VERSION 5.8 ;
BUSBITCHARS "[]" ;
DIVIDERCHAR "/" ;
UNITS
    DATABASE MICRONS 1000 ;
END UNITS

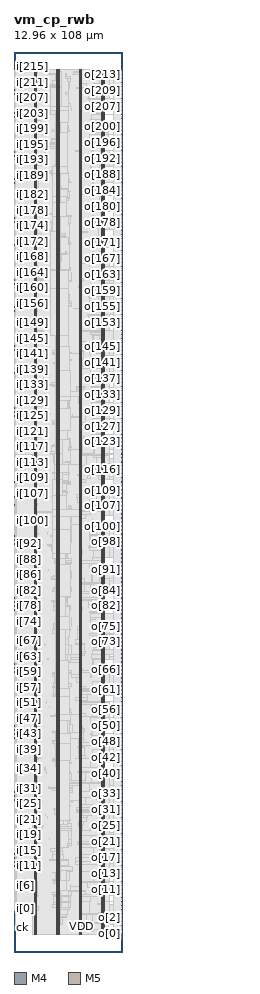
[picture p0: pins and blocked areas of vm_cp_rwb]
MACRO vm_cp_rwb
  FOREIGN vm_cp_rwb 0 0 ;
  CLASS BLOCK ;
  SIZE 12.96 BY 108 ;
  PIN ck
    DIRECTION INPUT ;
    USE SIGNAL ;
    PORT
      LAYER M4 ;
        RECT  0 2.976 0.084 3 ;
    END
    PORT
      LAYER M4 ;
        RECT  0.06 2.976 0.227 3 ;
    END
  END ck
  PIN i[0]
    DIRECTION INPUT ;
    USE SIGNAL ;
    PORT
      LAYER M4 ;
        RECT  0 5.232 0.084 5.256 ;
    END
  END i[0]
  PIN i[100]
    DIRECTION INPUT ;
    USE SIGNAL ;
    PORT
      LAYER M4 ;
        RECT  0 51.744 0.084 51.768 ;
    END
  END i[100]
  PIN i[101]
    DIRECTION INPUT ;
    USE SIGNAL ;
    PORT
      LAYER M4 ;
        RECT  0 52.224 0.084 52.248 ;
    END
  END i[101]
  PIN i[102]
    DIRECTION INPUT ;
    USE SIGNAL ;
    PORT
      LAYER M4 ;
        RECT  0 52.704 0.084 52.728 ;
    END
  END i[102]
  PIN i[103]
    DIRECTION INPUT ;
    USE SIGNAL ;
    PORT
      LAYER M4 ;
        RECT  0 53.184 0.084 53.208 ;
    END
  END i[103]
  PIN i[104]
    DIRECTION INPUT ;
    USE SIGNAL ;
    PORT
      LAYER M4 ;
        RECT  0 53.616 0.084 53.64 ;
    END
  END i[104]
  PIN i[105]
    DIRECTION INPUT ;
    USE SIGNAL ;
    PORT
      LAYER M4 ;
        RECT  0 54.096 0.084 54.12 ;
    END
  END i[105]
  PIN i[106]
    DIRECTION INPUT ;
    USE SIGNAL ;
    PORT
      LAYER M4 ;
        RECT  0 54.576 0.084 54.6 ;
    END
  END i[106]
  PIN i[107]
    DIRECTION INPUT ;
    USE SIGNAL ;
    PORT
      LAYER M4 ;
        RECT  0 55.008 0.084 55.032 ;
    END
  END i[107]
  PIN i[108]
    DIRECTION INPUT ;
    USE SIGNAL ;
    PORT
      LAYER M4 ;
        RECT  0 55.488 0.084 55.512 ;
    END
  END i[108]
  PIN i[109]
    DIRECTION INPUT ;
    USE SIGNAL ;
    PORT
      LAYER M4 ;
        RECT  0 55.968 0.084 55.992 ;
    END
  END i[109]
  PIN i[10]
    DIRECTION INPUT ;
    USE SIGNAL ;
    PORT
      LAYER M4 ;
        RECT  0 9.888 0.084 9.912 ;
    END
  END i[10]
  PIN i[110]
    DIRECTION INPUT ;
    USE SIGNAL ;
    PORT
      LAYER M4 ;
        RECT  0 56.4 0.084 56.424 ;
    END
  END i[110]
  PIN i[111]
    DIRECTION INPUT ;
    USE SIGNAL ;
    PORT
      LAYER M4 ;
        RECT  0 56.88 0.084 56.904 ;
    END
  END i[111]
  PIN i[112]
    DIRECTION INPUT ;
    USE SIGNAL ;
    PORT
      LAYER M4 ;
        RECT  0 57.36 0.084 57.384 ;
    END
  END i[112]
  PIN i[113]
    DIRECTION INPUT ;
    USE SIGNAL ;
    PORT
      LAYER M4 ;
        RECT  0 57.792 0.084 57.816 ;
    END
  END i[113]
  PIN i[114]
    DIRECTION INPUT ;
    USE SIGNAL ;
    PORT
      LAYER M4 ;
        RECT  0 58.272 0.084 58.296 ;
    END
  END i[114]
  PIN i[115]
    DIRECTION INPUT ;
    USE SIGNAL ;
    PORT
      LAYER M4 ;
        RECT  0 58.752 0.084 58.776 ;
    END
  END i[115]
  PIN i[116]
    DIRECTION INPUT ;
    USE SIGNAL ;
    PORT
      LAYER M4 ;
        RECT  0 59.232 0.084 59.256 ;
    END
  END i[116]
  PIN i[117]
    DIRECTION INPUT ;
    USE SIGNAL ;
    PORT
      LAYER M4 ;
        RECT  0 59.664 0.084 59.688 ;
    END
  END i[117]
  PIN i[118]
    DIRECTION INPUT ;
    USE SIGNAL ;
    PORT
      LAYER M4 ;
        RECT  0 60.144 0.084 60.168 ;
    END
  END i[118]
  PIN i[119]
    DIRECTION INPUT ;
    USE SIGNAL ;
    PORT
      LAYER M4 ;
        RECT  0 60.624 0.084 60.648 ;
    END
  END i[119]
  PIN i[11]
    DIRECTION INPUT ;
    USE SIGNAL ;
    PORT
      LAYER M4 ;
        RECT  0 10.32 0.084 10.344 ;
    END
  END i[11]
  PIN i[120]
    DIRECTION INPUT ;
    USE SIGNAL ;
    PORT
      LAYER M4 ;
        RECT  0 61.056 0.084 61.08 ;
    END
  END i[120]
  PIN i[121]
    DIRECTION INPUT ;
    USE SIGNAL ;
    PORT
      LAYER M4 ;
        RECT  0 61.536 0.084 61.56 ;
    END
  END i[121]
  PIN i[122]
    DIRECTION INPUT ;
    USE SIGNAL ;
    PORT
      LAYER M4 ;
        RECT  0 62.016 0.084 62.04 ;
    END
  END i[122]
  PIN i[123]
    DIRECTION INPUT ;
    USE SIGNAL ;
    PORT
      LAYER M4 ;
        RECT  0 62.448 0.084 62.472 ;
    END
  END i[123]
  PIN i[124]
    DIRECTION INPUT ;
    USE SIGNAL ;
    PORT
      LAYER M4 ;
        RECT  0 62.928 0.084 62.952 ;
    END
  END i[124]
  PIN i[125]
    DIRECTION INPUT ;
    USE SIGNAL ;
    PORT
      LAYER M4 ;
        RECT  0 63.408 0.084 63.432 ;
    END
  END i[125]
  PIN i[126]
    DIRECTION INPUT ;
    USE SIGNAL ;
    PORT
      LAYER M4 ;
        RECT  0 63.888 0.084 63.912 ;
    END
  END i[126]
  PIN i[127]
    DIRECTION INPUT ;
    USE SIGNAL ;
    PORT
      LAYER M4 ;
        RECT  0 64.32 0.084 64.344 ;
    END
  END i[127]
  PIN i[128]
    DIRECTION INPUT ;
    USE SIGNAL ;
    PORT
      LAYER M4 ;
        RECT  0 64.8 0.084 64.824 ;
    END
  END i[128]
  PIN i[129]
    DIRECTION INPUT ;
    USE SIGNAL ;
    PORT
      LAYER M4 ;
        RECT  0 65.28 0.084 65.304 ;
    END
  END i[129]
  PIN i[12]
    DIRECTION INPUT ;
    USE SIGNAL ;
    PORT
      LAYER M4 ;
        RECT  0 10.8 0.084 10.824 ;
    END
  END i[12]
  PIN i[130]
    DIRECTION INPUT ;
    USE SIGNAL ;
    PORT
      LAYER M4 ;
        RECT  0 65.712 0.084 65.736 ;
    END
  END i[130]
  PIN i[131]
    DIRECTION INPUT ;
    USE SIGNAL ;
    PORT
      LAYER M4 ;
        RECT  0 66.192 0.084 66.216 ;
    END
  END i[131]
  PIN i[132]
    DIRECTION INPUT ;
    USE SIGNAL ;
    PORT
      LAYER M4 ;
        RECT  0 66.672 0.084 66.696 ;
    END
  END i[132]
  PIN i[133]
    DIRECTION INPUT ;
    USE SIGNAL ;
    PORT
      LAYER M4 ;
        RECT  0 67.104 0.084 67.128 ;
    END
  END i[133]
  PIN i[134]
    DIRECTION INPUT ;
    USE SIGNAL ;
    PORT
      LAYER M4 ;
        RECT  0 67.584 0.084 67.608 ;
    END
  END i[134]
  PIN i[135]
    DIRECTION INPUT ;
    USE SIGNAL ;
    PORT
      LAYER M4 ;
        RECT  0 68.064 0.084 68.088 ;
    END
  END i[135]
  PIN i[136]
    DIRECTION INPUT ;
    USE SIGNAL ;
    PORT
      LAYER M4 ;
        RECT  0 68.544 0.084 68.568 ;
    END
  END i[136]
  PIN i[137]
    DIRECTION INPUT ;
    USE SIGNAL ;
    PORT
      LAYER M4 ;
        RECT  0 68.976 0.084 69 ;
    END
  END i[137]
  PIN i[138]
    DIRECTION INPUT ;
    USE SIGNAL ;
    PORT
      LAYER M4 ;
        RECT  0 69.456 0.084 69.48 ;
    END
  END i[138]
  PIN i[139]
    DIRECTION INPUT ;
    USE SIGNAL ;
    PORT
      LAYER M4 ;
        RECT  0 69.936 0.084 69.96 ;
    END
  END i[139]
  PIN i[13]
    DIRECTION INPUT ;
    USE SIGNAL ;
    PORT
      LAYER M4 ;
        RECT  0 11.28 0.084 11.304 ;
    END
  END i[13]
  PIN i[140]
    DIRECTION INPUT ;
    USE SIGNAL ;
    PORT
      LAYER M4 ;
        RECT  0 70.368 0.084 70.392 ;
    END
  END i[140]
  PIN i[141]
    DIRECTION INPUT ;
    USE SIGNAL ;
    PORT
      LAYER M4 ;
        RECT  0 70.848 0.084 70.872 ;
    END
  END i[141]
  PIN i[142]
    DIRECTION INPUT ;
    USE SIGNAL ;
    PORT
      LAYER M4 ;
        RECT  0 71.328 0.084 71.352 ;
    END
  END i[142]
  PIN i[143]
    DIRECTION INPUT ;
    USE SIGNAL ;
    PORT
      LAYER M4 ;
        RECT  0 71.76 0.084 71.784 ;
    END
  END i[143]
  PIN i[144]
    DIRECTION INPUT ;
    USE SIGNAL ;
    PORT
      LAYER M4 ;
        RECT  0 72.24 0.084 72.264 ;
    END
  END i[144]
  PIN i[145]
    DIRECTION INPUT ;
    USE SIGNAL ;
    PORT
      LAYER M4 ;
        RECT  0 72.72 0.084 72.744 ;
    END
  END i[145]
  PIN i[146]
    DIRECTION INPUT ;
    USE SIGNAL ;
    PORT
      LAYER M4 ;
        RECT  0 73.152 0.084 73.176 ;
    END
  END i[146]
  PIN i[147]
    DIRECTION INPUT ;
    USE SIGNAL ;
    PORT
      LAYER M4 ;
        RECT  0 73.632 0.084 73.656 ;
    END
  END i[147]
  PIN i[148]
    DIRECTION INPUT ;
    USE SIGNAL ;
    PORT
      LAYER M4 ;
        RECT  0 74.112 0.084 74.136 ;
    END
  END i[148]
  PIN i[149]
    DIRECTION INPUT ;
    USE SIGNAL ;
    PORT
      LAYER M4 ;
        RECT  0 74.592 0.084 74.616 ;
    END
  END i[149]
  PIN i[14]
    DIRECTION INPUT ;
    USE SIGNAL ;
    PORT
      LAYER M4 ;
        RECT  0 11.76 0.084 11.784 ;
    END
  END i[14]
  PIN i[150]
    DIRECTION INPUT ;
    USE SIGNAL ;
    PORT
      LAYER M4 ;
        RECT  0 75.024 0.084 75.048 ;
    END
  END i[150]
  PIN i[151]
    DIRECTION INPUT ;
    USE SIGNAL ;
    PORT
      LAYER M4 ;
        RECT  0 75.504 0.084 75.528 ;
    END
  END i[151]
  PIN i[152]
    DIRECTION INPUT ;
    USE SIGNAL ;
    PORT
      LAYER M4 ;
        RECT  0 75.984 0.084 76.008 ;
    END
  END i[152]
  PIN i[153]
    DIRECTION INPUT ;
    USE SIGNAL ;
    PORT
      LAYER M4 ;
        RECT  0 76.416 0.084 76.44 ;
    END
  END i[153]
  PIN i[154]
    DIRECTION INPUT ;
    USE SIGNAL ;
    PORT
      LAYER M4 ;
        RECT  0 76.896 0.084 76.92 ;
    END
  END i[154]
  PIN i[155]
    DIRECTION INPUT ;
    USE SIGNAL ;
    PORT
      LAYER M4 ;
        RECT  0 77.376 0.084 77.4 ;
    END
  END i[155]
  PIN i[156]
    DIRECTION INPUT ;
    USE SIGNAL ;
    PORT
      LAYER M4 ;
        RECT  0 77.808 0.084 77.832 ;
    END
  END i[156]
  PIN i[157]
    DIRECTION INPUT ;
    USE SIGNAL ;
    PORT
      LAYER M4 ;
        RECT  0 78.288 0.084 78.312 ;
    END
  END i[157]
  PIN i[158]
    DIRECTION INPUT ;
    USE SIGNAL ;
    PORT
      LAYER M4 ;
        RECT  0 78.768 0.084 78.792 ;
    END
  END i[158]
  PIN i[159]
    DIRECTION INPUT ;
    USE SIGNAL ;
    PORT
      LAYER M4 ;
        RECT  0 79.248 0.084 79.272 ;
    END
  END i[159]
  PIN i[15]
    DIRECTION INPUT ;
    USE SIGNAL ;
    PORT
      LAYER M4 ;
        RECT  0 12.192 0.084 12.216 ;
    END
  END i[15]
  PIN i[160]
    DIRECTION INPUT ;
    USE SIGNAL ;
    PORT
      LAYER M4 ;
        RECT  0 79.68 0.084 79.704 ;
    END
  END i[160]
  PIN i[161]
    DIRECTION INPUT ;
    USE SIGNAL ;
    PORT
      LAYER M4 ;
        RECT  0 80.16 0.084 80.184 ;
    END
  END i[161]
  PIN i[162]
    DIRECTION INPUT ;
    USE SIGNAL ;
    PORT
      LAYER M4 ;
        RECT  0 80.64 0.084 80.664 ;
    END
  END i[162]
  PIN i[163]
    DIRECTION INPUT ;
    USE SIGNAL ;
    PORT
      LAYER M4 ;
        RECT  0 81.072 0.084 81.096 ;
    END
  END i[163]
  PIN i[164]
    DIRECTION INPUT ;
    USE SIGNAL ;
    PORT
      LAYER M4 ;
        RECT  0 81.552 0.084 81.576 ;
    END
  END i[164]
  PIN i[165]
    DIRECTION INPUT ;
    USE SIGNAL ;
    PORT
      LAYER M4 ;
        RECT  0 82.032 0.084 82.056 ;
    END
  END i[165]
  PIN i[166]
    DIRECTION INPUT ;
    USE SIGNAL ;
    PORT
      LAYER M4 ;
        RECT  0 82.464 0.084 82.488 ;
    END
  END i[166]
  PIN i[167]
    DIRECTION INPUT ;
    USE SIGNAL ;
    PORT
      LAYER M4 ;
        RECT  0 82.944 0.084 82.968 ;
    END
  END i[167]
  PIN i[168]
    DIRECTION INPUT ;
    USE SIGNAL ;
    PORT
      LAYER M4 ;
        RECT  0 83.424 0.084 83.448 ;
    END
  END i[168]
  PIN i[169]
    DIRECTION INPUT ;
    USE SIGNAL ;
    PORT
      LAYER M4 ;
        RECT  0 83.904 0.084 83.928 ;
    END
  END i[169]
  PIN i[16]
    DIRECTION INPUT ;
    USE SIGNAL ;
    PORT
      LAYER M4 ;
        RECT  0 12.672 0.084 12.696 ;
    END
  END i[16]
  PIN i[170]
    DIRECTION INPUT ;
    USE SIGNAL ;
    PORT
      LAYER M4 ;
        RECT  0 84.336 0.084 84.36 ;
    END
  END i[170]
  PIN i[171]
    DIRECTION INPUT ;
    USE SIGNAL ;
    PORT
      LAYER M4 ;
        RECT  0 84.816 0.084 84.84 ;
    END
  END i[171]
  PIN i[172]
    DIRECTION INPUT ;
    USE SIGNAL ;
    PORT
      LAYER M4 ;
        RECT  0 85.296 0.084 85.32 ;
    END
  END i[172]
  PIN i[173]
    DIRECTION INPUT ;
    USE SIGNAL ;
    PORT
      LAYER M4 ;
        RECT  0 85.728 0.084 85.752 ;
    END
  END i[173]
  PIN i[174]
    DIRECTION INPUT ;
    USE SIGNAL ;
    PORT
      LAYER M4 ;
        RECT  0 86.208 0.084 86.232 ;
    END
  END i[174]
  PIN i[175]
    DIRECTION INPUT ;
    USE SIGNAL ;
    PORT
      LAYER M4 ;
        RECT  0 86.688 0.084 86.712 ;
    END
  END i[175]
  PIN i[176]
    DIRECTION INPUT ;
    USE SIGNAL ;
    PORT
      LAYER M4 ;
        RECT  0 87.12 0.084 87.144 ;
    END
  END i[176]
  PIN i[177]
    DIRECTION INPUT ;
    USE SIGNAL ;
    PORT
      LAYER M4 ;
        RECT  0 87.6 0.084 87.624 ;
    END
  END i[177]
  PIN i[178]
    DIRECTION INPUT ;
    USE SIGNAL ;
    PORT
      LAYER M4 ;
        RECT  0 88.08 0.084 88.104 ;
    END
  END i[178]
  PIN i[179]
    DIRECTION INPUT ;
    USE SIGNAL ;
    PORT
      LAYER M4 ;
        RECT  0 88.512 0.084 88.536 ;
    END
  END i[179]
  PIN i[17]
    DIRECTION INPUT ;
    USE SIGNAL ;
    PORT
      LAYER M4 ;
        RECT  0 13.152 0.084 13.176 ;
    END
  END i[17]
  PIN i[180]
    DIRECTION INPUT ;
    USE SIGNAL ;
    PORT
      LAYER M4 ;
        RECT  0 88.992 0.084 89.016 ;
    END
  END i[180]
  PIN i[181]
    DIRECTION INPUT ;
    USE SIGNAL ;
    PORT
      LAYER M4 ;
        RECT  0 89.472 0.084 89.496 ;
    END
  END i[181]
  PIN i[182]
    DIRECTION INPUT ;
    USE SIGNAL ;
    PORT
      LAYER M4 ;
        RECT  0 89.952 0.084 89.976 ;
    END
  END i[182]
  PIN i[183]
    DIRECTION INPUT ;
    USE SIGNAL ;
    PORT
      LAYER M4 ;
        RECT  0 90.384 0.084 90.408 ;
    END
  END i[183]
  PIN i[184]
    DIRECTION INPUT ;
    USE SIGNAL ;
    PORT
      LAYER M4 ;
        RECT  0 90.864 0.084 90.888 ;
    END
  END i[184]
  PIN i[185]
    DIRECTION INPUT ;
    USE SIGNAL ;
    PORT
      LAYER M4 ;
        RECT  0 91.344 0.084 91.368 ;
    END
  END i[185]
  PIN i[186]
    DIRECTION INPUT ;
    USE SIGNAL ;
    PORT
      LAYER M4 ;
        RECT  0 91.776 0.084 91.8 ;
    END
  END i[186]
  PIN i[187]
    DIRECTION INPUT ;
    USE SIGNAL ;
    PORT
      LAYER M4 ;
        RECT  0 92.256 0.084 92.28 ;
    END
  END i[187]
  PIN i[188]
    DIRECTION INPUT ;
    USE SIGNAL ;
    PORT
      LAYER M4 ;
        RECT  0 92.736 0.084 92.76 ;
    END
  END i[188]
  PIN i[189]
    DIRECTION INPUT ;
    USE SIGNAL ;
    PORT
      LAYER M4 ;
        RECT  0 93.168 0.084 93.192 ;
    END
  END i[189]
  PIN i[18]
    DIRECTION INPUT ;
    USE SIGNAL ;
    PORT
      LAYER M4 ;
        RECT  0 13.584 0.084 13.608 ;
    END
  END i[18]
  PIN i[190]
    DIRECTION INPUT ;
    USE SIGNAL ;
    PORT
      LAYER M4 ;
        RECT  0 93.648 0.084 93.672 ;
    END
  END i[190]
  PIN i[191]
    DIRECTION INPUT ;
    USE SIGNAL ;
    PORT
      LAYER M4 ;
        RECT  0 94.128 0.084 94.152 ;
    END
  END i[191]
  PIN i[192]
    DIRECTION INPUT ;
    USE SIGNAL ;
    PORT
      LAYER M4 ;
        RECT  0 94.608 0.084 94.632 ;
    END
  END i[192]
  PIN i[193]
    DIRECTION INPUT ;
    USE SIGNAL ;
    PORT
      LAYER M4 ;
        RECT  0 95.04 0.084 95.064 ;
    END
  END i[193]
  PIN i[194]
    DIRECTION INPUT ;
    USE SIGNAL ;
    PORT
      LAYER M4 ;
        RECT  0 95.52 0.084 95.544 ;
    END
  END i[194]
  PIN i[195]
    DIRECTION INPUT ;
    USE SIGNAL ;
    PORT
      LAYER M4 ;
        RECT  0 96 0.084 96.024 ;
    END
  END i[195]
  PIN i[196]
    DIRECTION INPUT ;
    USE SIGNAL ;
    PORT
      LAYER M4 ;
        RECT  0 96.432 0.084 96.456 ;
    END
  END i[196]
  PIN i[197]
    DIRECTION INPUT ;
    USE SIGNAL ;
    PORT
      LAYER M4 ;
        RECT  0 96.912 0.084 96.936 ;
    END
  END i[197]
  PIN i[198]
    DIRECTION INPUT ;
    USE SIGNAL ;
    PORT
      LAYER M4 ;
        RECT  0 97.392 0.084 97.416 ;
    END
  END i[198]
  PIN i[199]
    DIRECTION INPUT ;
    USE SIGNAL ;
    PORT
      LAYER M4 ;
        RECT  0 97.824 0.084 97.848 ;
    END
  END i[199]
  PIN i[19]
    DIRECTION INPUT ;
    USE SIGNAL ;
    PORT
      LAYER M4 ;
        RECT  0 14.064 0.084 14.088 ;
    END
  END i[19]
  PIN i[1]
    DIRECTION INPUT ;
    USE SIGNAL ;
    PORT
      LAYER M4 ;
        RECT  0 5.664 0.084 5.688 ;
    END
  END i[1]
  PIN i[200]
    DIRECTION INPUT ;
    USE SIGNAL ;
    PORT
      LAYER M4 ;
        RECT  0 98.304 0.084 98.328 ;
    END
  END i[200]
  PIN i[201]
    DIRECTION INPUT ;
    USE SIGNAL ;
    PORT
      LAYER M4 ;
        RECT  0 98.784 0.084 98.808 ;
    END
  END i[201]
  PIN i[202]
    DIRECTION INPUT ;
    USE SIGNAL ;
    PORT
      LAYER M4 ;
        RECT  0 99.216 0.084 99.24 ;
    END
  END i[202]
  PIN i[203]
    DIRECTION INPUT ;
    USE SIGNAL ;
    PORT
      LAYER M4 ;
        RECT  0 99.696 0.084 99.72 ;
    END
  END i[203]
  PIN i[204]
    DIRECTION INPUT ;
    USE SIGNAL ;
    PORT
      LAYER M4 ;
        RECT  0 100.176 0.084 100.2 ;
    END
  END i[204]
  PIN i[205]
    DIRECTION INPUT ;
    USE SIGNAL ;
    PORT
      LAYER M4 ;
        RECT  0 100.656 0.084 100.68 ;
    END
  END i[205]
  PIN i[206]
    DIRECTION INPUT ;
    USE SIGNAL ;
    PORT
      LAYER M4 ;
        RECT  0 101.088 0.084 101.112 ;
    END
  END i[206]
  PIN i[207]
    DIRECTION INPUT ;
    USE SIGNAL ;
    PORT
      LAYER M4 ;
        RECT  0 101.568 0.084 101.592 ;
    END
  END i[207]
  PIN i[208]
    DIRECTION INPUT ;
    USE SIGNAL ;
    PORT
      LAYER M4 ;
        RECT  0 102.048 0.084 102.072 ;
    END
  END i[208]
  PIN i[209]
    DIRECTION INPUT ;
    USE SIGNAL ;
    PORT
      LAYER M4 ;
        RECT  0 102.48 0.084 102.504 ;
    END
  END i[209]
  PIN i[20]
    DIRECTION INPUT ;
    USE SIGNAL ;
    PORT
      LAYER M4 ;
        RECT  0 14.544 0.084 14.568 ;
    END
  END i[20]
  PIN i[210]
    DIRECTION INPUT ;
    USE SIGNAL ;
    PORT
      LAYER M4 ;
        RECT  0 102.96 0.084 102.984 ;
    END
  END i[210]
  PIN i[211]
    DIRECTION INPUT ;
    USE SIGNAL ;
    PORT
      LAYER M4 ;
        RECT  0 103.44 0.084 103.464 ;
    END
  END i[211]
  PIN i[212]
    DIRECTION INPUT ;
    USE SIGNAL ;
    PORT
      LAYER M4 ;
        RECT  0 103.872 0.084 103.896 ;
    END
  END i[212]
  PIN i[213]
    DIRECTION INPUT ;
    USE SIGNAL ;
    PORT
      LAYER M4 ;
        RECT  0 104.352 0.084 104.376 ;
    END
  END i[213]
  PIN i[214]
    DIRECTION INPUT ;
    USE SIGNAL ;
    PORT
      LAYER M4 ;
        RECT  0 104.832 0.084 104.856 ;
    END
  END i[214]
  PIN i[215]
    DIRECTION INPUT ;
    USE SIGNAL ;
    PORT
      LAYER M4 ;
        RECT  0 105.312 0.084 105.336 ;
    END
  END i[215]
  PIN i[216]
    DIRECTION INPUT ;
    USE SIGNAL ;
    PORT
      LAYER M4 ;
        RECT  0 105.744 0.084 105.768 ;
    END
  END i[216]
  PIN i[21]
    DIRECTION INPUT ;
    USE SIGNAL ;
    PORT
      LAYER M4 ;
        RECT  0 14.976 0.084 15 ;
    END
  END i[21]
  PIN i[22]
    DIRECTION INPUT ;
    USE SIGNAL ;
    PORT
      LAYER M4 ;
        RECT  0 15.456 0.084 15.48 ;
    END
  END i[22]
  PIN i[23]
    DIRECTION INPUT ;
    USE SIGNAL ;
    PORT
      LAYER M4 ;
        RECT  0 15.936 0.084 15.96 ;
    END
  END i[23]
  PIN i[24]
    DIRECTION INPUT ;
    USE SIGNAL ;
    PORT
      LAYER M4 ;
        RECT  0 16.368 0.084 16.392 ;
    END
  END i[24]
  PIN i[25]
    DIRECTION INPUT ;
    USE SIGNAL ;
    PORT
      LAYER M4 ;
        RECT  0 16.848 0.084 16.872 ;
    END
  END i[25]
  PIN i[26]
    DIRECTION INPUT ;
    USE SIGNAL ;
    PORT
      LAYER M4 ;
        RECT  0 17.328 0.084 17.352 ;
    END
  END i[26]
  PIN i[27]
    DIRECTION INPUT ;
    USE SIGNAL ;
    PORT
      LAYER M4 ;
        RECT  0 17.808 0.084 17.832 ;
    END
  END i[27]
  PIN i[28]
    DIRECTION INPUT ;
    USE SIGNAL ;
    PORT
      LAYER M4 ;
        RECT  0 18.24 0.084 18.264 ;
    END
  END i[28]
  PIN i[29]
    DIRECTION INPUT ;
    USE SIGNAL ;
    PORT
      LAYER M4 ;
        RECT  0 18.72 0.084 18.744 ;
    END
  END i[29]
  PIN i[2]
    DIRECTION INPUT ;
    USE SIGNAL ;
    PORT
      LAYER M4 ;
        RECT  0 6.144 0.084 6.168 ;
    END
  END i[2]
  PIN i[30]
    DIRECTION INPUT ;
    USE SIGNAL ;
    PORT
      LAYER M4 ;
        RECT  0 19.2 0.084 19.224 ;
    END
  END i[30]
  PIN i[31]
    DIRECTION INPUT ;
    USE SIGNAL ;
    PORT
      LAYER M4 ;
        RECT  0 19.632 0.084 19.656 ;
    END
  END i[31]
  PIN i[32]
    DIRECTION INPUT ;
    USE SIGNAL ;
    PORT
      LAYER M4 ;
        RECT  0 20.112 0.084 20.136 ;
    END
  END i[32]
  PIN i[33]
    DIRECTION INPUT ;
    USE SIGNAL ;
    PORT
      LAYER M4 ;
        RECT  0 20.592 0.084 20.616 ;
    END
  END i[33]
  PIN i[34]
    DIRECTION INPUT ;
    USE SIGNAL ;
    PORT
      LAYER M4 ;
        RECT  0 21.024 0.084 21.048 ;
    END
  END i[34]
  PIN i[35]
    DIRECTION INPUT ;
    USE SIGNAL ;
    PORT
      LAYER M4 ;
        RECT  0 21.504 0.084 21.528 ;
    END
  END i[35]
  PIN i[36]
    DIRECTION INPUT ;
    USE SIGNAL ;
    PORT
      LAYER M4 ;
        RECT  0 21.984 0.084 22.008 ;
    END
  END i[36]
  PIN i[37]
    DIRECTION INPUT ;
    USE SIGNAL ;
    PORT
      LAYER M4 ;
        RECT  0 22.464 0.084 22.488 ;
    END
  END i[37]
  PIN i[38]
    DIRECTION INPUT ;
    USE SIGNAL ;
    PORT
      LAYER M4 ;
        RECT  0 22.896 0.084 22.92 ;
    END
  END i[38]
  PIN i[39]
    DIRECTION INPUT ;
    USE SIGNAL ;
    PORT
      LAYER M4 ;
        RECT  0 23.376 0.084 23.4 ;
    END
  END i[39]
  PIN i[3]
    DIRECTION INPUT ;
    USE SIGNAL ;
    PORT
      LAYER M4 ;
        RECT  0 6.624 0.084 6.648 ;
    END
  END i[3]
  PIN i[40]
    DIRECTION INPUT ;
    USE SIGNAL ;
    PORT
      LAYER M4 ;
        RECT  0 23.856 0.084 23.88 ;
    END
  END i[40]
  PIN i[41]
    DIRECTION INPUT ;
    USE SIGNAL ;
    PORT
      LAYER M4 ;
        RECT  0 24.288 0.084 24.312 ;
    END
  END i[41]
  PIN i[42]
    DIRECTION INPUT ;
    USE SIGNAL ;
    PORT
      LAYER M4 ;
        RECT  0 24.768 0.084 24.792 ;
    END
  END i[42]
  PIN i[43]
    DIRECTION INPUT ;
    USE SIGNAL ;
    PORT
      LAYER M4 ;
        RECT  0 25.248 0.084 25.272 ;
    END
  END i[43]
  PIN i[44]
    DIRECTION INPUT ;
    USE SIGNAL ;
    PORT
      LAYER M4 ;
        RECT  0 25.68 0.084 25.704 ;
    END
  END i[44]
  PIN i[45]
    DIRECTION INPUT ;
    USE SIGNAL ;
    PORT
      LAYER M4 ;
        RECT  0 26.16 0.084 26.184 ;
    END
  END i[45]
  PIN i[46]
    DIRECTION INPUT ;
    USE SIGNAL ;
    PORT
      LAYER M4 ;
        RECT  0 26.64 0.084 26.664 ;
    END
  END i[46]
  PIN i[47]
    DIRECTION INPUT ;
    USE SIGNAL ;
    PORT
      LAYER M4 ;
        RECT  0 27.12 0.084 27.144 ;
    END
  END i[47]
  PIN i[48]
    DIRECTION INPUT ;
    USE SIGNAL ;
    PORT
      LAYER M4 ;
        RECT  0 27.552 0.084 27.576 ;
    END
  END i[48]
  PIN i[49]
    DIRECTION INPUT ;
    USE SIGNAL ;
    PORT
      LAYER M4 ;
        RECT  0 28.032 0.084 28.056 ;
    END
  END i[49]
  PIN i[4]
    DIRECTION INPUT ;
    USE SIGNAL ;
    PORT
      LAYER M4 ;
        RECT  0 7.104 0.084 7.128 ;
    END
  END i[4]
  PIN i[50]
    DIRECTION INPUT ;
    USE SIGNAL ;
    PORT
      LAYER M4 ;
        RECT  0 28.512 0.084 28.536 ;
    END
  END i[50]
  PIN i[51]
    DIRECTION INPUT ;
    USE SIGNAL ;
    PORT
      LAYER M4 ;
        RECT  0 28.944 0.084 28.968 ;
    END
  END i[51]
  PIN i[52]
    DIRECTION INPUT ;
    USE SIGNAL ;
    PORT
      LAYER M4 ;
        RECT  0 29.424 0.084 29.448 ;
    END
  END i[52]
  PIN i[53]
    DIRECTION INPUT ;
    USE SIGNAL ;
    PORT
      LAYER M4 ;
        RECT  0 29.904 0.084 29.928 ;
    END
  END i[53]
  PIN i[54]
    DIRECTION INPUT ;
    USE SIGNAL ;
    PORT
      LAYER M4 ;
        RECT  0 30.336 0.084 30.36 ;
    END
  END i[54]
  PIN i[55]
    DIRECTION INPUT ;
    USE SIGNAL ;
    PORT
      LAYER M4 ;
        RECT  0 30.816 0.084 30.84 ;
    END
  END i[55]
  PIN i[56]
    DIRECTION INPUT ;
    USE SIGNAL ;
    PORT
      LAYER M4 ;
        RECT  0 31.296 0.084 31.32 ;
    END
  END i[56]
  PIN i[57]
    DIRECTION INPUT ;
    USE SIGNAL ;
    PORT
      LAYER M4 ;
        RECT  0 31.728 0.084 31.752 ;
    END
  END i[57]
  PIN i[58]
    DIRECTION INPUT ;
    USE SIGNAL ;
    PORT
      LAYER M4 ;
        RECT  0 32.208 0.084 32.232 ;
    END
  END i[58]
  PIN i[59]
    DIRECTION INPUT ;
    USE SIGNAL ;
    PORT
      LAYER M4 ;
        RECT  0 32.688 0.084 32.712 ;
    END
  END i[59]
  PIN i[5]
    DIRECTION INPUT ;
    USE SIGNAL ;
    PORT
      LAYER M4 ;
        RECT  0 7.536 0.084 7.56 ;
    END
  END i[5]
  PIN i[60]
    DIRECTION INPUT ;
    USE SIGNAL ;
    PORT
      LAYER M4 ;
        RECT  0 33.168 0.084 33.192 ;
    END
  END i[60]
  PIN i[61]
    DIRECTION INPUT ;
    USE SIGNAL ;
    PORT
      LAYER M4 ;
        RECT  0 33.6 0.084 33.624 ;
    END
  END i[61]
  PIN i[62]
    DIRECTION INPUT ;
    USE SIGNAL ;
    PORT
      LAYER M4 ;
        RECT  0 34.08 0.084 34.104 ;
    END
  END i[62]
  PIN i[63]
    DIRECTION INPUT ;
    USE SIGNAL ;
    PORT
      LAYER M4 ;
        RECT  0 34.56 0.084 34.584 ;
    END
  END i[63]
  PIN i[64]
    DIRECTION INPUT ;
    USE SIGNAL ;
    PORT
      LAYER M4 ;
        RECT  0 34.992 0.084 35.016 ;
    END
  END i[64]
  PIN i[65]
    DIRECTION INPUT ;
    USE SIGNAL ;
    PORT
      LAYER M4 ;
        RECT  0 35.472 0.084 35.496 ;
    END
  END i[65]
  PIN i[66]
    DIRECTION INPUT ;
    USE SIGNAL ;
    PORT
      LAYER M4 ;
        RECT  0 35.952 0.084 35.976 ;
    END
  END i[66]
  PIN i[67]
    DIRECTION INPUT ;
    USE SIGNAL ;
    PORT
      LAYER M4 ;
        RECT  0 36.384 0.084 36.408 ;
    END
  END i[67]
  PIN i[68]
    DIRECTION INPUT ;
    USE SIGNAL ;
    PORT
      LAYER M4 ;
        RECT  0 36.864 0.084 36.888 ;
    END
  END i[68]
  PIN i[69]
    DIRECTION INPUT ;
    USE SIGNAL ;
    PORT
      LAYER M4 ;
        RECT  0 37.344 0.084 37.368 ;
    END
  END i[69]
  PIN i[6]
    DIRECTION INPUT ;
    USE SIGNAL ;
    PORT
      LAYER M4 ;
        RECT  0 8.016 0.084 8.04 ;
    END
  END i[6]
  PIN i[70]
    DIRECTION INPUT ;
    USE SIGNAL ;
    PORT
      LAYER M4 ;
        RECT  0 37.824 0.084 37.848 ;
    END
  END i[70]
  PIN i[71]
    DIRECTION INPUT ;
    USE SIGNAL ;
    PORT
      LAYER M4 ;
        RECT  0 38.256 0.084 38.28 ;
    END
  END i[71]
  PIN i[72]
    DIRECTION INPUT ;
    USE SIGNAL ;
    PORT
      LAYER M4 ;
        RECT  0 38.736 0.084 38.76 ;
    END
  END i[72]
  PIN i[73]
    DIRECTION INPUT ;
    USE SIGNAL ;
    PORT
      LAYER M4 ;
        RECT  0 39.216 0.084 39.24 ;
    END
  END i[73]
  PIN i[74]
    DIRECTION INPUT ;
    USE SIGNAL ;
    PORT
      LAYER M4 ;
        RECT  0 39.648 0.084 39.672 ;
    END
  END i[74]
  PIN i[75]
    DIRECTION INPUT ;
    USE SIGNAL ;
    PORT
      LAYER M4 ;
        RECT  0 40.128 0.084 40.152 ;
    END
  END i[75]
  PIN i[76]
    DIRECTION INPUT ;
    USE SIGNAL ;
    PORT
      LAYER M4 ;
        RECT  0 40.608 0.084 40.632 ;
    END
  END i[76]
  PIN i[77]
    DIRECTION INPUT ;
    USE SIGNAL ;
    PORT
      LAYER M4 ;
        RECT  0 41.04 0.084 41.064 ;
    END
  END i[77]
  PIN i[78]
    DIRECTION INPUT ;
    USE SIGNAL ;
    PORT
      LAYER M4 ;
        RECT  0 41.52 0.084 41.544 ;
    END
  END i[78]
  PIN i[79]
    DIRECTION INPUT ;
    USE SIGNAL ;
    PORT
      LAYER M4 ;
        RECT  0 42 0.084 42.024 ;
    END
  END i[79]
  PIN i[7]
    DIRECTION INPUT ;
    USE SIGNAL ;
    PORT
      LAYER M4 ;
        RECT  0 8.496 0.084 8.52 ;
    END
  END i[7]
  PIN i[80]
    DIRECTION INPUT ;
    USE SIGNAL ;
    PORT
      LAYER M4 ;
        RECT  0 42.48 0.084 42.504 ;
    END
  END i[80]
  PIN i[81]
    DIRECTION INPUT ;
    USE SIGNAL ;
    PORT
      LAYER M4 ;
        RECT  0 42.912 0.084 42.936 ;
    END
  END i[81]
  PIN i[82]
    DIRECTION INPUT ;
    USE SIGNAL ;
    PORT
      LAYER M4 ;
        RECT  0 43.392 0.084 43.416 ;
    END
  END i[82]
  PIN i[83]
    DIRECTION INPUT ;
    USE SIGNAL ;
    PORT
      LAYER M4 ;
        RECT  0 43.872 0.084 43.896 ;
    END
  END i[83]
  PIN i[84]
    DIRECTION INPUT ;
    USE SIGNAL ;
    PORT
      LAYER M4 ;
        RECT  0 44.304 0.084 44.328 ;
    END
  END i[84]
  PIN i[85]
    DIRECTION INPUT ;
    USE SIGNAL ;
    PORT
      LAYER M4 ;
        RECT  0 44.784 0.084 44.808 ;
    END
  END i[85]
  PIN i[86]
    DIRECTION INPUT ;
    USE SIGNAL ;
    PORT
      LAYER M4 ;
        RECT  0 45.264 0.084 45.288 ;
    END
  END i[86]
  PIN i[87]
    DIRECTION INPUT ;
    USE SIGNAL ;
    PORT
      LAYER M4 ;
        RECT  0 45.696 0.084 45.72 ;
    END
  END i[87]
  PIN i[88]
    DIRECTION INPUT ;
    USE SIGNAL ;
    PORT
      LAYER M4 ;
        RECT  0 46.176 0.084 46.2 ;
    END
  END i[88]
  PIN i[89]
    DIRECTION INPUT ;
    USE SIGNAL ;
    PORT
      LAYER M4 ;
        RECT  0 46.656 0.084 46.68 ;
    END
  END i[89]
  PIN i[8]
    DIRECTION INPUT ;
    USE SIGNAL ;
    PORT
      LAYER M4 ;
        RECT  0 8.928 0.084 8.952 ;
    END
  END i[8]
  PIN i[90]
    DIRECTION INPUT ;
    USE SIGNAL ;
    PORT
      LAYER M4 ;
        RECT  0 47.088 0.084 47.112 ;
    END
  END i[90]
  PIN i[91]
    DIRECTION INPUT ;
    USE SIGNAL ;
    PORT
      LAYER M4 ;
        RECT  0 47.568 0.084 47.592 ;
    END
  END i[91]
  PIN i[92]
    DIRECTION INPUT ;
    USE SIGNAL ;
    PORT
      LAYER M4 ;
        RECT  0 48.048 0.084 48.072 ;
    END
  END i[92]
  PIN i[93]
    DIRECTION INPUT ;
    USE SIGNAL ;
    PORT
      LAYER M4 ;
        RECT  0 48.528 0.084 48.552 ;
    END
  END i[93]
  PIN i[94]
    DIRECTION INPUT ;
    USE SIGNAL ;
    PORT
      LAYER M4 ;
        RECT  0 48.96 0.084 48.984 ;
    END
  END i[94]
  PIN i[95]
    DIRECTION INPUT ;
    USE SIGNAL ;
    PORT
      LAYER M4 ;
        RECT  0 49.44 0.084 49.464 ;
    END
  END i[95]
  PIN i[96]
    DIRECTION INPUT ;
    USE SIGNAL ;
    PORT
      LAYER M4 ;
        RECT  0 49.92 0.084 49.944 ;
    END
  END i[96]
  PIN i[97]
    DIRECTION INPUT ;
    USE SIGNAL ;
    PORT
      LAYER M4 ;
        RECT  0 50.352 0.084 50.376 ;
    END
  END i[97]
  PIN i[98]
    DIRECTION INPUT ;
    USE SIGNAL ;
    PORT
      LAYER M4 ;
        RECT  0 50.832 0.084 50.856 ;
    END
  END i[98]
  PIN i[99]
    DIRECTION INPUT ;
    USE SIGNAL ;
    PORT
      LAYER M4 ;
        RECT  0 51.312 0.084 51.336 ;
    END
  END i[99]
  PIN i[9]
    DIRECTION INPUT ;
    USE SIGNAL ;
    PORT
      LAYER M4 ;
        RECT  0 9.408 0.084 9.432 ;
    END
  END i[9]
  PIN o[0]
    DIRECTION OUTPUT ;
    USE SIGNAL ;
    PORT
      LAYER M4 ;
        RECT  12.876 2.208 12.96 2.232 ;
    END
  END o[0]
  PIN o[100]
    DIRECTION OUTPUT ;
    USE SIGNAL ;
    PORT
      LAYER M4 ;
        RECT  12.876 50.16 12.96 50.184 ;
    END
  END o[100]
  PIN o[101]
    DIRECTION OUTPUT ;
    USE SIGNAL ;
    PORT
      LAYER M4 ;
        RECT  12.876 50.64 12.96 50.664 ;
    END
  END o[101]
  PIN o[102]
    DIRECTION OUTPUT ;
    USE SIGNAL ;
    PORT
      LAYER M4 ;
        RECT  12.876 51.12 12.96 51.144 ;
    END
  END o[102]
  PIN o[103]
    DIRECTION OUTPUT ;
    USE SIGNAL ;
    PORT
      LAYER M4 ;
        RECT  12.876 51.6 12.96 51.624 ;
    END
  END o[103]
  PIN o[104]
    DIRECTION OUTPUT ;
    USE SIGNAL ;
    PORT
      LAYER M4 ;
        RECT  12.876 52.08 12.96 52.104 ;
    END
  END o[104]
  PIN o[105]
    DIRECTION OUTPUT ;
    USE SIGNAL ;
    PORT
      LAYER M4 ;
        RECT  12.876 52.56 12.96 52.584 ;
    END
  END o[105]
  PIN o[106]
    DIRECTION OUTPUT ;
    USE SIGNAL ;
    PORT
      LAYER M4 ;
        RECT  12.876 53.04 12.96 53.064 ;
    END
  END o[106]
  PIN o[107]
    DIRECTION OUTPUT ;
    USE SIGNAL ;
    PORT
      LAYER M4 ;
        RECT  12.876 53.52 12.96 53.544 ;
    END
  END o[107]
  PIN o[108]
    DIRECTION OUTPUT ;
    USE SIGNAL ;
    PORT
      LAYER M4 ;
        RECT  12.876 54 12.96 54.024 ;
    END
  END o[108]
  PIN o[109]
    DIRECTION OUTPUT ;
    USE SIGNAL ;
    PORT
      LAYER M4 ;
        RECT  12.876 54.48 12.96 54.504 ;
    END
  END o[109]
  PIN o[10]
    DIRECTION OUTPUT ;
    USE SIGNAL ;
    PORT
      LAYER M4 ;
        RECT  12.876 7.008 12.96 7.032 ;
    END
  END o[10]
  PIN o[110]
    DIRECTION OUTPUT ;
    USE SIGNAL ;
    PORT
      LAYER M4 ;
        RECT  12.876 54.96 12.96 54.984 ;
    END
  END o[110]
  PIN o[111]
    DIRECTION OUTPUT ;
    USE SIGNAL ;
    PORT
      LAYER M4 ;
        RECT  12.876 55.44 12.96 55.464 ;
    END
  END o[111]
  PIN o[112]
    DIRECTION OUTPUT ;
    USE SIGNAL ;
    PORT
      LAYER M4 ;
        RECT  12.876 55.92 12.96 55.944 ;
    END
  END o[112]
  PIN o[113]
    DIRECTION OUTPUT ;
    USE SIGNAL ;
    PORT
      LAYER M4 ;
        RECT  12.876 56.4 12.96 56.424 ;
    END
  END o[113]
  PIN o[114]
    DIRECTION OUTPUT ;
    USE SIGNAL ;
    PORT
      LAYER M4 ;
        RECT  12.876 56.88 12.96 56.904 ;
    END
  END o[114]
  PIN o[115]
    DIRECTION OUTPUT ;
    USE SIGNAL ;
    PORT
      LAYER M4 ;
        RECT  12.876 57.36 12.96 57.384 ;
    END
  END o[115]
  PIN o[116]
    DIRECTION OUTPUT ;
    USE SIGNAL ;
    PORT
      LAYER M4 ;
        RECT  12.876 57.84 12.96 57.864 ;
    END
  END o[116]
  PIN o[117]
    DIRECTION OUTPUT ;
    USE SIGNAL ;
    PORT
      LAYER M4 ;
        RECT  12.876 58.32 12.96 58.344 ;
    END
  END o[117]
  PIN o[118]
    DIRECTION OUTPUT ;
    USE SIGNAL ;
    PORT
      LAYER M4 ;
        RECT  12.876 58.8 12.96 58.824 ;
    END
  END o[118]
  PIN o[119]
    DIRECTION OUTPUT ;
    USE SIGNAL ;
    PORT
      LAYER M4 ;
        RECT  12.876 59.28 12.96 59.304 ;
    END
  END o[119]
  PIN o[11]
    DIRECTION OUTPUT ;
    USE SIGNAL ;
    PORT
      LAYER M4 ;
        RECT  12.876 7.488 12.96 7.512 ;
    END
  END o[11]
  PIN o[120]
    DIRECTION OUTPUT ;
    USE SIGNAL ;
    PORT
      LAYER M4 ;
        RECT  12.876 59.76 12.96 59.784 ;
    END
  END o[120]
  PIN o[121]
    DIRECTION OUTPUT ;
    USE SIGNAL ;
    PORT
      LAYER M4 ;
        RECT  12.876 60.24 12.96 60.264 ;
    END
  END o[121]
  PIN o[122]
    DIRECTION OUTPUT ;
    USE SIGNAL ;
    PORT
      LAYER M4 ;
        RECT  12.876 60.72 12.96 60.744 ;
    END
  END o[122]
  PIN o[123]
    DIRECTION OUTPUT ;
    USE SIGNAL ;
    PORT
      LAYER M4 ;
        RECT  12.876 61.2 12.96 61.224 ;
    END
  END o[123]
  PIN o[124]
    DIRECTION OUTPUT ;
    USE SIGNAL ;
    PORT
      LAYER M4 ;
        RECT  12.876 61.68 12.96 61.704 ;
    END
  END o[124]
  PIN o[125]
    DIRECTION OUTPUT ;
    USE SIGNAL ;
    PORT
      LAYER M4 ;
        RECT  12.876 62.112 12.96 62.136 ;
    END
  END o[125]
  PIN o[126]
    DIRECTION OUTPUT ;
    USE SIGNAL ;
    PORT
      LAYER M4 ;
        RECT  12.876 62.592 12.96 62.616 ;
    END
  END o[126]
  PIN o[127]
    DIRECTION OUTPUT ;
    USE SIGNAL ;
    PORT
      LAYER M4 ;
        RECT  12.876 63.072 12.96 63.096 ;
    END
  END o[127]
  PIN o[128]
    DIRECTION OUTPUT ;
    USE SIGNAL ;
    PORT
      LAYER M4 ;
        RECT  12.876 63.552 12.96 63.576 ;
    END
  END o[128]
  PIN o[129]
    DIRECTION OUTPUT ;
    USE SIGNAL ;
    PORT
      LAYER M4 ;
        RECT  12.876 64.032 12.96 64.056 ;
    END
  END o[129]
  PIN o[12]
    DIRECTION OUTPUT ;
    USE SIGNAL ;
    PORT
      LAYER M4 ;
        RECT  12.876 7.968 12.96 7.992 ;
    END
  END o[12]
  PIN o[130]
    DIRECTION OUTPUT ;
    USE SIGNAL ;
    PORT
      LAYER M4 ;
        RECT  12.876 64.512 12.96 64.536 ;
    END
  END o[130]
  PIN o[131]
    DIRECTION OUTPUT ;
    USE SIGNAL ;
    PORT
      LAYER M4 ;
        RECT  12.876 64.992 12.96 65.016 ;
    END
  END o[131]
  PIN o[132]
    DIRECTION OUTPUT ;
    USE SIGNAL ;
    PORT
      LAYER M4 ;
        RECT  12.876 65.472 12.96 65.496 ;
    END
  END o[132]
  PIN o[133]
    DIRECTION OUTPUT ;
    USE SIGNAL ;
    PORT
      LAYER M4 ;
        RECT  12.876 65.952 12.96 65.976 ;
    END
  END o[133]
  PIN o[134]
    DIRECTION OUTPUT ;
    USE SIGNAL ;
    PORT
      LAYER M4 ;
        RECT  12.876 66.432 12.96 66.456 ;
    END
  END o[134]
  PIN o[135]
    DIRECTION OUTPUT ;
    USE SIGNAL ;
    PORT
      LAYER M4 ;
        RECT  12.876 66.912 12.96 66.936 ;
    END
  END o[135]
  PIN o[136]
    DIRECTION OUTPUT ;
    USE SIGNAL ;
    PORT
      LAYER M4 ;
        RECT  12.876 67.392 12.96 67.416 ;
    END
  END o[136]
  PIN o[137]
    DIRECTION OUTPUT ;
    USE SIGNAL ;
    PORT
      LAYER M4 ;
        RECT  12.876 67.872 12.96 67.896 ;
    END
  END o[137]
  PIN o[138]
    DIRECTION OUTPUT ;
    USE SIGNAL ;
    PORT
      LAYER M4 ;
        RECT  12.876 68.352 12.96 68.376 ;
    END
  END o[138]
  PIN o[139]
    DIRECTION OUTPUT ;
    USE SIGNAL ;
    PORT
      LAYER M4 ;
        RECT  12.876 68.832 12.96 68.856 ;
    END
  END o[139]
  PIN o[13]
    DIRECTION OUTPUT ;
    USE SIGNAL ;
    PORT
      LAYER M4 ;
        RECT  12.876 8.448 12.96 8.472 ;
    END
  END o[13]
  PIN o[140]
    DIRECTION OUTPUT ;
    USE SIGNAL ;
    PORT
      LAYER M4 ;
        RECT  12.876 69.312 12.96 69.336 ;
    END
  END o[140]
  PIN o[141]
    DIRECTION OUTPUT ;
    USE SIGNAL ;
    PORT
      LAYER M4 ;
        RECT  12.876 69.792 12.96 69.816 ;
    END
  END o[141]
  PIN o[142]
    DIRECTION OUTPUT ;
    USE SIGNAL ;
    PORT
      LAYER M4 ;
        RECT  12.876 70.272 12.96 70.296 ;
    END
  END o[142]
  PIN o[143]
    DIRECTION OUTPUT ;
    USE SIGNAL ;
    PORT
      LAYER M4 ;
        RECT  12.876 70.752 12.96 70.776 ;
    END
  END o[143]
  PIN o[144]
    DIRECTION OUTPUT ;
    USE SIGNAL ;
    PORT
      LAYER M4 ;
        RECT  12.876 71.232 12.96 71.256 ;
    END
  END o[144]
  PIN o[145]
    DIRECTION OUTPUT ;
    USE SIGNAL ;
    PORT
      LAYER M4 ;
        RECT  12.876 71.712 12.96 71.736 ;
    END
  END o[145]
  PIN o[146]
    DIRECTION OUTPUT ;
    USE SIGNAL ;
    PORT
      LAYER M4 ;
        RECT  12.876 72.192 12.96 72.216 ;
    END
  END o[146]
  PIN o[147]
    DIRECTION OUTPUT ;
    USE SIGNAL ;
    PORT
      LAYER M4 ;
        RECT  12.876 72.672 12.96 72.696 ;
    END
  END o[147]
  PIN o[148]
    DIRECTION OUTPUT ;
    USE SIGNAL ;
    PORT
      LAYER M4 ;
        RECT  12.876 73.152 12.96 73.176 ;
    END
  END o[148]
  PIN o[149]
    DIRECTION OUTPUT ;
    USE SIGNAL ;
    PORT
      LAYER M4 ;
        RECT  12.876 73.632 12.96 73.656 ;
    END
  END o[149]
  PIN o[14]
    DIRECTION OUTPUT ;
    USE SIGNAL ;
    PORT
      LAYER M4 ;
        RECT  12.876 8.928 12.96 8.952 ;
    END
  END o[14]
  PIN o[150]
    DIRECTION OUTPUT ;
    USE SIGNAL ;
    PORT
      LAYER M4 ;
        RECT  12.876 74.112 12.96 74.136 ;
    END
  END o[150]
  PIN o[151]
    DIRECTION OUTPUT ;
    USE SIGNAL ;
    PORT
      LAYER M4 ;
        RECT  12.876 74.592 12.96 74.616 ;
    END
  END o[151]
  PIN o[152]
    DIRECTION OUTPUT ;
    USE SIGNAL ;
    PORT
      LAYER M4 ;
        RECT  12.876 75.072 12.96 75.096 ;
    END
  END o[152]
  PIN o[153]
    DIRECTION OUTPUT ;
    USE SIGNAL ;
    PORT
      LAYER M4 ;
        RECT  12.876 75.552 12.96 75.576 ;
    END
  END o[153]
  PIN o[154]
    DIRECTION OUTPUT ;
    USE SIGNAL ;
    PORT
      LAYER M4 ;
        RECT  12.876 76.032 12.96 76.056 ;
    END
  END o[154]
  PIN o[155]
    DIRECTION OUTPUT ;
    USE SIGNAL ;
    PORT
      LAYER M4 ;
        RECT  12.876 76.512 12.96 76.536 ;
    END
  END o[155]
  PIN o[156]
    DIRECTION OUTPUT ;
    USE SIGNAL ;
    PORT
      LAYER M4 ;
        RECT  12.876 76.992 12.96 77.016 ;
    END
  END o[156]
  PIN o[157]
    DIRECTION OUTPUT ;
    USE SIGNAL ;
    PORT
      LAYER M4 ;
        RECT  12.876 77.472 12.96 77.496 ;
    END
  END o[157]
  PIN o[158]
    DIRECTION OUTPUT ;
    USE SIGNAL ;
    PORT
      LAYER M4 ;
        RECT  12.876 77.952 12.96 77.976 ;
    END
  END o[158]
  PIN o[159]
    DIRECTION OUTPUT ;
    USE SIGNAL ;
    PORT
      LAYER M4 ;
        RECT  12.876 78.432 12.96 78.456 ;
    END
  END o[159]
  PIN o[15]
    DIRECTION OUTPUT ;
    USE SIGNAL ;
    PORT
      LAYER M4 ;
        RECT  12.876 9.408 12.96 9.432 ;
    END
  END o[15]
  PIN o[160]
    DIRECTION OUTPUT ;
    USE SIGNAL ;
    PORT
      LAYER M4 ;
        RECT  12.876 78.912 12.96 78.936 ;
    END
  END o[160]
  PIN o[161]
    DIRECTION OUTPUT ;
    USE SIGNAL ;
    PORT
      LAYER M4 ;
        RECT  12.876 79.392 12.96 79.416 ;
    END
  END o[161]
  PIN o[162]
    DIRECTION OUTPUT ;
    USE SIGNAL ;
    PORT
      LAYER M4 ;
        RECT  12.876 79.872 12.96 79.896 ;
    END
  END o[162]
  PIN o[163]
    DIRECTION OUTPUT ;
    USE SIGNAL ;
    PORT
      LAYER M4 ;
        RECT  12.876 80.352 12.96 80.376 ;
    END
  END o[163]
  PIN o[164]
    DIRECTION OUTPUT ;
    USE SIGNAL ;
    PORT
      LAYER M4 ;
        RECT  12.876 80.832 12.96 80.856 ;
    END
  END o[164]
  PIN o[165]
    DIRECTION OUTPUT ;
    USE SIGNAL ;
    PORT
      LAYER M4 ;
        RECT  12.876 81.312 12.96 81.336 ;
    END
  END o[165]
  PIN o[166]
    DIRECTION OUTPUT ;
    USE SIGNAL ;
    PORT
      LAYER M4 ;
        RECT  12.876 81.792 12.96 81.816 ;
    END
  END o[166]
  PIN o[167]
    DIRECTION OUTPUT ;
    USE SIGNAL ;
    PORT
      LAYER M4 ;
        RECT  12.876 82.272 12.96 82.296 ;
    END
  END o[167]
  PIN o[168]
    DIRECTION OUTPUT ;
    USE SIGNAL ;
    PORT
      LAYER M4 ;
        RECT  12.876 82.752 12.96 82.776 ;
    END
  END o[168]
  PIN o[169]
    DIRECTION OUTPUT ;
    USE SIGNAL ;
    PORT
      LAYER M4 ;
        RECT  12.876 83.232 12.96 83.256 ;
    END
  END o[169]
  PIN o[16]
    DIRECTION OUTPUT ;
    USE SIGNAL ;
    PORT
      LAYER M4 ;
        RECT  12.876 9.888 12.96 9.912 ;
    END
  END o[16]
  PIN o[170]
    DIRECTION OUTPUT ;
    USE SIGNAL ;
    PORT
      LAYER M4 ;
        RECT  12.876 83.712 12.96 83.736 ;
    END
  END o[170]
  PIN o[171]
    DIRECTION OUTPUT ;
    USE SIGNAL ;
    PORT
      LAYER M4 ;
        RECT  12.876 84.192 12.96 84.216 ;
    END
  END o[171]
  PIN o[172]
    DIRECTION OUTPUT ;
    USE SIGNAL ;
    PORT
      LAYER M4 ;
        RECT  12.876 84.672 12.96 84.696 ;
    END
  END o[172]
  PIN o[173]
    DIRECTION OUTPUT ;
    USE SIGNAL ;
    PORT
      LAYER M4 ;
        RECT  12.876 85.152 12.96 85.176 ;
    END
  END o[173]
  PIN o[174]
    DIRECTION OUTPUT ;
    USE SIGNAL ;
    PORT
      LAYER M4 ;
        RECT  12.876 85.632 12.96 85.656 ;
    END
  END o[174]
  PIN o[175]
    DIRECTION OUTPUT ;
    USE SIGNAL ;
    PORT
      LAYER M4 ;
        RECT  12.876 86.112 12.96 86.136 ;
    END
  END o[175]
  PIN o[176]
    DIRECTION OUTPUT ;
    USE SIGNAL ;
    PORT
      LAYER M4 ;
        RECT  12.876 86.592 12.96 86.616 ;
    END
  END o[176]
  PIN o[177]
    DIRECTION OUTPUT ;
    USE SIGNAL ;
    PORT
      LAYER M4 ;
        RECT  12.876 87.072 12.96 87.096 ;
    END
  END o[177]
  PIN o[178]
    DIRECTION OUTPUT ;
    USE SIGNAL ;
    PORT
      LAYER M4 ;
        RECT  12.876 87.552 12.96 87.576 ;
    END
  END o[178]
  PIN o[179]
    DIRECTION OUTPUT ;
    USE SIGNAL ;
    PORT
      LAYER M4 ;
        RECT  12.876 88.032 12.96 88.056 ;
    END
  END o[179]
  PIN o[17]
    DIRECTION OUTPUT ;
    USE SIGNAL ;
    PORT
      LAYER M4 ;
        RECT  12.876 10.368 12.96 10.392 ;
    END
  END o[17]
  PIN o[180]
    DIRECTION OUTPUT ;
    USE SIGNAL ;
    PORT
      LAYER M4 ;
        RECT  12.876 88.512 12.96 88.536 ;
    END
  END o[180]
  PIN o[181]
    DIRECTION OUTPUT ;
    USE SIGNAL ;
    PORT
      LAYER M4 ;
        RECT  12.876 88.992 12.96 89.016 ;
    END
  END o[181]
  PIN o[182]
    DIRECTION OUTPUT ;
    USE SIGNAL ;
    PORT
      LAYER M4 ;
        RECT  12.876 89.472 12.96 89.496 ;
    END
  END o[182]
  PIN o[183]
    DIRECTION OUTPUT ;
    USE SIGNAL ;
    PORT
      LAYER M4 ;
        RECT  12.876 89.952 12.96 89.976 ;
    END
  END o[183]
  PIN o[184]
    DIRECTION OUTPUT ;
    USE SIGNAL ;
    PORT
      LAYER M4 ;
        RECT  12.876 90.432 12.96 90.456 ;
    END
  END o[184]
  PIN o[185]
    DIRECTION OUTPUT ;
    USE SIGNAL ;
    PORT
      LAYER M4 ;
        RECT  12.876 90.912 12.96 90.936 ;
    END
  END o[185]
  PIN o[186]
    DIRECTION OUTPUT ;
    USE SIGNAL ;
    PORT
      LAYER M4 ;
        RECT  12.876 91.392 12.96 91.416 ;
    END
  END o[186]
  PIN o[187]
    DIRECTION OUTPUT ;
    USE SIGNAL ;
    PORT
      LAYER M4 ;
        RECT  12.876 91.872 12.96 91.896 ;
    END
  END o[187]
  PIN o[188]
    DIRECTION OUTPUT ;
    USE SIGNAL ;
    PORT
      LAYER M4 ;
        RECT  12.876 92.352 12.96 92.376 ;
    END
  END o[188]
  PIN o[189]
    DIRECTION OUTPUT ;
    USE SIGNAL ;
    PORT
      LAYER M4 ;
        RECT  12.876 92.832 12.96 92.856 ;
    END
  END o[189]
  PIN o[18]
    DIRECTION OUTPUT ;
    USE SIGNAL ;
    PORT
      LAYER M4 ;
        RECT  12.876 10.848 12.96 10.872 ;
    END
  END o[18]
  PIN o[190]
    DIRECTION OUTPUT ;
    USE SIGNAL ;
    PORT
      LAYER M4 ;
        RECT  12.876 93.312 12.96 93.336 ;
    END
  END o[190]
  PIN o[191]
    DIRECTION OUTPUT ;
    USE SIGNAL ;
    PORT
      LAYER M4 ;
        RECT  12.876 93.744 12.96 93.768 ;
    END
  END o[191]
  PIN o[192]
    DIRECTION OUTPUT ;
    USE SIGNAL ;
    PORT
      LAYER M4 ;
        RECT  12.876 94.224 12.96 94.248 ;
    END
  END o[192]
  PIN o[193]
    DIRECTION OUTPUT ;
    USE SIGNAL ;
    PORT
      LAYER M4 ;
        RECT  12.876 94.704 12.96 94.728 ;
    END
  END o[193]
  PIN o[194]
    DIRECTION OUTPUT ;
    USE SIGNAL ;
    PORT
      LAYER M4 ;
        RECT  12.876 95.184 12.96 95.208 ;
    END
  END o[194]
  PIN o[195]
    DIRECTION OUTPUT ;
    USE SIGNAL ;
    PORT
      LAYER M4 ;
        RECT  12.876 95.664 12.96 95.688 ;
    END
  END o[195]
  PIN o[196]
    DIRECTION OUTPUT ;
    USE SIGNAL ;
    PORT
      LAYER M4 ;
        RECT  12.876 96.144 12.96 96.168 ;
    END
  END o[196]
  PIN o[197]
    DIRECTION OUTPUT ;
    USE SIGNAL ;
    PORT
      LAYER M4 ;
        RECT  12.876 96.624 12.96 96.648 ;
    END
  END o[197]
  PIN o[198]
    DIRECTION OUTPUT ;
    USE SIGNAL ;
    PORT
      LAYER M4 ;
        RECT  12.876 97.104 12.96 97.128 ;
    END
  END o[198]
  PIN o[199]
    DIRECTION OUTPUT ;
    USE SIGNAL ;
    PORT
      LAYER M4 ;
        RECT  12.876 97.584 12.96 97.608 ;
    END
  END o[199]
  PIN o[19]
    DIRECTION OUTPUT ;
    USE SIGNAL ;
    PORT
      LAYER M4 ;
        RECT  12.876 11.328 12.96 11.352 ;
    END
  END o[19]
  PIN o[1]
    DIRECTION OUTPUT ;
    USE SIGNAL ;
    PORT
      LAYER M4 ;
        RECT  12.876 2.688 12.96 2.712 ;
    END
  END o[1]
  PIN o[200]
    DIRECTION OUTPUT ;
    USE SIGNAL ;
    PORT
      LAYER M4 ;
        RECT  12.876 98.064 12.96 98.088 ;
    END
  END o[200]
  PIN o[201]
    DIRECTION OUTPUT ;
    USE SIGNAL ;
    PORT
      LAYER M4 ;
        RECT  12.876 98.544 12.96 98.568 ;
    END
  END o[201]
  PIN o[202]
    DIRECTION OUTPUT ;
    USE SIGNAL ;
    PORT
      LAYER M4 ;
        RECT  12.876 99.024 12.96 99.048 ;
    END
  END o[202]
  PIN o[203]
    DIRECTION OUTPUT ;
    USE SIGNAL ;
    PORT
      LAYER M4 ;
        RECT  12.876 99.504 12.96 99.528 ;
    END
  END o[203]
  PIN o[204]
    DIRECTION OUTPUT ;
    USE SIGNAL ;
    PORT
      LAYER M4 ;
        RECT  12.876 99.984 12.96 100.008 ;
    END
  END o[204]
  PIN o[205]
    DIRECTION OUTPUT ;
    USE SIGNAL ;
    PORT
      LAYER M4 ;
        RECT  12.876 100.464 12.96 100.488 ;
    END
  END o[205]
  PIN o[206]
    DIRECTION OUTPUT ;
    USE SIGNAL ;
    PORT
      LAYER M4 ;
        RECT  12.876 100.944 12.96 100.968 ;
    END
  END o[206]
  PIN o[207]
    DIRECTION OUTPUT ;
    USE SIGNAL ;
    PORT
      LAYER M4 ;
        RECT  12.876 101.424 12.96 101.448 ;
    END
  END o[207]
  PIN o[208]
    DIRECTION OUTPUT ;
    USE SIGNAL ;
    PORT
      LAYER M4 ;
        RECT  12.876 101.904 12.96 101.928 ;
    END
  END o[208]
  PIN o[209]
    DIRECTION OUTPUT ;
    USE SIGNAL ;
    PORT
      LAYER M4 ;
        RECT  12.876 102.384 12.96 102.408 ;
    END
  END o[209]
  PIN o[20]
    DIRECTION OUTPUT ;
    USE SIGNAL ;
    PORT
      LAYER M4 ;
        RECT  12.876 11.808 12.96 11.832 ;
    END
  END o[20]
  PIN o[210]
    DIRECTION OUTPUT ;
    USE SIGNAL ;
    PORT
      LAYER M4 ;
        RECT  12.876 102.864 12.96 102.888 ;
    END
  END o[210]
  PIN o[211]
    DIRECTION OUTPUT ;
    USE SIGNAL ;
    PORT
      LAYER M4 ;
        RECT  12.876 103.344 12.96 103.368 ;
    END
  END o[211]
  PIN o[212]
    DIRECTION OUTPUT ;
    USE SIGNAL ;
    PORT
      LAYER M4 ;
        RECT  12.876 103.824 12.96 103.848 ;
    END
  END o[212]
  PIN o[213]
    DIRECTION OUTPUT ;
    USE SIGNAL ;
    PORT
      LAYER M4 ;
        RECT  12.876 104.304 12.96 104.328 ;
    END
  END o[213]
  PIN o[214]
    DIRECTION OUTPUT ;
    USE SIGNAL ;
    PORT
      LAYER M4 ;
        RECT  12.876 104.784 12.96 104.808 ;
    END
  END o[214]
  PIN o[215]
    DIRECTION OUTPUT ;
    USE SIGNAL ;
    PORT
      LAYER M4 ;
        RECT  12.876 105.264 12.96 105.288 ;
    END
  END o[215]
  PIN o[216]
    DIRECTION OUTPUT ;
    USE SIGNAL ;
    PORT
      LAYER M4 ;
        RECT  12.876 105.744 12.96 105.768 ;
    END
  END o[216]
  PIN o[21]
    DIRECTION OUTPUT ;
    USE SIGNAL ;
    PORT
      LAYER M4 ;
        RECT  12.876 12.288 12.96 12.312 ;
    END
  END o[21]
  PIN o[22]
    DIRECTION OUTPUT ;
    USE SIGNAL ;
    PORT
      LAYER M4 ;
        RECT  12.876 12.768 12.96 12.792 ;
    END
  END o[22]
  PIN o[23]
    DIRECTION OUTPUT ;
    USE SIGNAL ;
    PORT
      LAYER M4 ;
        RECT  12.876 13.248 12.96 13.272 ;
    END
  END o[23]
  PIN o[24]
    DIRECTION OUTPUT ;
    USE SIGNAL ;
    PORT
      LAYER M4 ;
        RECT  12.876 13.728 12.96 13.752 ;
    END
  END o[24]
  PIN o[25]
    DIRECTION OUTPUT ;
    USE SIGNAL ;
    PORT
      LAYER M4 ;
        RECT  12.876 14.208 12.96 14.232 ;
    END
  END o[25]
  PIN o[26]
    DIRECTION OUTPUT ;
    USE SIGNAL ;
    PORT
      LAYER M4 ;
        RECT  12.876 14.688 12.96 14.712 ;
    END
  END o[26]
  PIN o[27]
    DIRECTION OUTPUT ;
    USE SIGNAL ;
    PORT
      LAYER M4 ;
        RECT  12.876 15.168 12.96 15.192 ;
    END
  END o[27]
  PIN o[28]
    DIRECTION OUTPUT ;
    USE SIGNAL ;
    PORT
      LAYER M4 ;
        RECT  12.876 15.648 12.96 15.672 ;
    END
  END o[28]
  PIN o[29]
    DIRECTION OUTPUT ;
    USE SIGNAL ;
    PORT
      LAYER M4 ;
        RECT  12.876 16.128 12.96 16.152 ;
    END
  END o[29]
  PIN o[2]
    DIRECTION OUTPUT ;
    USE SIGNAL ;
    PORT
      LAYER M4 ;
        RECT  12.876 3.168 12.96 3.192 ;
    END
  END o[2]
  PIN o[30]
    DIRECTION OUTPUT ;
    USE SIGNAL ;
    PORT
      LAYER M4 ;
        RECT  12.876 16.608 12.96 16.632 ;
    END
  END o[30]
  PIN o[31]
    DIRECTION OUTPUT ;
    USE SIGNAL ;
    PORT
      LAYER M4 ;
        RECT  12.876 17.088 12.96 17.112 ;
    END
  END o[31]
  PIN o[32]
    DIRECTION OUTPUT ;
    USE SIGNAL ;
    PORT
      LAYER M4 ;
        RECT  12.876 17.568 12.96 17.592 ;
    END
  END o[32]
  PIN o[33]
    DIRECTION OUTPUT ;
    USE SIGNAL ;
    PORT
      LAYER M4 ;
        RECT  12.876 18.048 12.96 18.072 ;
    END
  END o[33]
  PIN o[34]
    DIRECTION OUTPUT ;
    USE SIGNAL ;
    PORT
      LAYER M4 ;
        RECT  12.876 18.528 12.96 18.552 ;
    END
  END o[34]
  PIN o[35]
    DIRECTION OUTPUT ;
    USE SIGNAL ;
    PORT
      LAYER M4 ;
        RECT  12.876 19.008 12.96 19.032 ;
    END
  END o[35]
  PIN o[36]
    DIRECTION OUTPUT ;
    USE SIGNAL ;
    PORT
      LAYER M4 ;
        RECT  12.876 19.488 12.96 19.512 ;
    END
  END o[36]
  PIN o[37]
    DIRECTION OUTPUT ;
    USE SIGNAL ;
    PORT
      LAYER M4 ;
        RECT  12.876 19.968 12.96 19.992 ;
    END
  END o[37]
  PIN o[38]
    DIRECTION OUTPUT ;
    USE SIGNAL ;
    PORT
      LAYER M4 ;
        RECT  12.876 20.448 12.96 20.472 ;
    END
  END o[38]
  PIN o[39]
    DIRECTION OUTPUT ;
    USE SIGNAL ;
    PORT
      LAYER M4 ;
        RECT  12.876 20.928 12.96 20.952 ;
    END
  END o[39]
  PIN o[3]
    DIRECTION OUTPUT ;
    USE SIGNAL ;
    PORT
      LAYER M4 ;
        RECT  12.876 3.648 12.96 3.672 ;
    END
  END o[3]
  PIN o[40]
    DIRECTION OUTPUT ;
    USE SIGNAL ;
    PORT
      LAYER M4 ;
        RECT  12.876 21.408 12.96 21.432 ;
    END
  END o[40]
  PIN o[41]
    DIRECTION OUTPUT ;
    USE SIGNAL ;
    PORT
      LAYER M4 ;
        RECT  12.876 21.888 12.96 21.912 ;
    END
  END o[41]
  PIN o[42]
    DIRECTION OUTPUT ;
    USE SIGNAL ;
    PORT
      LAYER M4 ;
        RECT  12.876 22.368 12.96 22.392 ;
    END
  END o[42]
  PIN o[43]
    DIRECTION OUTPUT ;
    USE SIGNAL ;
    PORT
      LAYER M4 ;
        RECT  12.876 22.848 12.96 22.872 ;
    END
  END o[43]
  PIN o[44]
    DIRECTION OUTPUT ;
    USE SIGNAL ;
    PORT
      LAYER M4 ;
        RECT  12.876 23.328 12.96 23.352 ;
    END
  END o[44]
  PIN o[45]
    DIRECTION OUTPUT ;
    USE SIGNAL ;
    PORT
      LAYER M4 ;
        RECT  12.876 23.808 12.96 23.832 ;
    END
  END o[45]
  PIN o[46]
    DIRECTION OUTPUT ;
    USE SIGNAL ;
    PORT
      LAYER M4 ;
        RECT  12.876 24.288 12.96 24.312 ;
    END
  END o[46]
  PIN o[47]
    DIRECTION OUTPUT ;
    USE SIGNAL ;
    PORT
      LAYER M4 ;
        RECT  12.876 24.768 12.96 24.792 ;
    END
  END o[47]
  PIN o[48]
    DIRECTION OUTPUT ;
    USE SIGNAL ;
    PORT
      LAYER M4 ;
        RECT  12.876 25.248 12.96 25.272 ;
    END
  END o[48]
  PIN o[49]
    DIRECTION OUTPUT ;
    USE SIGNAL ;
    PORT
      LAYER M4 ;
        RECT  12.876 25.728 12.96 25.752 ;
    END
  END o[49]
  PIN o[4]
    DIRECTION OUTPUT ;
    USE SIGNAL ;
    PORT
      LAYER M4 ;
        RECT  12.876 4.128 12.96 4.152 ;
    END
  END o[4]
  PIN o[50]
    DIRECTION OUTPUT ;
    USE SIGNAL ;
    PORT
      LAYER M4 ;
        RECT  12.876 26.208 12.96 26.232 ;
    END
  END o[50]
  PIN o[51]
    DIRECTION OUTPUT ;
    USE SIGNAL ;
    PORT
      LAYER M4 ;
        RECT  12.876 26.688 12.96 26.712 ;
    END
  END o[51]
  PIN o[52]
    DIRECTION OUTPUT ;
    USE SIGNAL ;
    PORT
      LAYER M4 ;
        RECT  12.876 27.168 12.96 27.192 ;
    END
  END o[52]
  PIN o[53]
    DIRECTION OUTPUT ;
    USE SIGNAL ;
    PORT
      LAYER M4 ;
        RECT  12.876 27.648 12.96 27.672 ;
    END
  END o[53]
  PIN o[54]
    DIRECTION OUTPUT ;
    USE SIGNAL ;
    PORT
      LAYER M4 ;
        RECT  12.876 28.128 12.96 28.152 ;
    END
  END o[54]
  PIN o[55]
    DIRECTION OUTPUT ;
    USE SIGNAL ;
    PORT
      LAYER M4 ;
        RECT  12.876 28.608 12.96 28.632 ;
    END
  END o[55]
  PIN o[56]
    DIRECTION OUTPUT ;
    USE SIGNAL ;
    PORT
      LAYER M4 ;
        RECT  12.876 29.088 12.96 29.112 ;
    END
  END o[56]
  PIN o[57]
    DIRECTION OUTPUT ;
    USE SIGNAL ;
    PORT
      LAYER M4 ;
        RECT  12.876 29.568 12.96 29.592 ;
    END
  END o[57]
  PIN o[58]
    DIRECTION OUTPUT ;
    USE SIGNAL ;
    PORT
      LAYER M4 ;
        RECT  12.876 30.048 12.96 30.072 ;
    END
  END o[58]
  PIN o[59]
    DIRECTION OUTPUT ;
    USE SIGNAL ;
    PORT
      LAYER M4 ;
        RECT  12.876 30.528 12.96 30.552 ;
    END
  END o[59]
  PIN o[5]
    DIRECTION OUTPUT ;
    USE SIGNAL ;
    PORT
      LAYER M4 ;
        RECT  12.876 4.608 12.96 4.632 ;
    END
  END o[5]
  PIN o[60]
    DIRECTION OUTPUT ;
    USE SIGNAL ;
    PORT
      LAYER M4 ;
        RECT  12.876 30.96 12.96 30.984 ;
    END
  END o[60]
  PIN o[61]
    DIRECTION OUTPUT ;
    USE SIGNAL ;
    PORT
      LAYER M4 ;
        RECT  12.876 31.44 12.96 31.464 ;
    END
  END o[61]
  PIN o[62]
    DIRECTION OUTPUT ;
    USE SIGNAL ;
    PORT
      LAYER M4 ;
        RECT  12.876 31.92 12.96 31.944 ;
    END
  END o[62]
  PIN o[63]
    DIRECTION OUTPUT ;
    USE SIGNAL ;
    PORT
      LAYER M4 ;
        RECT  12.876 32.4 12.96 32.424 ;
    END
  END o[63]
  PIN o[64]
    DIRECTION OUTPUT ;
    USE SIGNAL ;
    PORT
      LAYER M4 ;
        RECT  12.876 32.88 12.96 32.904 ;
    END
  END o[64]
  PIN o[65]
    DIRECTION OUTPUT ;
    USE SIGNAL ;
    PORT
      LAYER M4 ;
        RECT  12.876 33.36 12.96 33.384 ;
    END
  END o[65]
  PIN o[66]
    DIRECTION OUTPUT ;
    USE SIGNAL ;
    PORT
      LAYER M4 ;
        RECT  12.876 33.84 12.96 33.864 ;
    END
  END o[66]
  PIN o[67]
    DIRECTION OUTPUT ;
    USE SIGNAL ;
    PORT
      LAYER M4 ;
        RECT  12.876 34.32 12.96 34.344 ;
    END
  END o[67]
  PIN o[68]
    DIRECTION OUTPUT ;
    USE SIGNAL ;
    PORT
      LAYER M4 ;
        RECT  12.876 34.8 12.96 34.824 ;
    END
  END o[68]
  PIN o[69]
    DIRECTION OUTPUT ;
    USE SIGNAL ;
    PORT
      LAYER M4 ;
        RECT  12.876 35.28 12.96 35.304 ;
    END
  END o[69]
  PIN o[6]
    DIRECTION OUTPUT ;
    USE SIGNAL ;
    PORT
      LAYER M4 ;
        RECT  12.876 5.088 12.96 5.112 ;
    END
  END o[6]
  PIN o[70]
    DIRECTION OUTPUT ;
    USE SIGNAL ;
    PORT
      LAYER M4 ;
        RECT  12.876 35.76 12.96 35.784 ;
    END
  END o[70]
  PIN o[71]
    DIRECTION OUTPUT ;
    USE SIGNAL ;
    PORT
      LAYER M4 ;
        RECT  12.876 36.24 12.96 36.264 ;
    END
  END o[71]
  PIN o[72]
    DIRECTION OUTPUT ;
    USE SIGNAL ;
    PORT
      LAYER M4 ;
        RECT  12.876 36.72 12.96 36.744 ;
    END
  END o[72]
  PIN o[73]
    DIRECTION OUTPUT ;
    USE SIGNAL ;
    PORT
      LAYER M4 ;
        RECT  12.876 37.2 12.96 37.224 ;
    END
  END o[73]
  PIN o[74]
    DIRECTION OUTPUT ;
    USE SIGNAL ;
    PORT
      LAYER M4 ;
        RECT  12.876 37.68 12.96 37.704 ;
    END
  END o[74]
  PIN o[75]
    DIRECTION OUTPUT ;
    USE SIGNAL ;
    PORT
      LAYER M4 ;
        RECT  12.876 38.16 12.96 38.184 ;
    END
  END o[75]
  PIN o[76]
    DIRECTION OUTPUT ;
    USE SIGNAL ;
    PORT
      LAYER M4 ;
        RECT  12.876 38.64 12.96 38.664 ;
    END
  END o[76]
  PIN o[77]
    DIRECTION OUTPUT ;
    USE SIGNAL ;
    PORT
      LAYER M4 ;
        RECT  12.876 39.12 12.96 39.144 ;
    END
  END o[77]
  PIN o[78]
    DIRECTION OUTPUT ;
    USE SIGNAL ;
    PORT
      LAYER M4 ;
        RECT  12.876 39.6 12.96 39.624 ;
    END
  END o[78]
  PIN o[79]
    DIRECTION OUTPUT ;
    USE SIGNAL ;
    PORT
      LAYER M4 ;
        RECT  12.876 40.08 12.96 40.104 ;
    END
  END o[79]
  PIN o[7]
    DIRECTION OUTPUT ;
    USE SIGNAL ;
    PORT
      LAYER M4 ;
        RECT  12.876 5.568 12.96 5.592 ;
    END
  END o[7]
  PIN o[80]
    DIRECTION OUTPUT ;
    USE SIGNAL ;
    PORT
      LAYER M4 ;
        RECT  12.876 40.56 12.96 40.584 ;
    END
  END o[80]
  PIN o[81]
    DIRECTION OUTPUT ;
    USE SIGNAL ;
    PORT
      LAYER M4 ;
        RECT  12.876 41.04 12.96 41.064 ;
    END
  END o[81]
  PIN o[82]
    DIRECTION OUTPUT ;
    USE SIGNAL ;
    PORT
      LAYER M4 ;
        RECT  12.876 41.52 12.96 41.544 ;
    END
  END o[82]
  PIN o[83]
    DIRECTION OUTPUT ;
    USE SIGNAL ;
    PORT
      LAYER M4 ;
        RECT  12.876 42 12.96 42.024 ;
    END
  END o[83]
  PIN o[84]
    DIRECTION OUTPUT ;
    USE SIGNAL ;
    PORT
      LAYER M4 ;
        RECT  12.876 42.48 12.96 42.504 ;
    END
  END o[84]
  PIN o[85]
    DIRECTION OUTPUT ;
    USE SIGNAL ;
    PORT
      LAYER M4 ;
        RECT  12.876 42.96 12.96 42.984 ;
    END
  END o[85]
  PIN o[86]
    DIRECTION OUTPUT ;
    USE SIGNAL ;
    PORT
      LAYER M4 ;
        RECT  12.876 43.44 12.96 43.464 ;
    END
  END o[86]
  PIN o[87]
    DIRECTION OUTPUT ;
    USE SIGNAL ;
    PORT
      LAYER M4 ;
        RECT  12.876 43.92 12.96 43.944 ;
    END
  END o[87]
  PIN o[88]
    DIRECTION OUTPUT ;
    USE SIGNAL ;
    PORT
      LAYER M4 ;
        RECT  12.876 44.4 12.96 44.424 ;
    END
  END o[88]
  PIN o[89]
    DIRECTION OUTPUT ;
    USE SIGNAL ;
    PORT
      LAYER M4 ;
        RECT  12.876 44.88 12.96 44.904 ;
    END
  END o[89]
  PIN o[8]
    DIRECTION OUTPUT ;
    USE SIGNAL ;
    PORT
      LAYER M4 ;
        RECT  12.876 6.048 12.96 6.072 ;
    END
  END o[8]
  PIN o[90]
    DIRECTION OUTPUT ;
    USE SIGNAL ;
    PORT
      LAYER M4 ;
        RECT  12.876 45.36 12.96 45.384 ;
    END
  END o[90]
  PIN o[91]
    DIRECTION OUTPUT ;
    USE SIGNAL ;
    PORT
      LAYER M4 ;
        RECT  12.876 45.84 12.96 45.864 ;
    END
  END o[91]
  PIN o[92]
    DIRECTION OUTPUT ;
    USE SIGNAL ;
    PORT
      LAYER M4 ;
        RECT  12.876 46.32 12.96 46.344 ;
    END
  END o[92]
  PIN o[93]
    DIRECTION OUTPUT ;
    USE SIGNAL ;
    PORT
      LAYER M4 ;
        RECT  12.876 46.8 12.96 46.824 ;
    END
  END o[93]
  PIN o[94]
    DIRECTION OUTPUT ;
    USE SIGNAL ;
    PORT
      LAYER M4 ;
        RECT  12.876 47.28 12.96 47.304 ;
    END
  END o[94]
  PIN o[95]
    DIRECTION OUTPUT ;
    USE SIGNAL ;
    PORT
      LAYER M4 ;
        RECT  12.876 47.76 12.96 47.784 ;
    END
  END o[95]
  PIN o[96]
    DIRECTION OUTPUT ;
    USE SIGNAL ;
    PORT
      LAYER M4 ;
        RECT  12.876 48.24 12.96 48.264 ;
    END
  END o[96]
  PIN o[97]
    DIRECTION OUTPUT ;
    USE SIGNAL ;
    PORT
      LAYER M4 ;
        RECT  12.876 48.72 12.96 48.744 ;
    END
  END o[97]
  PIN o[98]
    DIRECTION OUTPUT ;
    USE SIGNAL ;
    PORT
      LAYER M4 ;
        RECT  12.876 49.2 12.96 49.224 ;
    END
  END o[98]
  PIN o[99]
    DIRECTION OUTPUT ;
    USE SIGNAL ;
    PORT
      LAYER M4 ;
        RECT  12.876 49.68 12.96 49.704 ;
    END
  END o[99]
  PIN o[9]
    DIRECTION OUTPUT ;
    USE SIGNAL ;
    PORT
      LAYER M4 ;
        RECT  12.876 6.528 12.96 6.552 ;
    END
  END o[9]
  PIN VDD
    DIRECTION INOUT ;
    USE POWER ;
    PORT
      LAYER M5 ;
        RECT  10.692 2.151 10.812 105.849 ;
        RECT  7.992 2.151 8.112 105.849 ;
        RECT  5.292 2.151 5.412 105.849 ;
        RECT  2.592 2.151 2.712 105.849 ;
    END
  END VDD
  PIN VSS
    DIRECTION INOUT ;
    USE GROUND ;
    PORT
      LAYER M5 ;
        RECT  10.5 2.137 10.62 105.863 ;
        RECT  7.8 2.137 7.92 105.863 ;
        RECT  5.1 2.137 5.22 105.863 ;
        RECT  2.4 2.137 2.52 105.863 ;
    END
  END VSS
  OBS
    LAYER RVTN ;
     RECT  2.16 2.16 10.8 2.295 ;
     RECT  2.16 2.565 10.8 2.835 ;
     RECT  2.16 3.105 10.8 3.375 ;
     RECT  2.16 3.645 10.8 3.915 ;
     RECT  2.16 4.185 10.8 4.455 ;
     RECT  2.16 4.725 10.8 4.995 ;
     RECT  2.16 5.265 10.8 5.535 ;
     RECT  2.16 5.805 10.8 6.075 ;
     RECT  2.16 6.345 10.8 6.615 ;
     RECT  2.16 6.885 10.8 7.155 ;
     RECT  2.16 7.425 10.8 7.695 ;
     RECT  2.16 7.965 10.8 8.235 ;
     RECT  2.16 8.505 10.8 8.775 ;
     RECT  2.16 9.045 10.8 9.315 ;
     RECT  2.16 9.585 10.8 9.855 ;
     RECT  2.16 10.125 10.8 10.395 ;
     RECT  2.16 10.665 10.8 10.935 ;
     RECT  2.16 11.205 10.8 11.475 ;
     RECT  2.16 11.745 10.8 12.015 ;
     RECT  2.16 12.285 10.8 12.555 ;
     RECT  2.16 12.825 10.8 13.095 ;
     RECT  2.16 13.365 10.8 13.635 ;
     RECT  2.16 13.905 10.8 14.175 ;
     RECT  2.16 14.445 10.8 14.715 ;
     RECT  2.16 14.985 10.8 15.255 ;
     RECT  2.16 15.525 10.8 15.795 ;
     RECT  2.16 16.065 10.8 16.335 ;
     RECT  2.16 16.605 10.8 16.875 ;
     RECT  2.16 17.145 10.8 17.415 ;
     RECT  2.16 17.685 10.8 17.955 ;
     RECT  2.16 18.225 10.8 18.495 ;
     RECT  2.16 18.765 10.8 19.035 ;
     RECT  2.16 19.305 10.8 19.575 ;
     RECT  2.16 19.845 10.8 20.115 ;
     RECT  2.16 20.385 10.8 20.655 ;
     RECT  2.16 20.925 10.8 21.195 ;
     RECT  2.16 21.465 10.8 21.735 ;
     RECT  2.16 22.005 10.8 22.275 ;
     RECT  2.16 22.545 10.8 22.815 ;
     RECT  2.16 23.085 10.8 23.355 ;
     RECT  2.16 23.625 10.8 23.895 ;
     RECT  2.16 24.165 10.8 24.435 ;
     RECT  2.16 24.705 10.8 24.975 ;
     RECT  2.16 25.245 10.8 25.515 ;
     RECT  2.16 25.785 10.8 26.055 ;
     RECT  2.16 26.325 10.8 26.595 ;
     RECT  2.16 26.865 10.8 27.135 ;
     RECT  2.16 27.405 10.8 27.675 ;
     RECT  2.16 27.945 10.8 28.215 ;
     RECT  2.16 28.485 10.8 28.755 ;
     RECT  2.16 29.025 10.8 29.295 ;
     RECT  2.16 29.565 10.8 29.835 ;
     RECT  2.16 30.105 10.8 30.375 ;
     RECT  2.16 30.645 10.8 30.915 ;
     RECT  2.16 31.185 10.8 31.455 ;
     RECT  2.16 31.725 10.8 31.995 ;
     RECT  2.16 32.265 10.8 32.535 ;
     RECT  2.16 32.805 10.8 33.075 ;
     RECT  2.16 33.345 10.8 33.615 ;
     RECT  2.16 33.885 10.8 34.155 ;
     RECT  2.16 34.425 10.8 34.695 ;
     RECT  2.16 34.965 10.8 35.235 ;
     RECT  2.16 35.505 10.8 35.775 ;
     RECT  2.16 36.045 10.8 36.315 ;
     RECT  2.16 36.585 10.8 36.855 ;
     RECT  2.16 37.125 10.8 37.395 ;
     RECT  2.16 37.665 10.8 37.935 ;
     RECT  2.16 38.205 10.8 38.475 ;
     RECT  2.16 38.745 10.8 39.015 ;
     RECT  2.16 39.285 10.8 39.555 ;
     RECT  2.16 39.825 10.8 40.095 ;
     RECT  2.16 40.365 10.8 40.635 ;
     RECT  2.16 40.905 10.8 41.175 ;
     RECT  2.16 41.445 10.8 41.715 ;
     RECT  2.16 41.985 10.8 42.255 ;
     RECT  2.16 42.525 10.8 42.795 ;
     RECT  2.16 43.065 10.8 43.335 ;
     RECT  2.16 43.605 10.8 43.875 ;
     RECT  2.16 44.145 10.8 44.415 ;
     RECT  2.16 44.685 10.8 44.955 ;
     RECT  2.16 45.225 10.8 45.495 ;
     RECT  2.16 45.765 10.8 46.035 ;
     RECT  2.16 46.305 10.8 46.575 ;
     RECT  2.16 46.845 10.8 47.115 ;
     RECT  2.16 47.385 10.8 47.655 ;
     RECT  2.16 47.925 10.8 48.195 ;
     RECT  2.16 48.465 10.8 48.735 ;
     RECT  2.16 49.005 10.8 49.275 ;
     RECT  2.16 49.545 10.8 49.815 ;
     RECT  2.16 50.085 10.8 50.355 ;
     RECT  2.16 50.625 10.8 50.895 ;
     RECT  2.16 51.165 10.8 51.435 ;
     RECT  2.16 51.705 10.8 51.975 ;
     RECT  2.16 52.245 10.8 52.515 ;
     RECT  2.16 52.785 10.8 53.055 ;
     RECT  2.16 53.325 10.8 53.595 ;
     RECT  2.16 53.865 10.8 54.135 ;
     RECT  2.16 54.405 10.8 54.675 ;
     RECT  2.16 54.945 10.8 55.215 ;
     RECT  2.16 55.485 10.8 55.755 ;
     RECT  2.16 56.025 10.8 56.295 ;
     RECT  2.16 56.565 10.8 56.835 ;
     RECT  2.16 57.105 10.8 57.375 ;
     RECT  2.16 57.645 10.8 57.915 ;
     RECT  2.16 58.185 10.8 58.455 ;
     RECT  2.16 58.725 10.8 58.995 ;
     RECT  2.16 59.265 10.8 59.535 ;
     RECT  2.16 59.805 10.8 60.075 ;
     RECT  2.16 60.345 10.8 60.615 ;
     RECT  2.16 60.885 10.8 61.155 ;
     RECT  2.16 61.425 10.8 61.695 ;
     RECT  2.16 61.965 10.8 62.235 ;
     RECT  2.16 62.505 10.8 62.775 ;
     RECT  2.16 63.045 10.8 63.315 ;
     RECT  2.16 63.585 10.8 63.855 ;
     RECT  2.16 64.125 10.8 64.395 ;
     RECT  2.16 64.665 10.8 64.935 ;
     RECT  2.16 65.205 10.8 65.475 ;
     RECT  2.16 65.745 10.8 66.015 ;
     RECT  2.16 66.285 10.8 66.555 ;
     RECT  2.16 66.825 10.8 67.095 ;
     RECT  2.16 67.365 10.8 67.635 ;
     RECT  2.16 67.905 10.8 68.175 ;
     RECT  2.16 68.445 10.8 68.715 ;
     RECT  2.16 68.985 10.8 69.255 ;
     RECT  2.16 69.525 10.8 69.795 ;
     RECT  2.16 70.065 10.8 70.335 ;
     RECT  2.16 70.605 10.8 70.875 ;
     RECT  2.16 71.145 10.8 71.415 ;
     RECT  2.16 71.685 10.8 71.955 ;
     RECT  2.16 72.225 10.8 72.495 ;
     RECT  2.16 72.765 10.8 73.035 ;
     RECT  2.16 73.305 10.8 73.575 ;
     RECT  2.16 73.845 10.8 74.115 ;
     RECT  2.16 74.385 10.8 74.655 ;
     RECT  2.16 74.925 10.8 75.195 ;
     RECT  2.16 75.465 10.8 75.735 ;
     RECT  2.16 76.005 10.8 76.275 ;
     RECT  2.16 76.545 10.8 76.815 ;
     RECT  2.16 77.085 10.8 77.355 ;
     RECT  2.16 77.625 10.8 77.895 ;
     RECT  2.16 78.165 10.8 78.435 ;
     RECT  2.16 78.705 10.8 78.975 ;
     RECT  2.16 79.245 10.8 79.515 ;
     RECT  2.16 79.785 10.8 80.055 ;
     RECT  2.16 80.325 10.8 80.595 ;
     RECT  2.16 80.865 10.8 81.135 ;
     RECT  2.16 81.405 10.8 81.675 ;
     RECT  2.16 81.945 10.8 82.215 ;
     RECT  2.16 82.485 10.8 82.755 ;
     RECT  2.16 83.025 10.8 83.295 ;
     RECT  2.16 83.565 10.8 83.835 ;
     RECT  2.16 84.105 10.8 84.375 ;
     RECT  2.16 84.645 10.8 84.915 ;
     RECT  2.16 85.185 10.8 85.455 ;
     RECT  2.16 85.725 10.8 85.995 ;
     RECT  2.16 86.265 10.8 86.535 ;
     RECT  2.16 86.805 10.8 87.075 ;
     RECT  2.16 87.345 10.8 87.615 ;
     RECT  2.16 87.885 10.8 88.155 ;
     RECT  2.16 88.425 10.8 88.695 ;
     RECT  2.16 88.965 10.8 89.235 ;
     RECT  2.16 89.505 10.8 89.775 ;
     RECT  2.16 90.045 10.8 90.315 ;
     RECT  2.16 90.585 10.8 90.855 ;
     RECT  2.16 91.125 10.8 91.395 ;
     RECT  2.16 91.665 10.8 91.935 ;
     RECT  2.16 92.205 10.8 92.475 ;
     RECT  2.16 92.745 10.8 93.015 ;
     RECT  2.16 93.285 10.8 93.555 ;
     RECT  2.16 93.825 10.8 94.095 ;
     RECT  2.16 94.365 10.8 94.635 ;
     RECT  2.16 94.905 10.8 95.175 ;
     RECT  2.16 95.445 10.8 95.715 ;
     RECT  2.16 95.985 10.8 96.255 ;
     RECT  2.16 96.525 10.8 96.795 ;
     RECT  2.16 97.065 10.8 97.335 ;
     RECT  2.16 97.605 10.8 97.875 ;
     RECT  2.16 98.145 10.8 98.415 ;
     RECT  2.16 98.685 10.8 98.955 ;
     RECT  2.16 99.225 10.8 99.495 ;
     RECT  2.16 99.765 10.8 100.035 ;
     RECT  2.16 100.305 10.8 100.575 ;
     RECT  2.16 100.845 10.8 101.115 ;
     RECT  2.16 101.385 10.8 101.655 ;
     RECT  2.16 101.925 10.8 102.195 ;
     RECT  2.16 102.465 10.8 102.735 ;
     RECT  2.16 103.005 10.8 103.275 ;
     RECT  2.16 103.545 10.8 103.815 ;
     RECT  2.16 104.085 10.8 104.355 ;
     RECT  2.16 104.625 10.8 104.895 ;
     RECT  2.16 105.165 10.8 105.435 ;
     RECT  2.16 105.705 10.8 105.84 ;
    LAYER RVTP ;
     RECT  2.16 2.295 10.8 2.565 ;
     RECT  2.16 2.835 10.8 3.105 ;
     RECT  2.16 3.375 10.8 3.645 ;
     RECT  2.16 3.915 10.8 4.185 ;
     RECT  2.16 4.455 10.8 4.725 ;
     RECT  2.16 4.995 10.8 5.265 ;
     RECT  2.16 5.535 10.8 5.805 ;
     RECT  2.16 6.075 10.8 6.345 ;
     RECT  2.16 6.615 10.8 6.885 ;
     RECT  2.16 7.155 10.8 7.425 ;
     RECT  2.16 7.695 10.8 7.965 ;
     RECT  2.16 8.235 10.8 8.505 ;
     RECT  2.16 8.775 10.8 9.045 ;
     RECT  2.16 9.315 10.8 9.585 ;
     RECT  2.16 9.855 10.8 10.125 ;
     RECT  2.16 10.395 10.8 10.665 ;
     RECT  2.16 10.935 10.8 11.205 ;
     RECT  2.16 11.475 10.8 11.745 ;
     RECT  2.16 12.015 10.8 12.285 ;
     RECT  2.16 12.555 10.8 12.825 ;
     RECT  2.16 13.095 10.8 13.365 ;
     RECT  2.16 13.635 10.8 13.905 ;
     RECT  2.16 14.175 10.8 14.445 ;
     RECT  2.16 14.715 10.8 14.985 ;
     RECT  2.16 15.255 10.8 15.525 ;
     RECT  2.16 15.795 10.8 16.065 ;
     RECT  2.16 16.335 10.8 16.605 ;
     RECT  2.16 16.875 10.8 17.145 ;
     RECT  2.16 17.415 10.8 17.685 ;
     RECT  2.16 17.955 10.8 18.225 ;
     RECT  2.16 18.495 10.8 18.765 ;
     RECT  2.16 19.035 10.8 19.305 ;
     RECT  2.16 19.575 10.8 19.845 ;
     RECT  2.16 20.115 10.8 20.385 ;
     RECT  2.16 20.655 10.8 20.925 ;
     RECT  2.16 21.195 10.8 21.465 ;
     RECT  2.16 21.735 10.8 22.005 ;
     RECT  2.16 22.275 10.8 22.545 ;
     RECT  2.16 22.815 10.8 23.085 ;
     RECT  2.16 23.355 10.8 23.625 ;
     RECT  2.16 23.895 10.8 24.165 ;
     RECT  2.16 24.435 10.8 24.705 ;
     RECT  2.16 24.975 10.8 25.245 ;
     RECT  2.16 25.515 10.8 25.785 ;
     RECT  2.16 26.055 10.8 26.325 ;
     RECT  2.16 26.595 10.8 26.865 ;
     RECT  2.16 27.135 10.8 27.405 ;
     RECT  2.16 27.675 10.8 27.945 ;
     RECT  2.16 28.215 10.8 28.485 ;
     RECT  2.16 28.755 10.8 29.025 ;
     RECT  2.16 29.295 10.8 29.565 ;
     RECT  2.16 29.835 10.8 30.105 ;
     RECT  2.16 30.375 10.8 30.645 ;
     RECT  2.16 30.915 10.8 31.185 ;
     RECT  2.16 31.455 10.8 31.725 ;
     RECT  2.16 31.995 10.8 32.265 ;
     RECT  2.16 32.535 10.8 32.805 ;
     RECT  2.16 33.075 10.8 33.345 ;
     RECT  2.16 33.615 10.8 33.885 ;
     RECT  2.16 34.155 10.8 34.425 ;
     RECT  2.16 34.695 10.8 34.965 ;
     RECT  2.16 35.235 10.8 35.505 ;
     RECT  2.16 35.775 10.8 36.045 ;
     RECT  2.16 36.315 10.8 36.585 ;
     RECT  2.16 36.855 10.8 37.125 ;
     RECT  2.16 37.395 10.8 37.665 ;
     RECT  2.16 37.935 10.8 38.205 ;
     RECT  2.16 38.475 10.8 38.745 ;
     RECT  2.16 39.015 10.8 39.285 ;
     RECT  2.16 39.555 10.8 39.825 ;
     RECT  2.16 40.095 10.8 40.365 ;
     RECT  2.16 40.635 10.8 40.905 ;
     RECT  2.16 41.175 10.8 41.445 ;
     RECT  2.16 41.715 10.8 41.985 ;
     RECT  2.16 42.255 10.8 42.525 ;
     RECT  2.16 42.795 10.8 43.065 ;
     RECT  2.16 43.335 10.8 43.605 ;
     RECT  2.16 43.875 10.8 44.145 ;
     RECT  2.16 44.415 10.8 44.685 ;
     RECT  2.16 44.955 10.8 45.225 ;
     RECT  2.16 45.495 10.8 45.765 ;
     RECT  2.16 46.035 10.8 46.305 ;
     RECT  2.16 46.575 10.8 46.845 ;
     RECT  2.16 47.115 10.8 47.385 ;
     RECT  2.16 47.655 10.8 47.925 ;
     RECT  2.16 48.195 10.8 48.465 ;
     RECT  2.16 48.735 10.8 49.005 ;
     RECT  2.16 49.275 10.8 49.545 ;
     RECT  2.16 49.815 10.8 50.085 ;
     RECT  2.16 50.355 10.8 50.625 ;
     RECT  2.16 50.895 10.8 51.165 ;
     RECT  2.16 51.435 10.8 51.705 ;
     RECT  2.16 51.975 10.8 52.245 ;
     RECT  2.16 52.515 10.8 52.785 ;
     RECT  2.16 53.055 10.8 53.325 ;
     RECT  2.16 53.595 10.8 53.865 ;
     RECT  2.16 54.135 10.8 54.405 ;
     RECT  2.16 54.675 10.8 54.945 ;
     RECT  2.16 55.215 10.8 55.485 ;
     RECT  2.16 55.755 10.8 56.025 ;
     RECT  2.16 56.295 10.8 56.565 ;
     RECT  2.16 56.835 10.8 57.105 ;
     RECT  2.16 57.375 10.8 57.645 ;
     RECT  2.16 57.915 10.8 58.185 ;
     RECT  2.16 58.455 10.8 58.725 ;
     RECT  2.16 58.995 10.8 59.265 ;
     RECT  2.16 59.535 10.8 59.805 ;
     RECT  2.16 60.075 10.8 60.345 ;
     RECT  2.16 60.615 10.8 60.885 ;
     RECT  2.16 61.155 10.8 61.425 ;
     RECT  2.16 61.695 10.8 61.965 ;
     RECT  2.16 62.235 10.8 62.505 ;
     RECT  2.16 62.775 10.8 63.045 ;
     RECT  2.16 63.315 10.8 63.585 ;
     RECT  2.16 63.855 10.8 64.125 ;
     RECT  2.16 64.395 10.8 64.665 ;
     RECT  2.16 64.935 10.8 65.205 ;
     RECT  2.16 65.475 10.8 65.745 ;
     RECT  2.16 66.015 10.8 66.285 ;
     RECT  2.16 66.555 10.8 66.825 ;
     RECT  2.16 67.095 10.8 67.365 ;
     RECT  2.16 67.635 10.8 67.905 ;
     RECT  2.16 68.175 10.8 68.445 ;
     RECT  2.16 68.715 10.8 68.985 ;
     RECT  2.16 69.255 10.8 69.525 ;
     RECT  2.16 69.795 10.8 70.065 ;
     RECT  2.16 70.335 10.8 70.605 ;
     RECT  2.16 70.875 10.8 71.145 ;
     RECT  2.16 71.415 10.8 71.685 ;
     RECT  2.16 71.955 10.8 72.225 ;
     RECT  2.16 72.495 10.8 72.765 ;
     RECT  2.16 73.035 10.8 73.305 ;
     RECT  2.16 73.575 10.8 73.845 ;
     RECT  2.16 74.115 10.8 74.385 ;
     RECT  2.16 74.655 10.8 74.925 ;
     RECT  2.16 75.195 10.8 75.465 ;
     RECT  2.16 75.735 10.8 76.005 ;
     RECT  2.16 76.275 10.8 76.545 ;
     RECT  2.16 76.815 10.8 77.085 ;
     RECT  2.16 77.355 10.8 77.625 ;
     RECT  2.16 77.895 10.8 78.165 ;
     RECT  2.16 78.435 10.8 78.705 ;
     RECT  2.16 78.975 10.8 79.245 ;
     RECT  2.16 79.515 10.8 79.785 ;
     RECT  2.16 80.055 10.8 80.325 ;
     RECT  2.16 80.595 10.8 80.865 ;
     RECT  2.16 81.135 10.8 81.405 ;
     RECT  2.16 81.675 10.8 81.945 ;
     RECT  2.16 82.215 10.8 82.485 ;
     RECT  2.16 82.755 10.8 83.025 ;
     RECT  2.16 83.295 10.8 83.565 ;
     RECT  2.16 83.835 10.8 84.105 ;
     RECT  2.16 84.375 10.8 84.645 ;
     RECT  2.16 84.915 10.8 85.185 ;
     RECT  2.16 85.455 10.8 85.725 ;
     RECT  2.16 85.995 10.8 86.265 ;
     RECT  2.16 86.535 10.8 86.805 ;
     RECT  2.16 87.075 10.8 87.345 ;
     RECT  2.16 87.615 10.8 87.885 ;
     RECT  2.16 88.155 10.8 88.425 ;
     RECT  2.16 88.695 10.8 88.965 ;
     RECT  2.16 89.235 10.8 89.505 ;
     RECT  2.16 89.775 10.8 90.045 ;
     RECT  2.16 90.315 10.8 90.585 ;
     RECT  2.16 90.855 10.8 91.125 ;
     RECT  2.16 91.395 10.8 91.665 ;
     RECT  2.16 91.935 10.8 92.205 ;
     RECT  2.16 92.475 10.8 92.745 ;
     RECT  2.16 93.015 10.8 93.285 ;
     RECT  2.16 93.555 10.8 93.825 ;
     RECT  2.16 94.095 10.8 94.365 ;
     RECT  2.16 94.635 10.8 94.905 ;
     RECT  2.16 95.175 10.8 95.445 ;
     RECT  2.16 95.715 10.8 95.985 ;
     RECT  2.16 96.255 10.8 96.525 ;
     RECT  2.16 96.795 10.8 97.065 ;
     RECT  2.16 97.335 10.8 97.605 ;
     RECT  2.16 97.875 10.8 98.145 ;
     RECT  2.16 98.415 10.8 98.685 ;
     RECT  2.16 98.955 10.8 99.225 ;
     RECT  2.16 99.495 10.8 99.765 ;
     RECT  2.16 100.035 10.8 100.305 ;
     RECT  2.16 100.575 10.8 100.845 ;
     RECT  2.16 101.115 10.8 101.385 ;
     RECT  2.16 101.655 10.8 101.925 ;
     RECT  2.16 102.195 10.8 102.465 ;
     RECT  2.16 102.735 10.8 103.005 ;
     RECT  2.16 103.275 10.8 103.545 ;
     RECT  2.16 103.815 10.8 104.085 ;
     RECT  2.16 104.355 10.8 104.625 ;
     RECT  2.16 104.895 10.8 105.165 ;
     RECT  2.16 105.435 10.8 105.705 ;
    LAYER M1 ;
     RECT  2.16 2.151 10.8 105.849 ;
    LAYER M2 ;
     RECT  0.103 5.04 2.16 5.058 ;
     RECT  0.103 55.8 2.16 55.818 ;
     RECT  2.16 2.151 10.8 105.849 ;
     RECT  10.8 2.421 10.812 105.579 ;
     RECT  10.812 47.286 10.895 51.534 ;
     RECT  10.812 2.466 11.399 3.672 ;
     RECT  10.812 88.866 11.399 89.964 ;
     RECT  10.812 96.966 11.399 99.684 ;
     RECT  10.812 4.626 11.435 8.964 ;
     RECT  10.812 9.756 11.435 12.474 ;
     RECT  10.812 14.076 11.435 18.684 ;
     RECT  10.812 19.476 11.435 21.924 ;
     RECT  10.812 22.716 11.435 25.434 ;
     RECT  10.812 27.036 11.435 29.934 ;
     RECT  10.812 30.816 11.435 33.534 ;
     RECT  10.812 35.136 11.435 38.664 ;
     RECT  10.812 39.456 11.435 40.554 ;
     RECT  10.812 43.776 11.435 46.494 ;
     RECT  10.895 47.286 11.435 51.354 ;
     RECT  10.812 52.416 11.435 55.134 ;
     RECT  10.812 56.736 11.435 57.834 ;
     RECT  10.812 58.626 11.435 61.344 ;
     RECT  10.812 62.946 11.435 70.524 ;
     RECT  10.812 71.586 11.435 72.684 ;
     RECT  10.812 73.476 11.435 75.114 ;
     RECT  10.812 75.906 11.435 78.624 ;
     RECT  10.812 80.226 11.435 83.754 ;
     RECT  10.812 86.706 11.435 88.074 ;
     RECT  11.399 89.676 11.435 89.964 ;
     RECT  10.812 94.266 11.435 96.174 ;
     RECT  10.812 101.286 11.435 105.354 ;
     RECT  11.435 4.626 11.939 5.724 ;
     RECT  11.399 2.466 11.975 2.484 ;
     RECT  11.399 3.276 11.975 3.672 ;
     RECT  11.939 4.734 11.975 5.724 ;
     RECT  11.435 8.946 11.975 8.964 ;
     RECT  11.435 9.756 11.975 10.584 ;
     RECT  11.435 11.376 11.975 12.474 ;
     RECT  10.812 13.266 11.975 13.284 ;
     RECT  11.435 14.076 11.975 14.364 ;
     RECT  11.435 15.696 11.975 18.684 ;
     RECT  11.435 20.016 11.975 21.114 ;
     RECT  11.435 21.906 11.975 21.924 ;
     RECT  11.435 22.716 11.975 23.004 ;
     RECT  11.435 24.336 11.975 25.434 ;
     RECT  10.812 26.226 11.975 26.244 ;
     RECT  11.435 27.036 11.975 27.864 ;
     RECT  11.435 28.656 11.975 29.754 ;
     RECT  11.435 30.816 11.975 31.104 ;
     RECT  11.435 31.896 11.975 33.534 ;
     RECT  10.812 34.326 11.975 34.344 ;
     RECT  11.435 35.136 11.975 35.46 ;
     RECT  11.435 36.756 11.975 37.584 ;
     RECT  11.435 38.646 11.975 38.664 ;
     RECT  11.435 39.456 11.975 39.474 ;
     RECT  10.812 41.346 11.975 42.174 ;
     RECT  10.812 42.966 11.975 42.984 ;
     RECT  11.435 43.776 11.975 44.604 ;
     RECT  11.435 45.936 11.975 46.494 ;
     RECT  11.435 47.286 11.975 48.654 ;
     RECT  11.435 49.716 11.975 51.354 ;
     RECT  11.435 52.416 11.975 53.244 ;
     RECT  11.435 54.036 11.975 55.134 ;
     RECT  10.812 55.926 11.975 55.944 ;
     RECT  11.435 56.736 11.975 57.024 ;
     RECT  11.435 58.626 11.975 59.184 ;
     RECT  11.435 60.246 11.975 61.344 ;
     RECT  10.812 62.136 11.975 62.154 ;
     RECT  11.435 62.946 11.975 63.774 ;
     RECT  11.435 64.566 11.975 65.124 ;
     RECT  11.435 66.456 11.975 67.734 ;
     RECT  11.435 68.886 11.975 70.524 ;
     RECT  11.435 71.586 11.975 72.216 ;
     RECT  11.435 73.476 11.975 74.07 ;
     RECT  11.435 75.096 11.975 75.114 ;
     RECT  11.435 75.906 11.975 76.194 ;
     RECT  11.435 77.526 11.975 78.624 ;
     RECT  10.812 79.416 11.975 79.434 ;
     RECT  11.435 80.226 11.975 80.694 ;
     RECT  11.435 81.846 11.975 81.864 ;
     RECT  11.435 82.764 11.975 83.754 ;
     RECT  10.812 84.546 11.975 85.914 ;
     RECT  11.435 86.706 11.975 87.174 ;
     RECT  11.435 88.056 11.975 88.074 ;
     RECT  11.399 88.866 11.975 88.884 ;
     RECT  11.435 89.676 11.975 89.694 ;
     RECT  10.812 90.756 11.975 91.584 ;
     RECT  10.812 92.376 11.975 93.474 ;
     RECT  11.435 94.266 11.975 95.094 ;
     RECT  11.435 96.156 11.975 96.174 ;
     RECT  11.399 96.966 11.975 97.794 ;
     RECT  11.399 98.586 11.975 99.684 ;
     RECT  10.812 100.476 11.975 100.494 ;
     RECT  11.435 101.286 11.975 101.574 ;
     RECT  11.435 102.906 11.975 105.354 ;
     RECT  11.435 6.786 12.011 7.884 ;
     RECT  11.975 12.456 12.011 12.474 ;
     RECT  11.975 16.956 12.011 16.974 ;
     RECT  11.975 18.666 12.011 18.684 ;
     RECT  11.975 25.416 12.011 25.434 ;
     RECT  11.975 31.896 12.011 31.914 ;
     RECT  11.975 33.516 12.011 33.534 ;
     RECT  11.975 37.566 12.011 37.584 ;
     RECT  11.975 42.156 12.011 42.174 ;
     RECT  11.975 46.476 12.011 46.494 ;
     RECT  11.975 48.366 12.011 48.384 ;
     RECT  11.975 49.986 12.011 50.004 ;
     RECT  11.975 55.116 12.011 55.134 ;
     RECT  11.975 59.166 12.011 59.184 ;
     RECT  11.975 61.326 12.011 61.344 ;
     RECT  11.975 67.572 12.011 67.59 ;
     RECT  11.975 70.506 12.011 70.524 ;
     RECT  11.975 74.052 12.011 74.07 ;
     RECT  11.975 78.606 12.011 78.624 ;
     RECT  11.975 83.196 12.011 83.214 ;
     RECT  11.975 85.896 12.011 85.914 ;
     RECT  11.975 91.566 12.011 91.584 ;
     RECT  11.975 93.456 12.011 93.474 ;
     RECT  11.975 95.076 12.011 95.094 ;
     RECT  11.975 99.666 12.011 99.684 ;
     RECT  11.975 104.166 12.011 104.184 ;
     RECT  11.975 105.336 12.011 105.354 ;
     RECT  12.011 7.128 12.875 7.146 ;
     RECT  11.975 21.096 12.875 21.114 ;
     RECT  11.975 35.442 12.875 35.46 ;
     RECT  11.975 57.006 12.875 57.024 ;
     RECT  11.975 101.556 12.875 101.574 ;
    LAYER M3 ;
     RECT  2.415 2.143 2.505 2.413 ;
     RECT  5.115 2.143 5.205 2.413 ;
     RECT  7.815 2.143 7.905 2.413 ;
     RECT  10.515 2.143 10.605 2.413 ;
     RECT  7.815 2.413 8.097 2.641 ;
     RECT  9.468 2.461 9.486 2.641 ;
     RECT  10.515 2.413 10.797 2.641 ;
     RECT  9.468 2.641 10.797 2.683 ;
     RECT  11.952 2.203 11.97 2.683 ;
     RECT  9.468 2.683 11.97 2.759 ;
     RECT  7.815 2.641 8.154 3.181 ;
     RECT  5.115 2.413 5.397 3.271 ;
     RECT  7.815 3.181 8.586 3.415 ;
     RECT  9.468 2.759 10.797 3.415 ;
     RECT  7.815 3.415 10.797 3.569 ;
     RECT  5.115 3.271 5.778 4.081 ;
     RECT  5.115 4.081 6.246 4.225 ;
     RECT  7.815 3.569 8.694 4.495 ;
     RECT  9.468 3.569 10.797 4.495 ;
     RECT  5.115 4.225 6.282 4.531 ;
     RECT  11.952 2.759 11.97 4.603 ;
     RECT  7.815 4.495 10.797 4.649 ;
     RECT  11.916 4.603 11.97 4.649 ;
     RECT  10.116 4.649 10.797 4.685 ;
     RECT  2.415 2.413 2.697 5.035 ;
     RECT  5.115 4.531 6.426 5.071 ;
     RECT  0.108 5.035 0.126 5.261 ;
     RECT  5.115 5.071 6.606 5.305 ;
     RECT  4.572 5.305 6.75 5.333 ;
     RECT  2.415 5.035 2.898 5.459 ;
     RECT  2.415 5.459 2.697 5.575 ;
     RECT  10.515 4.685 10.797 5.701 ;
     RECT  4.572 5.333 5.706 5.729 ;
     RECT  11.952 4.649 11.97 5.729 ;
     RECT  10.044 5.701 10.797 5.801 ;
     RECT  4.716 5.729 5.67 5.999 ;
     RECT  10.44 5.801 10.797 6.037 ;
     RECT  6.588 5.333 6.75 6.043 ;
     RECT  10.44 6.037 11.43 6.077 ;
     RECT  7.815 4.649 9.018 6.115 ;
     RECT  2.304 5.575 2.697 6.655 ;
     RECT  4.752 5.999 5.67 6.691 ;
     RECT  6.588 6.043 6.822 6.691 ;
     RECT  7.815 6.115 9.234 6.691 ;
     RECT  10.44 6.077 10.797 6.691 ;
     RECT  4.752 6.691 6.822 6.781 ;
     RECT  2.304 6.655 2.898 6.809 ;
     RECT  4.752 6.781 6.894 6.809 ;
     RECT  7.815 6.691 10.797 6.881 ;
     RECT  4.752 6.809 5.397 6.925 ;
     RECT  12.852 6.523 12.87 7.151 ;
     RECT  4.572 6.925 5.397 7.187 ;
     RECT  6.552 6.809 6.894 7.231 ;
     RECT  7.815 6.881 8.622 7.231 ;
     RECT  6.552 7.231 8.622 7.349 ;
     RECT  3.888 7.321 3.906 7.421 ;
     RECT  6.552 7.349 8.097 7.421 ;
     RECT  5.115 7.187 5.397 7.735 ;
     RECT  9.468 6.881 10.797 7.771 ;
     RECT  5.115 7.735 5.598 7.861 ;
     RECT  6.732 7.421 8.097 7.889 ;
     RECT  11.988 6.781 12.006 7.997 ;
     RECT  5.115 7.861 5.742 8.041 ;
     RECT  6.732 7.889 6.75 8.159 ;
     RECT  5.115 8.041 5.886 8.275 ;
     RECT  7.815 7.889 8.097 8.311 ;
     RECT  8.82 7.771 10.797 8.311 ;
     RECT  2.304 6.809 2.862 8.429 ;
     RECT  4.752 8.275 5.886 8.429 ;
     RECT  7.815 8.311 11.43 8.429 ;
     RECT  10.404 8.429 11.43 8.477 ;
     RECT  4.752 8.429 5.397 8.545 ;
     RECT  4.572 8.545 5.397 8.699 ;
     RECT  4.932 8.699 5.397 9.481 ;
     RECT  4.644 9.481 5.397 9.581 ;
     RECT  2.304 8.429 2.697 9.625 ;
     RECT  6.264 8.539 6.678 9.661 ;
     RECT  7.815 8.429 9.558 9.661 ;
     RECT  10.404 8.477 10.797 9.661 ;
     RECT  5.115 9.581 5.397 9.751 ;
     RECT  6.264 9.661 7.002 9.751 ;
     RECT  2.304 9.625 2.862 9.779 ;
     RECT  5.115 9.751 7.002 10.319 ;
     RECT  5.115 10.319 6.534 10.435 ;
     RECT  7.815 9.661 10.797 10.471 ;
     RECT  11.952 8.923 11.97 10.589 ;
     RECT  7.38 10.471 10.797 10.831 ;
     RECT  7.38 10.831 11.43 10.877 ;
     RECT  5.076 10.435 6.534 10.975 ;
     RECT  4.284 10.975 6.534 11.129 ;
     RECT  7.38 10.877 10.797 11.399 ;
     RECT  2.304 9.779 2.697 11.443 ;
     RECT  4.572 11.129 5.886 11.669 ;
     RECT  7.815 11.399 10.797 11.669 ;
     RECT  4.572 11.669 5.814 12.091 ;
     RECT  11.952 11.323 11.97 12.389 ;
     RECT  4.428 12.091 5.814 12.479 ;
     RECT  5.115 12.479 5.814 12.523 ;
     RECT  7.815 11.669 9.486 12.523 ;
     RECT  10.26 11.669 10.797 12.523 ;
     RECT  5.115 12.523 6.498 12.557 ;
     RECT  11.988 12.451 12.006 12.797 ;
     RECT  6.372 12.557 6.498 12.829 ;
     RECT  7.815 12.523 10.797 12.901 ;
     RECT  6.372 12.829 6.858 13.019 ;
     RECT  7.668 12.901 10.797 13.019 ;
     RECT  7.668 13.019 9.342 13.289 ;
     RECT  2.304 11.443 2.862 13.325 ;
     RECT  6.48 13.019 6.858 13.441 ;
     RECT  5.115 12.557 5.598 13.559 ;
     RECT  4.212 13.531 4.23 13.631 ;
     RECT  7.815 13.289 9.342 13.981 ;
     RECT  10.152 13.019 10.797 13.981 ;
     RECT  2.376 13.325 2.862 14.215 ;
     RECT  11.952 13.243 11.97 14.369 ;
     RECT  5.115 13.559 5.397 14.521 ;
     RECT  6.48 13.441 6.894 14.521 ;
     RECT  7.815 13.981 10.797 14.549 ;
     RECT  2.268 14.215 2.862 14.573 ;
     RECT  9 14.549 10.797 14.675 ;
     RECT  9.468 14.675 10.797 14.677 ;
     RECT  2.304 14.573 2.862 14.755 ;
     RECT  2.304 14.755 3.402 14.813 ;
     RECT  5.115 14.521 6.894 14.819 ;
     RECT  5.115 14.819 6.858 15.017 ;
     RECT  2.34 14.813 3.402 15.025 ;
     RECT  7.815 14.549 8.262 15.061 ;
     RECT  2.34 15.025 3.546 15.179 ;
     RECT  9.468 14.677 11.43 15.179 ;
     RECT  9.9 15.179 11.43 15.197 ;
     RECT  7.704 15.061 8.262 15.331 ;
     RECT  2.34 15.179 2.862 15.449 ;
     RECT  6.408 15.017 6.858 15.449 ;
     RECT  2.34 15.449 2.697 15.565 ;
     RECT  7.704 15.331 8.37 15.601 ;
     RECT  7.704 15.601 8.73 15.719 ;
     RECT  9.9 15.197 10.797 15.719 ;
     RECT  6.408 15.449 6.714 15.869 ;
     RECT  10.44 15.719 10.797 15.989 ;
     RECT  6.408 15.869 6.57 16.097 ;
     RECT  7.815 15.719 8.73 16.141 ;
     RECT  3.96 16.069 3.978 16.259 ;
     RECT  6.156 16.141 6.174 16.259 ;
     RECT  7.815 16.141 8.802 16.375 ;
     RECT  5.115 15.017 5.397 16.411 ;
     RECT  5.115 16.411 5.454 16.501 ;
     RECT  3.744 16.375 3.762 16.529 ;
     RECT  2.304 15.565 2.697 16.645 ;
     RECT  7.815 16.375 9.306 16.681 ;
     RECT  11.952 15.643 11.97 16.799 ;
     RECT  7.452 16.681 9.306 16.915 ;
     RECT  10.515 15.989 10.797 16.915 ;
     RECT  7.452 16.915 9.702 16.951 ;
     RECT  10.44 16.915 10.797 16.951 ;
     RECT  4.896 16.501 5.454 17.041 ;
     RECT  4.68 17.041 5.454 17.069 ;
     RECT  7.452 16.951 10.797 17.069 ;
     RECT  2.304 16.645 2.862 17.077 ;
     RECT  6.516 17.077 6.534 17.117 ;
     RECT  11.988 16.951 12.006 17.117 ;
     RECT  4.68 17.069 5.397 17.213 ;
     RECT  7.524 17.069 9.378 17.339 ;
     RECT  6.588 17.491 6.75 17.549 ;
     RECT  5.076 17.213 5.397 17.609 ;
     RECT  6.732 17.549 6.75 17.609 ;
     RECT  2.304 17.077 2.934 17.617 ;
     RECT  7.815 17.339 9.378 17.681 ;
     RECT  2.304 17.617 3.006 17.995 ;
     RECT  2.304 17.995 3.438 18.149 ;
     RECT  6.876 17.995 7.074 18.149 ;
     RECT  6.876 18.149 6.894 18.221 ;
     RECT  10.26 17.069 10.797 18.301 ;
     RECT  5.115 17.609 5.397 18.523 ;
     RECT  7.815 17.681 8.622 18.535 ;
     RECT  9.936 18.301 10.797 18.535 ;
     RECT  11.952 17.563 11.97 18.599 ;
     RECT  5.115 18.523 5.454 18.769 ;
     RECT  11.988 18.661 12.006 19.037 ;
     RECT  2.304 18.149 3.222 19.075 ;
     RECT  6.516 18.955 6.534 19.111 ;
     RECT  7.815 18.535 10.797 19.229 ;
     RECT  5.115 18.769 5.598 19.345 ;
     RECT  6.516 19.111 7.038 19.381 ;
     RECT  9.108 19.229 10.797 19.471 ;
     RECT  2.304 19.075 3.33 19.499 ;
     RECT  9.108 19.471 11.43 19.517 ;
     RECT  4.572 19.345 5.598 19.651 ;
     RECT  6.372 19.381 7.038 19.651 ;
     RECT  4.176 19.651 7.038 19.769 ;
     RECT  4.176 19.769 4.194 19.805 ;
     RECT  5.115 19.769 7.038 19.921 ;
     RECT  7.815 19.229 8.154 19.921 ;
     RECT  5.115 19.921 8.154 20.191 ;
     RECT  9.108 19.517 10.797 20.191 ;
     RECT  5.115 20.191 10.797 20.219 ;
     RECT  6.516 20.219 10.797 20.309 ;
     RECT  2.304 19.499 2.862 20.345 ;
     RECT  6.516 20.309 9.342 20.345 ;
     RECT  5.115 20.219 5.706 20.579 ;
     RECT  6.516 20.345 8.55 20.579 ;
     RECT  11.952 19.963 11.97 20.579 ;
     RECT  5.115 20.579 5.562 20.909 ;
     RECT  2.34 20.345 2.862 21.115 ;
     RECT  2.304 21.115 2.862 21.119 ;
     RECT  12.852 20.923 12.87 21.119 ;
     RECT  9.324 20.345 9.342 21.235 ;
     RECT  10.152 20.309 10.797 21.235 ;
     RECT  5.115 20.909 5.454 21.389 ;
     RECT  9.324 21.235 10.797 21.397 ;
     RECT  2.304 21.119 2.697 21.425 ;
     RECT  9.324 21.397 11.43 21.437 ;
     RECT  6.516 20.579 6.858 21.461 ;
     RECT  7.815 20.579 8.55 21.505 ;
     RECT  9.324 21.437 10.797 21.505 ;
     RECT  2.34 21.425 2.697 21.533 ;
     RECT  6.516 21.461 6.786 21.541 ;
     RECT  7.815 21.505 10.797 21.541 ;
     RECT  3.888 21.433 3.906 21.659 ;
     RECT  6.228 21.541 6.786 21.659 ;
     RECT  7.56 21.541 10.797 21.659 ;
     RECT  5.115 21.389 5.397 21.775 ;
     RECT  3.708 21.775 3.726 22.199 ;
     RECT  6.228 21.659 6.534 22.199 ;
     RECT  7.815 21.659 10.797 22.199 ;
     RECT  2.415 21.533 2.697 22.315 ;
     RECT  5.04 21.775 5.397 22.315 ;
     RECT  6.516 22.199 6.534 22.441 ;
     RECT  2.412 22.315 2.697 22.459 ;
     RECT  6.516 22.441 6.642 22.621 ;
     RECT  6.516 22.621 6.858 22.739 ;
     RECT  4.932 22.315 5.397 22.855 ;
     RECT  4.572 22.855 5.397 22.987 ;
     RECT  6.516 22.739 6.642 22.987 ;
     RECT  11.952 21.883 11.97 23.009 ;
     RECT  4.572 22.987 6.642 23.045 ;
     RECT  2.304 22.459 2.697 23.125 ;
     RECT  10.515 22.199 10.797 23.125 ;
     RECT  2.304 23.125 2.97 23.161 ;
     RECT  7.815 22.199 9.234 23.161 ;
     RECT  4.572 23.045 5.706 23.279 ;
     RECT  7.416 23.161 9.378 23.279 ;
     RECT  2.304 23.161 3.15 23.315 ;
     RECT  9.36 23.279 9.378 23.315 ;
     RECT  10.116 23.125 10.797 23.317 ;
     RECT  6.444 23.045 6.642 23.357 ;
     RECT  5.004 23.279 5.706 23.549 ;
     RECT  7.74 23.279 8.55 23.549 ;
     RECT  10.116 23.317 11.43 23.665 ;
     RECT  5.004 23.549 5.562 23.819 ;
     RECT  9.468 23.665 11.43 23.837 ;
     RECT  2.304 23.315 3.114 24.359 ;
     RECT  9.468 23.837 10.797 24.359 ;
     RECT  2.304 24.359 2.697 24.475 ;
     RECT  6.768 24.331 6.786 24.511 ;
     RECT  7.74 23.549 8.514 24.511 ;
     RECT  6.696 24.511 6.786 24.523 ;
     RECT  5.004 23.819 5.397 24.601 ;
     RECT  6.408 24.523 6.786 24.601 ;
     RECT  7.632 24.511 8.514 24.629 ;
     RECT  5.004 24.601 6.786 24.745 ;
     RECT  7.704 24.629 8.514 24.781 ;
     RECT  2.268 24.475 2.697 24.797 ;
     RECT  4.896 24.745 6.786 25.015 ;
     RECT  7.704 24.781 9.306 25.169 ;
     RECT  10.404 24.359 10.797 25.24 ;
     RECT  11.952 24.283 11.97 25.24 ;
     RECT  4.572 25.015 6.786 25.241 ;
     RECT  10.404 25.24 11.97 25.277 ;
     RECT  10.404 25.277 10.797 25.285 ;
     RECT  6.408 25.241 6.786 25.325 ;
     RECT  4.572 25.241 5.397 25.439 ;
     RECT  6.552 25.325 6.786 25.591 ;
     RECT  7.704 25.169 8.37 25.591 ;
     RECT  9.288 25.169 9.306 25.591 ;
     RECT  10.08 25.285 10.797 25.591 ;
     RECT  2.415 24.797 2.697 25.675 ;
     RECT  11.988 25.411 12.006 25.757 ;
     RECT  9.288 25.591 10.797 25.979 ;
     RECT  2.304 25.675 2.697 26.015 ;
     RECT  9.288 25.979 9.378 26.095 ;
     RECT  5.004 25.439 5.397 26.203 ;
     RECT  9.216 26.095 9.378 26.249 ;
     RECT  5.004 26.203 5.742 26.329 ;
     RECT  6.552 25.591 8.37 26.393 ;
     RECT  4.608 26.329 5.742 26.401 ;
     RECT  7.815 26.393 8.37 26.401 ;
     RECT  4.608 26.401 5.886 26.429 ;
     RECT  2.34 26.015 2.697 26.491 ;
     RECT  9.36 26.249 9.378 26.519 ;
     RECT  2.34 26.491 3.258 26.591 ;
     RECT  7.815 26.401 8.442 26.671 ;
     RECT  2.34 26.591 3.078 26.779 ;
     RECT  7.815 26.671 8.514 26.789 ;
     RECT  2.304 26.779 3.078 27.059 ;
     RECT  7.815 26.789 8.262 27.059 ;
     RECT  2.304 27.059 2.754 27.149 ;
     RECT  9.396 27.175 9.414 27.301 ;
     RECT  6.66 26.393 6.966 27.329 ;
     RECT  9.216 27.301 9.414 27.445 ;
     RECT  10.152 25.979 10.797 27.445 ;
     RECT  5.115 26.429 5.886 27.751 ;
     RECT  6.66 27.329 6.786 27.751 ;
     RECT  5.115 27.751 6.786 27.773 ;
     RECT  5.115 27.773 6.642 27.869 ;
     RECT  11.952 26.203 11.97 27.869 ;
     RECT  9.216 27.445 10.797 28.111 ;
     RECT  6.264 27.869 6.642 28.139 ;
     RECT  9.216 28.111 11.43 28.157 ;
     RECT  7.815 27.059 8.097 28.219 ;
     RECT  5.115 27.869 5.397 28.255 ;
     RECT  7.815 28.219 8.442 28.291 ;
     RECT  9.216 28.157 10.797 28.291 ;
     RECT  7.815 28.291 10.797 28.319 ;
     RECT  4.392 28.255 5.397 28.409 ;
     RECT  6.408 28.139 6.642 28.507 ;
     RECT  2.304 27.149 2.697 28.541 ;
     RECT  5.004 28.409 5.397 28.679 ;
     RECT  7.815 28.319 8.55 28.679 ;
     RECT  9.468 28.319 10.797 28.679 ;
     RECT  6.408 28.507 6.894 28.715 ;
     RECT  6.408 28.715 6.822 29.219 ;
     RECT  2.415 28.541 2.697 29.419 ;
     RECT  5.115 28.679 5.397 29.467 ;
     RECT  6.408 29.219 6.642 29.467 ;
     RECT  4.284 29.335 4.302 29.489 ;
     RECT  9.216 29.101 9.306 29.605 ;
     RECT  10.404 28.679 10.797 29.605 ;
     RECT  7.815 28.679 8.097 29.731 ;
     RECT  9.216 29.605 10.797 29.731 ;
     RECT  5.115 29.467 6.642 29.759 ;
     RECT  11.952 28.603 11.97 29.759 ;
     RECT  2.304 29.419 2.697 29.875 ;
     RECT  7.815 29.731 10.797 29.911 ;
     RECT  5.115 29.759 6.57 29.939 ;
     RECT  3.924 29.767 3.942 30.029 ;
     RECT  5.115 29.939 6.102 30.029 ;
     RECT  7.815 29.911 11.43 30.029 ;
     RECT  7.815 30.029 9.486 30.065 ;
     RECT  10.515 30.029 11.43 30.077 ;
     RECT  5.115 30.029 5.922 30.145 ;
     RECT  7.815 30.065 8.802 30.181 ;
     RECT  2.304 29.875 2.862 30.299 ;
     RECT  7.416 30.181 8.802 30.569 ;
     RECT  5.04 30.145 5.922 30.685 ;
     RECT  4.572 30.685 5.922 30.749 ;
     RECT  7.815 30.569 8.802 30.955 ;
     RECT  4.68 30.749 5.922 30.989 ;
     RECT  11.952 30.523 11.97 31.109 ;
     RECT  2.304 30.299 2.79 31.225 ;
     RECT  10.515 30.077 10.797 31.225 ;
     RECT  7.815 30.955 9.27 31.261 ;
     RECT  10.116 31.225 10.797 31.261 ;
     RECT  7.815 31.261 10.797 31.423 ;
     RECT  7.815 31.423 11.43 31.469 ;
     RECT  6.192 31.351 6.21 31.495 ;
     RECT  7.815 31.469 10.797 31.649 ;
     RECT  4.68 30.989 5.397 31.765 ;
     RECT  7.815 31.649 8.55 31.829 ;
     RECT  6.192 31.495 6.57 31.891 ;
     RECT  4.572 31.765 5.397 31.919 ;
     RECT  9.288 31.649 10.797 31.919 ;
     RECT  11.988 31.891 12.006 31.949 ;
     RECT  4.788 31.919 5.397 32.161 ;
     RECT  6.192 31.891 6.858 32.161 ;
     RECT  2.304 31.225 2.862 32.189 ;
     RECT  4.788 32.161 6.858 32.189 ;
     RECT  4.788 32.189 6.282 32.333 ;
     RECT  7.815 31.829 8.097 32.341 ;
     RECT  4.824 32.333 6.282 32.369 ;
     RECT  4.824 32.369 5.886 32.381 ;
     RECT  9.468 31.919 10.797 32.459 ;
     RECT  2.304 32.189 2.697 32.717 ;
     RECT  7.452 32.341 8.097 32.971 ;
     RECT  4.824 32.381 5.706 33.115 ;
     RECT  4.608 33.115 5.706 33.241 ;
     RECT  6.84 32.971 8.097 33.269 ;
     RECT  4.608 33.241 5.958 33.385 ;
     RECT  6.84 33.269 6.858 33.385 ;
     RECT  10.476 32.459 10.797 33.385 ;
     RECT  11.952 32.395 11.97 33.449 ;
     RECT  7.815 33.269 8.097 33.511 ;
     RECT  9.216 32.881 9.306 33.511 ;
     RECT  4.608 33.385 6.858 33.539 ;
     RECT  7.815 33.511 9.306 33.547 ;
     RECT  2.376 32.717 2.697 33.643 ;
     RECT  5.04 33.539 6.858 33.809 ;
     RECT  7.815 33.547 9.522 33.809 ;
     RECT  10.296 33.385 10.797 33.809 ;
     RECT  11.988 33.511 12.006 33.869 ;
     RECT  2.304 33.643 2.697 33.925 ;
     RECT  5.04 33.809 6.534 34.079 ;
     RECT  7.815 33.809 8.19 34.079 ;
     RECT  5.115 34.079 6.534 34.591 ;
     RECT  2.304 33.925 2.862 34.735 ;
     RECT  5.115 34.591 6.57 34.735 ;
     RECT  7.815 34.079 8.154 34.735 ;
     RECT  2.304 34.735 3.402 34.889 ;
     RECT  9.396 33.809 9.522 35.041 ;
     RECT  10.515 33.809 10.797 35.041 ;
     RECT  5.115 34.735 8.154 35.069 ;
     RECT  11.952 34.312 11.97 35.159 ;
     RECT  4.068 35.041 4.086 35.267 ;
     RECT  9.396 35.041 10.797 35.275 ;
     RECT  12.852 35.275 12.87 35.465 ;
     RECT  7.815 35.069 8.154 35.581 ;
     RECT  9.288 35.275 10.797 35.671 ;
     RECT  5.115 35.069 6.894 35.699 ;
     RECT  9.288 35.671 11.43 35.699 ;
     RECT  6.48 35.699 6.894 35.741 ;
     RECT  7.815 35.581 8.514 35.851 ;
     RECT  7.815 35.851 8.55 36.077 ;
     RECT  9.468 35.699 11.43 36.239 ;
     RECT  9.54 36.239 11.43 36.269 ;
     RECT  5.115 35.699 5.397 36.475 ;
     RECT  9.54 36.269 10.797 36.509 ;
     RECT  6.48 35.741 6.858 36.779 ;
     RECT  3.78 36.751 3.798 36.851 ;
     RECT  5.115 36.475 5.706 36.931 ;
     RECT  6.48 36.779 6.498 36.931 ;
     RECT  7.815 36.077 8.442 36.931 ;
     RECT  3.6 36.895 3.618 37.049 ;
     RECT  7.38 36.931 8.514 37.049 ;
     RECT  7.38 37.049 8.097 37.499 ;
     RECT  11.952 36.715 11.97 37.561 ;
     RECT  5.115 36.931 6.498 37.589 ;
     RECT  9.864 36.509 10.797 37.705 ;
     RECT  11.952 37.561 12.006 37.709 ;
     RECT  6.48 37.589 6.498 37.741 ;
     RECT  2.304 34.889 2.862 37.853 ;
     RECT  6.48 37.741 6.57 37.867 ;
     RECT  6.48 37.867 6.642 37.895 ;
     RECT  9.576 37.705 10.797 37.975 ;
     RECT  9 37.975 10.797 38.011 ;
     RECT  2.415 37.853 2.862 38.129 ;
     RECT  9 38.011 11.43 38.165 ;
     RECT  9.432 38.165 11.43 38.189 ;
     RECT  5.115 37.589 5.706 38.245 ;
     RECT  6.624 37.895 6.642 38.551 ;
     RECT  4.608 38.245 5.706 38.669 ;
     RECT  7.56 37.499 8.097 38.669 ;
     RECT  2.415 38.129 2.697 38.713 ;
     RECT  6.624 38.551 6.786 38.765 ;
     RECT  9.432 38.189 10.797 38.911 ;
     RECT  4.68 38.669 5.706 38.939 ;
     RECT  9.36 38.911 10.797 38.939 ;
     RECT  7.632 38.669 8.097 39.011 ;
     RECT  9.36 38.939 9.378 39.011 ;
     RECT  2.34 38.713 2.697 39.245 ;
     RECT  4.788 38.939 5.706 39.289 ;
     RECT  4.788 39.289 5.742 39.479 ;
     RECT  11.952 38.632 11.97 39.479 ;
     RECT  10.515 38.939 10.797 39.595 ;
     RECT  5.115 39.479 5.742 39.631 ;
     RECT  2.412 39.245 2.697 39.677 ;
     RECT  9.216 39.595 9.234 39.721 ;
     RECT  9.036 39.721 9.234 39.821 ;
     RECT  2.415 39.677 2.697 39.865 ;
     RECT  9.216 39.821 9.234 39.865 ;
     RECT  2.415 39.865 2.862 39.991 ;
     RECT  6.84 39.091 6.858 40.127 ;
     RECT  9.216 39.865 9.738 40.135 ;
     RECT  10.515 39.595 11.43 40.135 ;
     RECT  2.415 39.991 2.898 40.163 ;
     RECT  7.815 39.011 8.097 40.171 ;
     RECT  5.115 39.631 5.886 40.219 ;
     RECT  2.415 40.163 2.862 40.289 ;
     RECT  5.115 40.219 6.642 40.289 ;
     RECT  7.812 40.171 8.097 40.289 ;
     RECT  2.415 40.289 2.697 40.405 ;
     RECT  5.115 40.289 5.886 40.559 ;
     RECT  9.216 40.135 11.43 40.589 ;
     RECT  9.216 40.589 10.797 40.711 ;
     RECT  9.108 40.711 10.797 40.829 ;
     RECT  9.72 40.829 10.797 40.901 ;
     RECT  5.115 40.559 5.706 40.945 ;
     RECT  6.624 40.289 6.642 40.981 ;
     RECT  7.815 40.289 8.097 40.981 ;
     RECT  9.864 40.901 10.797 41.099 ;
     RECT  7.815 40.981 8.226 41.369 ;
     RECT  4.716 40.945 5.706 41.485 ;
     RECT  6.624 40.981 6.786 41.485 ;
     RECT  2.304 40.405 2.697 41.549 ;
     RECT  4.716 41.485 6.786 41.639 ;
     RECT  2.415 41.549 2.697 41.755 ;
     RECT  8.964 41.341 8.982 41.755 ;
     RECT  2.415 41.755 2.898 41.909 ;
     RECT  4.716 41.639 6.462 41.909 ;
     RECT  4.716 41.909 5.397 42.025 ;
     RECT  10.515 41.099 10.797 42.025 ;
     RECT  11.952 41.035 11.97 42.089 ;
     RECT  7.815 41.369 8.154 42.151 ;
     RECT  8.964 41.755 9.306 42.151 ;
     RECT  4.5 42.025 5.397 42.179 ;
     RECT  7.815 42.151 9.306 42.259 ;
     RECT  2.415 41.909 2.862 42.295 ;
     RECT  7.815 42.259 9.486 42.331 ;
     RECT  10.26 42.025 10.797 42.331 ;
     RECT  7.815 42.331 10.797 42.485 ;
     RECT  11.988 42.151 12.006 42.509 ;
     RECT  6.3 41.909 6.462 42.565 ;
     RECT  6.3 42.565 6.786 42.593 ;
     RECT  2.304 42.295 2.862 42.719 ;
     RECT  2.304 42.719 2.697 42.941 ;
     RECT  7.815 42.485 9.486 42.989 ;
     RECT  10.26 42.485 10.797 43.061 ;
     RECT  6.444 42.593 6.786 43.231 ;
     RECT  6.444 43.231 6.858 43.259 ;
     RECT  7.815 42.989 9.234 43.259 ;
     RECT  5.115 42.179 5.397 43.267 ;
     RECT  6.624 43.259 6.858 43.439 ;
     RECT  4.572 43.267 5.397 43.529 ;
     RECT  6.732 43.439 6.858 43.571 ;
     RECT  6.84 43.571 6.858 43.609 ;
     RECT  4.788 43.529 5.397 43.645 ;
     RECT  4.788 43.645 5.67 43.681 ;
     RECT  6.84 43.609 6.894 43.709 ;
     RECT  4.788 43.681 5.814 43.799 ;
     RECT  6.876 43.709 6.894 43.799 ;
     RECT  2.415 42.941 2.697 43.807 ;
     RECT  9.216 43.259 9.234 44.041 ;
     RECT  7.815 43.259 8.406 44.149 ;
     RECT  9.216 44.041 9.486 44.149 ;
     RECT  2.412 43.807 2.697 44.185 ;
     RECT  7.815 44.149 9.486 44.185 ;
     RECT  10.515 43.061 10.797 44.185 ;
     RECT  5.115 43.799 5.814 44.221 ;
     RECT  7.815 44.185 10.797 44.339 ;
     RECT  11.952 42.952 11.97 44.609 ;
     RECT  5.115 44.221 5.85 44.725 ;
     RECT  7.815 44.339 8.514 44.789 ;
     RECT  2.304 44.185 2.697 44.813 ;
     RECT  10.296 44.339 10.797 44.851 ;
     RECT  2.415 44.813 2.697 45.031 ;
     RECT  4.5 44.725 5.85 45.059 ;
     RECT  4.68 45.059 5.85 45.149 ;
     RECT  2.415 45.031 2.826 45.265 ;
     RECT  9.288 44.339 9.414 45.265 ;
     RECT  10.296 44.851 11.43 45.265 ;
     RECT  5.115 45.149 5.85 45.301 ;
     RECT  9.288 45.265 11.43 45.389 ;
     RECT  2.415 45.265 3.006 45.419 ;
     RECT  9.288 45.389 10.797 45.419 ;
     RECT  2.415 45.419 2.697 45.535 ;
     RECT  6.84 44.851 6.858 45.689 ;
     RECT  9.288 45.419 9.414 45.689 ;
     RECT  9.288 45.689 9.306 45.841 ;
     RECT  4.176 45.805 4.194 45.959 ;
     RECT  11.952 45.835 11.97 45.959 ;
     RECT  2.304 45.535 2.697 46.205 ;
     RECT  10.515 45.419 10.797 46.309 ;
     RECT  5.115 45.301 5.922 46.345 ;
     RECT  10.515 46.309 10.854 46.345 ;
     RECT  10.08 46.345 10.854 46.349 ;
     RECT  5.115 46.345 6.75 46.615 ;
     RECT  9.036 45.841 9.306 46.615 ;
     RECT  10.08 46.349 10.797 46.615 ;
     RECT  4.824 46.615 6.75 46.651 ;
     RECT  7.815 44.789 8.097 46.651 ;
     RECT  9.036 46.615 10.797 46.651 ;
     RECT  4.824 46.651 6.894 46.769 ;
     RECT  11.988 46.471 12.006 46.829 ;
     RECT  2.376 46.205 2.697 46.921 ;
     RECT  7.815 46.651 10.797 46.949 ;
     RECT  4.86 46.769 6.894 47.039 ;
     RECT  2.376 46.921 2.79 47.047 ;
     RECT  6.228 47.039 6.894 47.219 ;
     RECT  6.228 47.219 6.462 47.309 ;
     RECT  9.468 46.949 10.797 47.309 ;
     RECT  2.304 47.047 2.79 47.425 ;
     RECT  4.86 47.039 5.397 47.551 ;
     RECT  2.304 47.425 2.862 47.579 ;
     RECT  4.752 47.551 5.397 47.695 ;
     RECT  7.815 46.949 8.097 47.731 ;
     RECT  6.3 47.309 6.462 48.119 ;
     RECT  4.572 47.695 5.397 48.235 ;
     RECT  9.54 47.309 10.797 48.235 ;
     RECT  4.464 48.235 5.397 48.271 ;
     RECT  7.815 47.731 8.19 48.299 ;
     RECT  4.464 48.271 5.49 48.331 ;
     RECT  11.952 47.272 11.97 48.361 ;
     RECT  9.108 48.235 10.797 48.541 ;
     RECT  4.464 48.331 5.778 48.631 ;
     RECT  8.928 48.541 10.797 48.659 ;
     RECT  9.036 48.659 9.486 48.695 ;
     RECT  10.332 48.659 10.797 48.731 ;
     RECT  11.952 48.361 12.006 48.749 ;
     RECT  4.212 48.631 5.778 48.775 ;
     RECT  4.032 48.775 5.778 48.929 ;
     RECT  2.304 47.579 2.697 48.989 ;
     RECT  10.515 48.731 10.797 49.171 ;
     RECT  6.84 49.171 6.858 49.195 ;
     RECT  7.815 48.299 8.154 49.199 ;
     RECT  10.515 49.171 11.43 49.229 ;
     RECT  6.768 49.195 6.858 49.441 ;
     RECT  2.34 48.989 2.697 49.513 ;
     RECT  6.768 49.441 6.93 49.675 ;
     RECT  10.515 49.229 10.797 49.711 ;
     RECT  6.156 49.675 6.93 49.739 ;
     RECT  11.952 49.675 11.97 49.739 ;
     RECT  4.608 48.929 5.397 49.855 ;
     RECT  10.404 49.711 10.797 49.891 ;
     RECT  2.34 49.513 2.862 49.915 ;
     RECT  9.036 48.695 9.234 49.981 ;
     RECT  9.972 49.891 10.797 49.981 ;
     RECT  4.392 49.855 5.397 50.009 ;
     RECT  2.304 49.915 2.862 50.053 ;
     RECT  6.552 49.739 6.93 50.117 ;
     RECT  9.036 49.981 10.797 50.153 ;
     RECT  5.115 50.009 5.397 50.161 ;
     RECT  11.988 49.981 12.006 50.189 ;
     RECT  2.304 50.053 2.898 50.279 ;
     RECT  6.552 50.117 6.894 50.279 ;
     RECT  3.996 50.125 4.014 50.315 ;
     RECT  9.036 50.153 9.054 50.431 ;
     RECT  8.82 50.431 9.054 50.549 ;
     RECT  6.732 50.279 6.894 50.717 ;
     RECT  5.115 50.161 5.706 50.819 ;
     RECT  9.864 50.153 10.797 50.935 ;
     RECT  4.068 50.899 4.086 50.999 ;
     RECT  9.144 50.935 10.797 51.089 ;
     RECT  6.876 50.717 6.894 51.241 ;
     RECT  7.815 49.199 8.097 51.241 ;
     RECT  6.876 51.241 8.097 51.359 ;
     RECT  9.36 51.089 10.797 51.511 ;
     RECT  5.115 50.819 5.397 51.601 ;
     RECT  6.264 51.511 6.858 51.629 ;
     RECT  9.36 51.511 10.89 51.629 ;
     RECT  2.304 50.279 2.862 51.899 ;
     RECT  9.36 51.629 9.378 51.899 ;
     RECT  7.815 51.359 8.097 52.051 ;
     RECT  6.84 51.629 6.858 52.219 ;
     RECT  5.04 51.601 5.397 52.285 ;
     RECT  6.84 52.219 6.93 52.321 ;
     RECT  5.04 52.285 5.922 52.411 ;
     RECT  6.84 52.321 7.002 52.411 ;
     RECT  5.04 52.411 7.002 52.511 ;
     RECT  7.815 52.051 8.586 52.555 ;
     RECT  4.032 52.555 4.05 52.709 ;
     RECT  10.515 51.629 10.797 52.825 ;
     RECT  7.815 52.555 9.234 52.861 ;
     RECT  5.115 52.511 7.002 52.889 ;
     RECT  7.815 52.861 9.378 52.979 ;
     RECT  6.588 52.889 7.002 52.987 ;
     RECT  7.815 52.979 8.097 52.987 ;
     RECT  6.588 52.987 8.097 53.024 ;
     RECT  6.588 53.024 6.894 53.249 ;
     RECT  11.952 50.635 11.97 53.249 ;
     RECT  9.288 52.979 9.378 53.401 ;
     RECT  10.116 52.825 10.797 53.401 ;
     RECT  6.588 53.249 6.858 53.429 ;
     RECT  5.115 52.889 5.814 53.491 ;
     RECT  9.288 53.401 10.797 53.491 ;
     RECT  9.288 53.491 11.43 53.549 ;
     RECT  6.588 53.429 6.75 53.555 ;
     RECT  2.304 51.899 2.697 53.563 ;
     RECT  5.076 53.491 5.814 53.563 ;
     RECT  5.004 53.563 5.814 53.635 ;
     RECT  4.896 53.635 5.814 53.671 ;
     RECT  2.304 53.563 2.862 53.789 ;
     RECT  4.896 53.671 6.246 53.789 ;
     RECT  9.288 53.549 10.797 53.789 ;
     RECT  7.815 53.024 8.097 53.941 ;
     RECT  6.228 53.789 6.246 54.059 ;
     RECT  9.828 53.789 10.797 54.131 ;
     RECT  9.036 54.175 9.054 54.329 ;
     RECT  7.632 53.941 8.097 54.481 ;
     RECT  4.896 53.789 5.397 54.607 ;
     RECT  4.572 54.607 5.397 54.653 ;
     RECT  4.716 54.653 5.397 54.869 ;
     RECT  7.524 54.481 8.097 54.869 ;
     RECT  2.304 53.789 2.697 54.949 ;
     RECT  2.304 54.949 2.862 54.985 ;
     RECT  9.864 54.131 10.797 54.985 ;
     RECT  6.264 54.715 6.282 55.021 ;
     RECT  11.952 53.995 11.97 55.049 ;
     RECT  5.004 54.869 5.397 55.111 ;
     RECT  6.264 55.021 6.462 55.111 ;
     RECT  3.852 55.021 3.87 55.175 ;
     RECT  5.004 55.111 6.462 55.247 ;
     RECT  2.304 54.985 2.898 55.255 ;
     RECT  9.648 54.985 10.797 55.255 ;
     RECT  7.815 54.869 8.097 55.291 ;
     RECT  9.36 55.255 10.797 55.291 ;
     RECT  5.004 55.247 6.282 55.409 ;
     RECT  7.815 55.291 10.797 55.409 ;
     RECT  5.004 55.409 5.397 55.445 ;
     RECT  11.988 55.111 12.006 55.469 ;
     RECT  2.304 55.255 3.114 55.553 ;
     RECT  2.415 55.553 3.114 55.679 ;
     RECT  9.504 55.409 10.797 55.679 ;
     RECT  9.504 55.679 9.594 55.949 ;
     RECT  0.108 55.795 0.126 55.997 ;
     RECT  6.264 55.409 6.282 56.101 ;
     RECT  5.115 55.445 5.397 56.191 ;
     RECT  6.264 56.101 6.822 56.191 ;
     RECT  9.576 55.949 9.594 56.219 ;
     RECT  5.115 56.191 6.822 56.335 ;
     RECT  7.815 55.409 8.097 56.371 ;
     RECT  2.415 55.679 2.697 56.395 ;
     RECT  4.716 56.335 6.822 56.489 ;
     RECT  2.304 56.395 2.697 56.569 ;
     RECT  4.716 56.489 6.498 56.597 ;
     RECT  10.515 55.679 10.797 56.731 ;
     RECT  7.815 56.371 8.622 56.759 ;
     RECT  11.952 55.912 11.97 56.759 ;
     RECT  2.304 56.569 2.826 56.875 ;
     RECT  12.852 56.875 12.87 57.029 ;
     RECT  10.152 56.731 10.797 57.145 ;
     RECT  7.815 56.759 8.097 57.181 ;
     RECT  8.82 56.875 9.234 57.181 ;
     RECT  10.08 57.145 10.797 57.181 ;
     RECT  8.82 57.181 10.797 57.271 ;
     RECT  2.304 56.875 2.862 57.299 ;
     RECT  4.824 56.597 6.498 57.299 ;
     RECT  7.632 57.181 8.097 57.299 ;
     RECT  4.824 57.299 5.706 57.415 ;
     RECT  6.48 57.299 6.498 57.451 ;
     RECT  4.572 57.415 5.706 57.569 ;
     RECT  6.48 57.451 6.642 57.569 ;
     RECT  6.48 57.569 6.498 57.581 ;
     RECT  8.82 57.271 11.43 57.869 ;
     RECT  7.815 57.299 8.097 57.991 ;
     RECT  8.82 57.869 10.797 57.991 ;
     RECT  7.815 57.991 10.797 58.109 ;
     RECT  7.815 58.109 8.766 58.379 ;
     RECT  9.792 58.109 10.797 58.379 ;
     RECT  2.304 57.299 2.697 58.495 ;
     RECT  4.824 57.569 5.706 58.507 ;
     RECT  6.624 58.495 6.642 58.507 ;
     RECT  4.824 58.507 6.642 58.685 ;
     RECT  4.824 58.685 5.397 58.765 ;
     RECT  6.12 58.685 6.642 58.919 ;
     RECT  2.304 58.495 2.754 59.035 ;
     RECT  11.952 58.315 11.97 59.161 ;
     RECT  2.304 59.035 3.294 59.189 ;
     RECT  4.788 58.765 5.397 59.305 ;
     RECT  9.864 58.379 10.797 59.305 ;
     RECT  11.952 59.161 12.006 59.309 ;
     RECT  6.84 59.227 6.858 59.333 ;
     RECT  7.815 58.379 8.73 59.539 ;
     RECT  9.576 59.305 10.797 59.539 ;
     RECT  7.815 59.539 10.797 59.611 ;
     RECT  7.74 59.611 11.43 59.729 ;
     RECT  4.68 59.305 5.397 59.737 ;
     RECT  7.815 59.729 9.666 59.765 ;
     RECT  10.44 59.729 11.43 59.789 ;
     RECT  2.304 59.189 2.862 59.999 ;
     RECT  4.356 59.737 5.397 60.035 ;
     RECT  2.304 59.999 2.697 60.173 ;
     RECT  9.54 59.765 9.666 60.413 ;
     RECT  9.54 60.413 9.558 60.539 ;
     RECT  6.516 60.235 6.786 60.547 ;
     RECT  6.516 60.547 6.858 60.575 ;
     RECT  4.5 60.035 5.397 60.691 ;
     RECT  6.66 60.575 6.858 60.719 ;
     RECT  4.5 60.691 5.454 60.809 ;
     RECT  11.952 60.232 11.97 60.809 ;
     RECT  4.716 60.809 5.397 60.845 ;
     RECT  2.376 60.173 2.697 60.925 ;
     RECT  10.44 59.789 10.797 60.925 ;
     RECT  2.232 60.925 2.697 61.085 ;
     RECT  10.404 60.925 10.797 61.189 ;
     RECT  10.404 61.189 10.854 61.195 ;
     RECT  10.08 61.195 10.854 61.229 ;
     RECT  9.216 61.195 9.234 61.321 ;
     RECT  10.08 61.229 10.797 61.321 ;
     RECT  3.528 61.195 3.546 61.349 ;
     RECT  7.815 59.765 8.262 61.429 ;
     RECT  9.216 61.321 10.797 61.429 ;
     RECT  6.66 60.719 6.786 61.501 ;
     RECT  7.815 61.429 10.797 61.619 ;
     RECT  6.408 61.501 6.786 61.627 ;
     RECT  6.264 61.627 6.786 61.655 ;
     RECT  2.304 61.085 2.697 61.664 ;
     RECT  11.988 61.321 12.006 61.709 ;
     RECT  2.376 61.664 2.697 61.735 ;
     RECT  7.815 61.619 8.478 61.889 ;
     RECT  9.288 61.619 10.797 62.159 ;
     RECT  9.432 62.159 10.797 62.231 ;
     RECT  9.432 62.231 9.45 62.429 ;
     RECT  2.376 61.735 2.934 62.437 ;
     RECT  5.115 60.845 5.397 62.539 ;
     RECT  2.304 62.437 2.934 62.545 ;
     RECT  6.264 61.655 6.39 62.545 ;
     RECT  6.264 62.545 6.534 62.573 ;
     RECT  2.304 62.545 3.078 62.581 ;
     RECT  5.115 62.539 5.454 62.581 ;
     RECT  6.516 62.573 6.534 62.581 ;
     RECT  6.516 62.581 6.678 62.621 ;
     RECT  2.304 62.581 3.438 62.699 ;
     RECT  6.66 62.621 6.678 62.699 ;
     RECT  3.42 62.699 3.438 62.735 ;
     RECT  5.115 62.581 5.742 63.121 ;
     RECT  9.252 63.085 9.27 63.211 ;
     RECT  4.968 63.121 5.742 63.247 ;
     RECT  7.815 61.889 8.097 63.247 ;
     RECT  9.252 63.211 9.486 63.247 ;
     RECT  4.788 63.247 5.742 63.355 ;
     RECT  7.815 63.247 9.486 63.355 ;
     RECT  10.515 62.231 10.797 63.355 ;
     RECT  4.572 63.355 5.742 63.391 ;
     RECT  4.572 63.391 5.814 63.509 ;
     RECT  7.815 63.355 10.797 63.509 ;
     RECT  4.572 63.509 5.598 63.545 ;
     RECT  4.572 63.545 5.397 63.779 ;
     RECT  11.952 62.107 11.97 63.779 ;
     RECT  6.66 63.739 6.678 63.815 ;
     RECT  9.468 63.509 10.797 64.021 ;
     RECT  9.468 64.021 11.43 64.061 ;
     RECT  6.84 64.165 6.858 64.201 ;
     RECT  6.84 64.201 7.002 64.205 ;
     RECT  6.984 64.205 7.002 64.499 ;
     RECT  4.32 64.471 4.338 64.589 ;
     RECT  7.815 63.509 8.622 64.589 ;
     RECT  5.115 63.779 5.397 64.699 ;
     RECT  5.115 64.699 5.886 64.741 ;
     RECT  9.468 64.061 10.797 64.741 ;
     RECT  4.14 64.705 4.158 64.859 ;
     RECT  5.115 64.741 6.03 64.859 ;
     RECT  7.815 64.589 8.298 65.129 ;
     RECT  11.952 64.507 11.97 65.129 ;
     RECT  6.588 65.131 6.642 65.281 ;
     RECT  9.432 64.741 10.797 65.371 ;
     RECT  6.588 65.281 6.786 65.399 ;
     RECT  2.304 62.699 2.697 65.515 ;
     RECT  9.432 65.371 11.43 65.515 ;
     RECT  2.304 65.515 3.402 65.669 ;
     RECT  7.815 65.129 8.097 65.821 ;
     RECT  9.288 65.515 11.43 65.981 ;
     RECT  9.288 65.981 10.797 66.119 ;
     RECT  5.115 64.859 5.397 66.139 ;
     RECT  6.588 65.399 6.606 66.139 ;
     RECT  5.115 66.139 6.606 66.479 ;
     RECT  10.26 66.119 10.797 66.551 ;
     RECT  2.304 65.669 2.862 66.595 ;
     RECT  7.776 65.821 8.097 66.631 ;
     RECT  2.304 66.595 3.402 66.749 ;
     RECT  9.288 66.119 9.486 66.749 ;
     RECT  2.304 66.749 2.718 67.019 ;
     RECT  3.636 66.901 3.654 67.055 ;
     RECT  5.115 66.479 5.886 67.277 ;
     RECT  6.804 66.631 8.097 67.277 ;
     RECT  7.524 67.277 8.097 67.531 ;
     RECT  11.952 66.427 11.97 67.567 ;
     RECT  10.515 66.551 10.797 67.675 ;
     RECT  7.524 67.531 8.478 67.711 ;
     RECT  9.288 66.749 9.306 67.711 ;
     RECT  10.188 67.675 10.797 67.711 ;
     RECT  5.115 67.277 5.67 67.801 ;
     RECT  6.444 67.711 6.75 67.829 ;
     RECT  7.524 67.711 8.55 67.829 ;
     RECT  9.288 67.711 10.797 67.829 ;
     RECT  11.952 67.567 12.006 67.901 ;
     RECT  4.572 67.801 5.67 67.945 ;
     RECT  4.284 67.945 5.67 68.099 ;
     RECT  6.732 67.829 6.75 68.099 ;
     RECT  9.828 67.829 10.797 68.341 ;
     RECT  4.464 68.099 5.634 68.369 ;
     RECT  9.828 68.341 11.43 68.381 ;
     RECT  9.828 68.381 10.797 68.611 ;
     RECT  6.696 68.587 6.714 68.639 ;
     RECT  7.815 67.829 8.154 68.791 ;
     RECT  9.252 68.611 10.797 68.791 ;
     RECT  5.115 68.369 5.634 68.881 ;
     RECT  3.492 68.755 3.51 68.909 ;
     RECT  7.815 68.791 10.797 68.909 ;
     RECT  4.032 69.151 4.23 69.251 ;
     RECT  9.036 68.909 10.797 69.251 ;
     RECT  5.115 68.881 5.706 69.331 ;
     RECT  4.032 69.251 4.05 69.449 ;
     RECT  5.115 69.331 5.778 69.691 ;
     RECT  5.115 69.691 6.426 69.871 ;
     RECT  2.304 67.019 2.697 69.965 ;
     RECT  5.115 69.871 6.57 69.989 ;
     RECT  7.815 68.909 8.097 70.069 ;
     RECT  9.18 69.251 10.797 70.069 ;
     RECT  5.115 69.989 6.426 70.157 ;
     RECT  7.815 70.069 10.797 70.259 ;
     RECT  9.216 70.259 10.797 70.261 ;
     RECT  11.952 68.827 11.97 70.261 ;
     RECT  9.216 70.261 11.97 70.301 ;
     RECT  9.216 70.301 10.797 70.331 ;
     RECT  5.115 70.157 6.318 70.645 ;
     RECT  11.988 70.501 12.006 70.781 ;
     RECT  4.68 70.645 6.318 70.799 ;
     RECT  2.415 69.965 2.697 70.843 ;
     RECT  5.115 70.799 6.318 70.951 ;
     RECT  5.115 70.951 6.858 71.069 ;
     RECT  2.34 70.843 2.697 71.185 ;
     RECT  7.815 70.259 8.226 71.221 ;
     RECT  2.34 71.185 2.862 71.323 ;
     RECT  9.216 70.331 9.234 71.491 ;
     RECT  10.008 70.331 10.797 71.491 ;
     RECT  5.115 71.069 6.246 71.581 ;
     RECT  5.076 71.581 6.246 71.725 ;
     RECT  9.216 71.491 10.797 71.761 ;
     RECT  4.572 71.725 6.246 71.851 ;
     RECT  2.304 71.323 2.862 71.879 ;
     RECT  4.572 71.851 6.858 71.888 ;
     RECT  4.572 71.888 6.246 71.951 ;
     RECT  7.815 71.221 8.298 72.031 ;
     RECT  9.072 71.761 10.797 72.031 ;
     RECT  4.572 71.951 5.778 72.149 ;
     RECT  7.815 72.031 10.797 72.149 ;
     RECT  5.115 72.149 5.778 72.185 ;
     RECT  8.856 72.149 10.797 72.185 ;
     RECT  9.072 72.185 10.797 72.221 ;
     RECT  11.952 71.227 11.97 72.221 ;
     RECT  5.115 72.185 5.706 72.419 ;
     RECT  4.104 72.391 4.122 72.491 ;
     RECT  9.36 72.221 10.797 72.661 ;
     RECT  3.924 72.535 3.942 72.689 ;
     RECT  9.36 72.661 11.43 72.689 ;
     RECT  9.468 72.689 11.43 72.701 ;
     RECT  6.516 72.667 6.534 72.725 ;
     RECT  7.815 72.149 8.097 72.931 ;
     RECT  6.66 72.841 6.678 72.959 ;
     RECT  3.744 73.075 3.762 73.229 ;
     RECT  7.815 72.931 8.55 73.229 ;
     RECT  9.468 72.701 10.797 73.229 ;
     RECT  5.115 72.419 5.397 73.381 ;
     RECT  5.115 73.381 5.562 73.499 ;
     RECT  5.115 73.499 5.526 73.531 ;
     RECT  10.224 73.229 10.797 73.627 ;
     RECT  11.952 73.147 11.97 73.627 ;
     RECT  2.304 71.879 2.697 73.805 ;
     RECT  2.415 73.805 2.697 73.849 ;
     RECT  5.04 73.531 5.526 73.921 ;
     RECT  9.468 73.229 9.486 74.011 ;
     RECT  10.224 73.627 11.97 74.011 ;
     RECT  9.468 74.011 11.97 74.047 ;
     RECT  4.716 73.921 5.526 74.093 ;
     RECT  9.216 74.047 12.006 74.141 ;
     RECT  9.216 74.141 11.43 74.281 ;
     RECT  2.415 73.849 2.898 74.425 ;
     RECT  7.815 73.229 8.097 74.425 ;
     RECT  9.18 74.281 11.43 74.425 ;
     RECT  2.415 74.425 3.402 74.461 ;
     RECT  5.115 74.093 5.526 74.461 ;
     RECT  6.3 73.531 6.318 74.461 ;
     RECT  2.415 74.461 3.582 74.579 ;
     RECT  5.115 74.461 6.318 74.579 ;
     RECT  7.815 74.425 11.43 74.579 ;
     RECT  2.415 74.579 2.697 74.587 ;
     RECT  3.564 74.579 3.582 74.615 ;
     RECT  10.26 74.579 11.43 74.621 ;
     RECT  6.516 74.731 6.534 74.849 ;
     RECT  5.115 74.579 5.397 74.929 ;
     RECT  4.608 74.929 5.397 75.115 ;
     RECT  9.144 74.579 9.45 75.119 ;
     RECT  4.356 75.115 5.397 75.155 ;
     RECT  4.5 75.155 5.397 75.355 ;
     RECT  4.5 75.355 5.67 75.461 ;
     RECT  2.304 74.587 2.697 75.505 ;
     RECT  5.115 75.461 5.67 75.541 ;
     RECT  5.115 75.541 5.814 75.659 ;
     RECT  2.304 75.505 2.862 75.775 ;
     RECT  10.26 74.621 10.797 75.901 ;
     RECT  2.304 75.775 3.33 75.929 ;
     RECT  9.144 75.119 9.162 76.045 ;
     RECT  9.144 76.045 9.306 76.081 ;
     RECT  3.816 76.045 3.978 76.199 ;
     RECT  5.115 75.659 5.778 76.199 ;
     RECT  11.952 75.067 11.97 76.199 ;
     RECT  3.96 76.199 3.978 76.235 ;
     RECT  10.152 75.901 10.797 76.315 ;
     RECT  8.928 76.081 9.306 76.351 ;
     RECT  10.116 76.315 10.797 76.351 ;
     RECT  8.856 76.351 10.797 76.441 ;
     RECT  8.856 76.441 11.43 76.469 ;
     RECT  2.304 75.929 2.697 76.855 ;
     RECT  5.115 76.199 5.706 76.891 ;
     RECT  2.304 76.855 2.862 77.009 ;
     RECT  9.288 76.469 11.43 77.009 ;
     RECT  9.972 77.009 11.43 77.021 ;
     RECT  4.896 76.891 5.706 77.045 ;
     RECT  7.815 74.579 8.097 77.161 ;
     RECT  5.04 77.045 5.706 77.227 ;
     RECT  7.092 77.161 8.097 77.279 ;
     RECT  5.04 77.227 6.174 77.431 ;
     RECT  5.04 77.431 6.93 77.549 ;
     RECT  9.972 77.021 10.797 77.549 ;
     RECT  3.816 77.665 3.834 77.819 ;
     RECT  5.04 77.549 6.858 77.855 ;
     RECT  4.032 77.935 4.05 77.971 ;
     RECT  5.04 77.855 5.778 77.971 ;
     RECT  4.032 77.971 5.778 78.089 ;
     RECT  6.516 77.855 6.858 78.089 ;
     RECT  9.072 77.791 9.09 78.475 ;
     RECT  9.072 78.475 9.306 78.511 ;
     RECT  11.952 77.467 11.97 78.539 ;
     RECT  4.572 78.089 5.778 78.629 ;
     RECT  8.928 78.511 9.306 78.637 ;
     RECT  10.152 77.549 10.797 78.637 ;
     RECT  6.516 78.089 6.678 78.653 ;
     RECT  5.115 78.629 5.778 78.781 ;
     RECT  6.66 78.653 6.678 78.899 ;
     RECT  8.928 78.637 10.797 78.899 ;
     RECT  11.988 78.601 12.006 78.941 ;
     RECT  5.115 78.781 5.922 79.079 ;
     RECT  4.356 79.015 4.374 79.243 ;
     RECT  9.432 78.899 10.797 79.439 ;
     RECT  9.54 79.439 10.797 79.511 ;
     RECT  4.32 79.243 4.374 79.555 ;
     RECT  3.816 79.555 4.374 79.591 ;
     RECT  5.115 79.079 5.397 79.591 ;
     RECT  3.816 79.591 5.397 79.709 ;
     RECT  9.54 79.511 9.558 79.709 ;
     RECT  2.304 77.009 2.697 79.745 ;
     RECT  3.996 79.709 4.014 79.745 ;
     RECT  7.815 77.279 8.097 79.753 ;
     RECT  4.896 79.709 5.397 79.963 ;
     RECT  7.776 79.753 8.097 79.979 ;
     RECT  4.896 79.963 5.922 80.131 ;
     RECT  4.896 80.131 6.102 80.249 ;
     RECT  4.896 80.249 5.418 80.519 ;
     RECT  6.66 80.491 6.858 80.527 ;
     RECT  6.66 80.527 6.93 80.555 ;
     RECT  10.515 79.511 10.797 80.599 ;
     RECT  11.952 79.387 11.97 80.599 ;
     RECT  2.415 79.745 2.697 80.635 ;
     RECT  7.815 79.979 8.097 80.635 ;
     RECT  10.515 80.599 11.97 80.635 ;
     RECT  2.304 80.635 3.402 80.671 ;
     RECT  4.896 80.519 5.397 80.671 ;
     RECT  9.216 80.257 9.234 80.671 ;
     RECT  10.188 80.635 11.97 80.671 ;
     RECT  6.84 80.555 6.93 80.699 ;
     RECT  9.216 80.671 11.97 80.699 ;
     RECT  4.752 80.671 5.397 80.789 ;
     RECT  7.815 80.635 8.298 80.789 ;
     RECT  2.304 80.671 3.582 80.825 ;
     RECT  2.304 80.825 3.114 81.059 ;
     RECT  9.216 80.699 11.43 81.059 ;
     RECT  4.824 80.789 5.397 81.259 ;
     RECT  4.824 81.259 5.562 81.301 ;
     RECT  4.824 81.301 5.85 81.341 ;
     RECT  10.515 81.059 11.43 81.341 ;
     RECT  9.216 81.059 9.486 81.445 ;
     RECT  6.84 80.699 6.858 81.599 ;
     RECT  10.515 81.341 10.797 81.841 ;
     RECT  6.264 81.751 6.822 81.869 ;
     RECT  11.952 81.787 11.97 81.869 ;
     RECT  6.732 81.869 6.822 81.905 ;
     RECT  9.18 81.445 9.486 81.941 ;
     RECT  10.26 81.841 10.797 81.941 ;
     RECT  4.824 81.341 5.526 81.985 ;
     RECT  4.716 81.985 5.526 82.021 ;
     RECT  6.804 81.905 6.822 82.139 ;
     RECT  4.644 82.021 5.526 82.211 ;
     RECT  10.44 81.941 10.797 82.255 ;
     RECT  10.44 82.255 11.43 82.301 ;
     RECT  2.304 81.059 2.862 82.409 ;
     RECT  9 82.255 9.018 82.409 ;
     RECT  7.815 80.789 8.097 82.561 ;
     RECT  11.952 82.747 11.97 82.787 ;
     RECT  10.44 82.301 10.797 82.795 ;
     RECT  3.708 82.795 3.726 82.831 ;
     RECT  5.115 82.211 5.526 82.831 ;
     RECT  3.708 82.831 3.906 82.949 ;
     RECT  3.888 82.949 3.906 82.985 ;
     RECT  9.252 82.921 9.27 83.065 ;
     RECT  10.116 82.795 10.797 83.065 ;
     RECT  5.115 82.831 5.67 83.191 ;
     RECT  7.815 82.561 8.514 83.219 ;
     RECT  11.988 83.191 12.006 83.261 ;
     RECT  4.824 83.191 5.67 83.335 ;
     RECT  9.252 83.065 10.797 83.371 ;
     RECT  4.14 83.335 5.67 83.489 ;
     RECT  9.216 83.371 10.797 83.489 ;
     RECT  4.284 83.489 5.67 83.641 ;
     RECT  4.284 83.641 5.814 83.731 ;
     RECT  4.284 83.731 6.246 83.759 ;
     RECT  9.468 83.489 10.797 83.759 ;
     RECT  4.5 83.759 6.246 83.789 ;
     RECT  4.5 83.789 5.418 83.795 ;
     RECT  6.228 83.789 6.246 84.029 ;
     RECT  10.296 83.759 10.797 84.029 ;
     RECT  9.468 83.759 9.486 84.065 ;
     RECT  4.572 83.795 5.418 84.209 ;
     RECT  4.572 84.209 5.397 84.571 ;
     RECT  4.392 84.571 5.397 84.685 ;
     RECT  9.396 84.685 9.414 84.721 ;
     RECT  9.036 84.721 9.414 84.811 ;
     RECT  4.032 84.685 5.397 84.839 ;
     RECT  4.212 84.839 4.302 84.875 ;
     RECT  6.624 84.847 6.642 84.883 ;
     RECT  6.624 84.883 6.786 84.893 ;
     RECT  9.036 84.811 9.486 84.955 ;
     RECT  10.515 84.029 10.797 84.955 ;
     RECT  6.768 84.893 6.786 85.109 ;
     RECT  9.036 84.955 10.797 85.109 ;
     RECT  9.468 85.109 10.797 85.145 ;
     RECT  4.284 84.875 4.302 85.289 ;
     RECT  9.828 85.145 10.797 85.621 ;
     RECT  11.952 83.707 11.97 85.621 ;
     RECT  9.828 85.621 11.97 85.649 ;
     RECT  5.115 84.839 5.397 85.657 ;
     RECT  9.972 85.649 11.97 85.661 ;
     RECT  4.896 85.657 5.397 85.765 ;
     RECT  4.896 85.765 5.994 85.801 ;
     RECT  9.972 85.661 10.797 85.919 ;
     RECT  2.304 82.409 2.697 86.035 ;
     RECT  4.896 85.801 6.138 86.035 ;
     RECT  11.988 85.891 12.006 86.141 ;
     RECT  2.304 86.035 3.33 86.189 ;
     RECT  4.5 86.035 6.138 86.189 ;
     RECT  4.5 86.189 5.598 86.225 ;
     RECT  7.815 83.219 8.097 86.341 ;
     RECT  7.815 86.341 8.802 86.459 ;
     RECT  4.5 86.225 5.397 86.611 ;
     RECT  3.996 86.611 5.397 86.729 ;
     RECT  11.952 86.587 11.97 87.179 ;
     RECT  2.304 86.189 2.862 87.269 ;
     RECT  6.624 87.259 6.642 87.277 ;
     RECT  6.588 87.277 6.642 87.421 ;
     RECT  8.928 87.115 9.27 87.421 ;
     RECT  10.116 85.919 10.797 87.421 ;
     RECT  4.464 86.729 5.397 87.511 ;
     RECT  8.928 87.421 11.43 87.539 ;
     RECT  9.288 87.539 11.43 87.581 ;
     RECT  4.392 87.511 5.397 87.611 ;
     RECT  2.304 87.269 2.697 87.629 ;
     RECT  9.288 87.581 10.797 87.719 ;
     RECT  9.288 87.719 9.486 88.079 ;
     RECT  10.26 87.719 10.797 88.151 ;
     RECT  5.115 87.611 5.397 88.231 ;
     RECT  6.588 87.421 6.786 88.231 ;
     RECT  5.115 88.231 5.706 88.349 ;
     RECT  6.588 88.231 6.858 88.349 ;
     RECT  9.468 88.079 9.486 88.349 ;
     RECT  4.14 88.321 4.158 88.465 ;
     RECT  5.115 88.349 5.67 88.465 ;
     RECT  2.34 87.629 2.697 88.507 ;
     RECT  3.42 88.465 5.67 88.619 ;
     RECT  3.42 88.619 4.158 88.655 ;
     RECT  5.076 88.619 5.67 88.889 ;
     RECT  7.815 86.459 8.097 88.897 ;
     RECT  10.515 88.151 10.797 88.987 ;
     RECT  11.952 88.027 11.97 88.987 ;
     RECT  2.304 88.507 2.697 89.005 ;
     RECT  3.42 88.655 3.618 89.005 ;
     RECT  5.076 88.889 5.526 89.069 ;
     RECT  5.076 89.069 5.49 89.159 ;
     RECT  10.515 88.987 11.97 89.159 ;
     RECT  2.304 89.005 3.618 89.195 ;
     RECT  9.396 89.005 9.414 89.275 ;
     RECT  10.515 89.159 10.797 89.275 ;
     RECT  2.304 89.195 3.546 89.429 ;
     RECT  5.115 89.159 5.49 89.429 ;
     RECT  7.815 88.897 8.154 89.429 ;
     RECT  3.528 89.429 3.546 89.465 ;
     RECT  11.952 89.159 11.97 89.699 ;
     RECT  9.396 89.275 10.797 89.815 ;
     RECT  9.252 89.815 10.797 89.941 ;
     RECT  9.252 89.941 11.43 89.981 ;
     RECT  9.252 89.981 10.797 90.041 ;
     RECT  6.264 89.899 6.282 90.121 ;
     RECT  6.192 90.121 6.282 90.211 ;
     RECT  8.892 90.121 8.91 90.239 ;
     RECT  5.115 89.429 5.397 90.391 ;
     RECT  6.192 90.211 6.498 90.391 ;
     RECT  2.304 89.429 2.697 90.481 ;
     RECT  5.115 90.391 6.642 90.545 ;
     RECT  2.304 90.481 2.862 90.581 ;
     RECT  3.924 90.895 3.942 90.931 ;
     RECT  7.815 89.429 8.097 90.931 ;
     RECT  3.924 90.931 4.122 91.049 ;
     RECT  4.104 91.049 4.122 91.085 ;
     RECT  6.408 90.545 6.642 91.201 ;
     RECT  7.815 90.931 8.298 91.201 ;
     RECT  10.296 90.041 10.797 91.201 ;
     RECT  6.408 91.201 6.786 91.319 ;
     RECT  7.815 91.201 8.37 91.319 ;
     RECT  9.9 91.201 10.797 91.435 ;
     RECT  5.115 90.545 5.397 91.471 ;
     RECT  6.408 91.319 6.498 91.471 ;
     RECT  9.576 91.435 10.797 91.471 ;
     RECT  11.952 90.427 11.97 91.499 ;
     RECT  5.04 91.471 6.498 91.589 ;
     RECT  2.304 90.581 2.697 91.705 ;
     RECT  5.04 91.589 5.706 91.741 ;
     RECT  4.896 91.741 5.706 91.859 ;
     RECT  8.856 91.471 10.797 91.895 ;
     RECT  11.988 91.561 12.006 91.901 ;
     RECT  9.072 91.895 10.797 91.931 ;
     RECT  9.36 91.931 10.797 92.129 ;
     RECT  4.896 91.859 5.49 92.281 ;
     RECT  6.48 91.589 6.498 92.281 ;
     RECT  4.824 92.281 5.49 92.399 ;
     RECT  6.48 92.281 6.858 92.399 ;
     RECT  4.824 92.399 5.397 92.435 ;
     RECT  10.44 92.129 10.797 92.471 ;
     RECT  2.304 91.705 2.97 92.551 ;
     RECT  9.36 92.129 9.486 92.579 ;
     RECT  6.48 92.399 6.678 92.669 ;
     RECT  2.304 92.551 3.042 92.705 ;
     RECT  5.115 92.435 5.397 93.163 ;
     RECT  2.304 92.705 2.898 93.281 ;
     RECT  10.515 92.471 10.797 93.325 ;
     RECT  4.536 93.163 5.397 93.361 ;
     RECT  9.288 93.055 9.306 93.361 ;
     RECT  11.952 92.347 11.97 93.389 ;
     RECT  6.48 92.669 6.498 93.485 ;
     RECT  3.852 93.361 5.397 93.515 ;
     RECT  4.248 93.515 5.397 93.631 ;
     RECT  8.928 93.361 9.306 93.631 ;
     RECT  10.296 93.325 10.797 93.631 ;
     RECT  4.248 93.631 5.742 93.749 ;
     RECT  8.928 93.631 10.797 93.749 ;
     RECT  11.988 93.451 12.006 93.773 ;
     RECT  4.248 93.749 5.397 93.785 ;
     RECT  9.216 93.749 10.797 94.019 ;
     RECT  10.26 94.019 10.797 94.361 ;
     RECT  2.304 93.281 2.697 94.369 ;
     RECT  2.304 94.369 2.862 94.405 ;
     RECT  2.304 94.405 3.294 94.441 ;
     RECT  6.3 94.405 6.462 94.445 ;
     RECT  4.86 93.785 5.397 94.559 ;
     RECT  6.444 94.445 6.462 94.559 ;
     RECT  2.304 94.441 3.978 94.595 ;
     RECT  2.304 94.595 3.726 94.631 ;
     RECT  0.108 94.603 0.126 94.733 ;
     RECT  9.216 94.019 9.342 94.981 ;
     RECT  11.952 94.219 11.97 95.071 ;
     RECT  9.216 94.981 9.666 95.107 ;
     RECT  10.515 94.361 10.797 95.107 ;
     RECT  7.815 91.319 8.097 95.143 ;
     RECT  5.112 94.559 5.397 95.165 ;
     RECT  2.304 94.631 2.862 95.171 ;
     RECT  11.952 95.071 12.006 95.213 ;
     RECT  5.115 95.165 5.397 95.227 ;
     RECT  3.708 94.631 3.726 95.485 ;
     RECT  5.115 95.227 5.562 95.521 ;
     RECT  9.216 95.107 10.797 95.521 ;
     RECT  3.42 95.485 3.726 95.639 ;
     RECT  7.815 95.143 8.154 95.639 ;
     RECT  9.216 95.521 11.43 95.639 ;
     RECT  10.404 95.639 11.43 95.693 ;
     RECT  3.636 95.639 3.726 96.061 ;
     RECT  7.815 95.639 8.097 96.061 ;
     RECT  3.636 96.061 3.87 96.179 ;
     RECT  7.38 96.061 8.097 96.179 ;
     RECT  9.288 95.639 9.486 96.179 ;
     RECT  3.852 96.179 3.87 96.215 ;
     RECT  10.404 95.693 10.797 96.323 ;
     RECT  5.115 95.521 5.67 96.421 ;
     RECT  4.392 96.421 5.67 96.601 ;
     RECT  4.392 96.601 5.706 96.955 ;
     RECT  4.392 96.955 5.994 96.997 ;
     RECT  4.248 96.997 5.994 97.105 ;
     RECT  9.468 96.179 9.486 97.105 ;
     RECT  9.468 97.105 9.558 97.141 ;
     RECT  4.248 97.105 6.138 97.169 ;
     RECT  2.304 95.171 2.697 97.375 ;
     RECT  9 97.141 9.558 97.375 ;
     RECT  10.515 96.323 10.797 97.375 ;
     RECT  2.304 97.375 2.862 97.529 ;
     RECT  4.5 97.169 6.138 97.529 ;
     RECT  4.5 97.529 5.562 97.565 ;
     RECT  9 97.375 10.797 97.565 ;
     RECT  11.952 96.139 11.97 97.799 ;
     RECT  9.036 97.565 10.797 98.059 ;
     RECT  5.115 97.565 5.562 98.069 ;
     RECT  9.036 98.059 11.394 98.069 ;
     RECT  3.42 97.951 3.438 98.105 ;
     RECT  9.828 98.069 11.394 98.339 ;
     RECT  5.115 98.069 5.397 98.491 ;
     RECT  6.444 98.299 6.462 98.491 ;
     RECT  6.444 98.491 6.642 98.609 ;
     RECT  4.572 98.491 5.397 98.645 ;
     RECT  2.304 97.529 2.697 98.851 ;
     RECT  9.828 98.339 10.797 98.851 ;
     RECT  2.304 98.851 3.33 99.031 ;
     RECT  6.444 98.609 6.57 99.149 ;
     RECT  2.304 99.031 3.546 99.185 ;
     RECT  5.115 98.645 5.397 99.391 ;
     RECT  5.076 99.391 5.397 99.44 ;
     RECT  9.396 98.851 10.797 99.535 ;
     RECT  7.815 96.179 8.097 99.571 ;
     RECT  9.216 99.535 10.797 99.571 ;
     RECT  6.444 99.149 6.462 99.581 ;
     RECT  11.952 98.539 11.97 99.599 ;
     RECT  2.304 99.185 3.15 99.725 ;
     RECT  9.144 99.571 10.797 99.725 ;
     RECT  9.216 99.725 10.797 99.959 ;
     RECT  11.988 99.661 12.006 100.013 ;
     RECT  5.076 99.44 5.598 100.201 ;
     RECT  5.004 100.201 5.706 100.459 ;
     RECT  9.288 99.959 10.797 100.499 ;
     RECT  7.815 99.571 8.154 100.571 ;
     RECT  4.356 100.459 5.706 100.615 ;
     RECT  9.54 100.499 10.797 100.679 ;
     RECT  3.708 100.615 5.706 100.769 ;
     RECT  3.888 100.769 5.397 100.805 ;
     RECT  4.392 100.805 5.397 101.111 ;
     RECT  6.84 101.011 6.858 101.309 ;
     RECT  11.952 100.459 11.97 101.309 ;
     RECT  9.864 100.679 10.797 101.425 ;
     RECT  12.852 101.419 12.87 101.579 ;
     RECT  4.608 101.111 5.397 101.731 ;
     RECT  9.072 101.425 10.797 101.731 ;
     RECT  6.48 101.467 6.75 101.849 ;
     RECT  4.608 101.731 5.562 101.885 ;
     RECT  9 101.731 10.797 101.893 ;
     RECT  2.304 99.725 2.697 101.965 ;
     RECT  4.608 101.885 5.397 102.001 ;
     RECT  9 101.893 11.43 102.271 ;
     RECT  8.928 102.271 11.43 102.361 ;
     RECT  4.572 102.001 5.397 102.379 ;
     RECT  8.856 102.361 11.43 102.389 ;
     RECT  9.864 102.389 11.43 102.413 ;
     RECT  8.856 102.389 8.982 102.461 ;
     RECT  2.304 101.965 2.862 102.505 ;
     RECT  4.356 102.379 5.397 102.541 ;
     RECT  2.304 102.505 3.222 102.659 ;
     RECT  3.96 102.541 5.397 102.659 ;
     RECT  3.96 102.659 3.978 102.695 ;
     RECT  6.48 101.849 6.498 102.901 ;
     RECT  9.864 102.413 10.797 102.929 ;
     RECT  3.744 102.901 3.762 103.001 ;
     RECT  6.228 102.901 6.498 103.081 ;
     RECT  6.228 103.081 6.57 103.199 ;
     RECT  8.964 102.461 8.982 103.199 ;
     RECT  5.115 102.659 5.397 103.441 ;
     RECT  5.115 103.441 5.49 103.477 ;
     RECT  7.815 100.571 8.097 103.549 ;
     RECT  6.552 103.199 6.57 103.585 ;
     RECT  7.815 103.549 8.694 103.621 ;
     RECT  4.572 103.477 5.49 103.723 ;
     RECT  7.524 103.621 8.694 103.739 ;
     RECT  4.464 103.723 5.49 103.775 ;
     RECT  9.468 103.585 9.558 103.811 ;
     RECT  4.464 103.775 5.397 103.855 ;
     RECT  9.54 103.811 9.558 103.891 ;
     RECT  10.515 102.929 10.797 103.891 ;
     RECT  4.032 103.855 5.397 104.009 ;
     RECT  11.952 102.859 11.97 104.009 ;
     RECT  4.392 104.009 5.397 104.045 ;
     RECT  7.815 103.739 8.694 104.279 ;
     RECT  9.54 103.891 10.797 104.279 ;
     RECT  2.304 102.659 2.697 104.287 ;
     RECT  11.988 104.161 12.006 104.333 ;
     RECT  6.552 103.585 6.714 104.431 ;
     RECT  2.304 104.287 2.862 104.549 ;
     RECT  2.304 104.549 2.718 104.585 ;
     RECT  4.572 104.045 5.397 104.585 ;
     RECT  6.408 104.431 6.822 104.827 ;
     RECT  6.228 104.827 6.822 105.089 ;
     RECT  9.144 104.791 9.486 105.125 ;
     RECT  10.26 104.279 10.797 105.125 ;
     RECT  10.296 105.125 10.797 105.197 ;
     RECT  7.815 104.279 8.097 105.205 ;
     RECT  9.468 105.125 9.486 105.241 ;
     RECT  10.515 105.197 10.797 105.241 ;
     RECT  11.952 104.779 11.97 105.241 ;
     RECT  10.515 105.241 11.97 105.293 ;
     RECT  2.415 104.585 2.718 105.307 ;
     RECT  5.004 104.585 5.397 105.331 ;
     RECT  7.02 105.241 7.038 105.331 ;
     RECT  7.815 105.205 8.73 105.331 ;
     RECT  7.02 105.331 8.73 105.359 ;
     RECT  9.468 105.241 9.558 105.359 ;
     RECT  2.304 105.307 2.718 105.403 ;
     RECT  4.032 105.331 5.397 105.431 ;
     RECT  6.228 105.089 6.246 105.431 ;
     RECT  5.115 105.431 5.397 105.587 ;
     RECT  7.092 105.359 8.097 105.587 ;
     RECT  10.515 105.293 10.797 105.587 ;
     RECT  2.304 105.403 2.862 105.629 ;
     RECT  7.092 105.587 7.905 105.629 ;
     RECT  4.032 105.431 4.23 105.665 ;
     RECT  5.115 105.587 5.382 105.677 ;
     RECT  4.212 105.665 4.23 105.701 ;
     RECT  2.304 105.629 2.505 105.773 ;
     RECT  11.988 105.331 12.006 105.773 ;
     RECT  2.415 105.773 2.505 105.857 ;
     RECT  5.115 105.677 5.205 105.857 ;
     RECT  7.815 105.629 7.905 105.857 ;
     RECT  10.515 105.587 10.605 105.857 ;
    LAYER M4 ;
     RECT  0.06 5.232 0.137 105.768 ;
     RECT  0.137 5.664 0.227 105.768 ;
     RECT  0.227 5.664 0.323 58.68 ;
     RECT  0.323 5.664 2.408 14.808 ;
     RECT  0.323 15.936 2.408 58.68 ;
     RECT  0.227 59.664 2.408 105.768 ;
     RECT  2.408 2.148 2.512 105.852 ;
     RECT  2.512 2.418 2.704 105.582 ;
     RECT  2.704 27.12 2.765 27.144 ;
     RECT  4.268 79.632 4.309 79.656 ;
     RECT  4.345 100.464 4.357 100.488 ;
     RECT  4.309 86.448 4.549 86.472 ;
     RECT  4.357 73.968 4.705 73.992 ;
     RECT  4.561 30.72 4.94 30.744 ;
     RECT  4.777 32.256 4.94 32.28 ;
     RECT  4.345 59.76 4.981 59.784 ;
     RECT  4.705 73.968 4.981 74.088 ;
     RECT  4.549 94.272 4.981 94.296 ;
     RECT  5.065 6.672 5.108 6.888 ;
     RECT  4.94 30.72 5.108 32.28 ;
     RECT  4.525 44.832 5.108 44.856 ;
     RECT  4.597 47.232 5.108 47.256 ;
     RECT  4.525 48.384 5.108 48.408 ;
     RECT  4.597 50.112 5.108 50.136 ;
     RECT  2.704 52.8 5.108 52.824 ;
     RECT  4.556 54.624 5.108 54.648 ;
     RECT  4.597 56.64 5.108 56.664 ;
     RECT  4.981 59.76 5.108 60.696 ;
     RECT  4.949 71.76 5.108 71.784 ;
     RECT  4.981 73.536 5.108 74.088 ;
     RECT  4.316 75.12 5.108 75.144 ;
     RECT  4.309 79.248 5.108 79.656 ;
     RECT  4.309 84.576 5.108 84.6 ;
     RECT  4.549 86.448 5.108 87.144 ;
     RECT  4.453 88.512 5.108 88.536 ;
     RECT  4.508 93.168 5.108 93.192 ;
     RECT  4.981 94.272 5.108 95.16 ;
     RECT  4.981 97.392 5.108 97.416 ;
     RECT  4.357 100.464 5.108 101.016 ;
     RECT  4.316 102.384 5.108 102.408 ;
     RECT  4.357 103.728 5.108 103.752 ;
     RECT  5.108 2.148 5.212 105.852 ;
     RECT  5.212 2.418 5.404 105.672 ;
     RECT  5.404 6 5.555 9 ;
     RECT  5.404 15.36 5.555 16.104 ;
     RECT  5.404 18.528 5.555 18.552 ;
     RECT  5.404 83.184 5.555 83.784 ;
     RECT  5.404 85.776 5.555 86.04 ;
     RECT  5.404 92.256 5.555 92.28 ;
     RECT  5.404 96.576 5.555 98.328 ;
     RECT  5.404 93.456 5.573 95.256 ;
     RECT  5.404 38.784 5.581 38.808 ;
     RECT  5.404 88.32 5.581 88.872 ;
     RECT  5.404 10.032 5.596 10.248 ;
     RECT  5.555 96.576 5.596 96.984 ;
     RECT  5.404 12.528 5.603 13.032 ;
     RECT  5.404 3.408 5.609 3.432 ;
     RECT  5.404 99.456 5.609 100.296 ;
     RECT  5.404 20.88 5.616 20.904 ;
     RECT  5.596 10.224 5.617 10.248 ;
     RECT  5.404 45.312 5.651 45.912 ;
     RECT  5.404 47.856 5.651 48.36 ;
     RECT  5.404 49.68 5.651 50.232 ;
     RECT  5.404 69.36 5.651 70.152 ;
     RECT  5.404 73.248 5.651 74.28 ;
     RECT  5.609 99.552 5.651 100.296 ;
     RECT  5.404 105.648 5.651 105.672 ;
     RECT  5.404 75.36 5.692 75.384 ;
     RECT  5.404 62.544 5.699 63.24 ;
     RECT  5.404 36.48 5.717 36.504 ;
     RECT  5.404 37.584 5.717 37.608 ;
     RECT  5.404 56.976 5.725 57 ;
     RECT  5.404 76.896 5.725 77.544 ;
     RECT  5.699 62.592 5.753 63.24 ;
     RECT  5.404 66.144 5.753 67.272 ;
     RECT  5.651 45.312 5.789 45.336 ;
     RECT  5.404 40.176 5.795 40.2 ;
     RECT  5.404 43.872 5.853 43.896 ;
     RECT  5.404 79.968 5.861 81.576 ;
     RECT  5.404 32.256 5.897 32.376 ;
     RECT  5.404 29.472 5.933 30.984 ;
     RECT  5.861 79.968 5.933 80.52 ;
     RECT  5.933 30.384 5.987 30.408 ;
     RECT  5.651 49.68 6.227 49.704 ;
     RECT  5.404 51.552 6.293 53.592 ;
     RECT  5.555 7.392 6.323 8.568 ;
     RECT  6.293 52.224 6.323 53.592 ;
     RECT  5.651 73.248 6.323 74.088 ;
     RECT  5.404 89.904 6.323 90.648 ;
     RECT  6.323 8.544 6.337 8.568 ;
     RECT  5.404 54.72 6.337 54.744 ;
     RECT  5.404 33.984 6.365 35.064 ;
     RECT  5.404 71.76 6.371 72.168 ;
     RECT  5.573 93.456 6.371 94.44 ;
     RECT  5.596 96.96 6.371 96.984 ;
     RECT  6.323 73.248 6.373 73.56 ;
     RECT  5.404 26.208 6.38 26.232 ;
     RECT  6.38 25.296 6.397 26.232 ;
     RECT  5.404 22.992 6.421 23.256 ;
     RECT  5.404 58.512 6.428 58.536 ;
     RECT  5.555 15.36 6.437 15.864 ;
     RECT  5.651 69.696 6.437 70.152 ;
     RECT  6.323 90.624 6.437 90.648 ;
     RECT  5.725 77.232 6.456 77.544 ;
     RECT  5.404 78.624 6.456 78.648 ;
     RECT  6.397 24.528 6.467 26.232 ;
     RECT  6.365 34.896 6.469 35.064 ;
     RECT  5.555 98.304 6.473 98.328 ;
     RECT  6.371 71.856 6.479 72.168 ;
     RECT  6.397 61.536 6.481 61.56 ;
     RECT  5.603 12.528 6.509 12.552 ;
     RECT  6.371 93.456 6.509 93.48 ;
     RECT  6.428 57.552 6.515 58.536 ;
     RECT  5.651 99.552 6.515 99.576 ;
     RECT  5.404 17.088 6.517 17.112 ;
     RECT  6.469 101.472 6.553 101.496 ;
     RECT  6.476 18.96 6.563 18.984 ;
     RECT  6.476 33.408 6.563 33.432 ;
     RECT  6.456 77.232 6.563 78.648 ;
     RECT  5.753 67.248 6.572 67.272 ;
     RECT  5.555 85.776 6.572 85.8 ;
     RECT  6.323 7.392 6.581 7.416 ;
     RECT  6.563 77.808 6.589 78.648 ;
     RECT  6.517 17.088 6.613 17.544 ;
     RECT  5.404 64.704 6.613 64.728 ;
     RECT  6.613 17.088 6.617 18.216 ;
     RECT  5.581 88.32 6.617 88.344 ;
     RECT  6.613 64.704 6.649 65.16 ;
     RECT  6.421 22.752 6.653 23.352 ;
     RECT  6.617 17.088 6.659 17.112 ;
     RECT  6.653 22.752 6.659 23.016 ;
     RECT  6.397 28.992 6.659 29.016 ;
     RECT  6.517 31.536 6.659 31.56 ;
     RECT  6.469 40.224 6.659 40.248 ;
     RECT  6.572 67.248 6.659 67.8 ;
     RECT  6.479 71.856 6.659 72.696 ;
     RECT  5.555 83.76 6.659 83.784 ;
     RECT  6.572 84.864 6.659 85.8 ;
     RECT  6.572 87.264 6.659 87.288 ;
     RECT  6.589 77.808 6.689 77.832 ;
     RECT  5.933 80.496 6.689 80.52 ;
     RECT  6.613 38.736 6.697 38.76 ;
     RECT  6.467 24.528 6.709 25.08 ;
     RECT  6.397 27.984 6.716 28.008 ;
     RECT  6.709 50.544 6.721 50.568 ;
     RECT  6.437 15.84 6.725 15.864 ;
     RECT  5.753 66.144 6.749 66.168 ;
     RECT  6.659 67.248 6.749 67.272 ;
     RECT  6.659 22.992 6.755 23.016 ;
     RECT  5.651 47.856 6.755 47.88 ;
     RECT  5.753 62.592 6.755 62.616 ;
     RECT  6.649 63.744 6.755 65.16 ;
     RECT  6.668 68.592 6.755 68.616 ;
     RECT  6.437 69.696 6.755 69.72 ;
     RECT  6.716 27.744 6.757 28.008 ;
     RECT  5.555 6 6.761 6.024 ;
     RECT  6.469 34.896 6.761 35.736 ;
     RECT  6.517 81.84 6.761 81.864 ;
     RECT  6.515 58.512 6.785 58.536 ;
     RECT  6.721 50.544 6.796 50.712 ;
     RECT  6.709 24.336 6.797 25.08 ;
     RECT  6.709 49.2 6.797 49.224 ;
     RECT  6.797 25.056 6.803 25.08 ;
     RECT  6.757 27.744 6.803 28.536 ;
     RECT  6.716 42.72 6.803 43.56 ;
     RECT  6.716 46.464 6.803 46.488 ;
     RECT  6.749 66.144 6.803 67.272 ;
     RECT  6.796 50.688 6.805 50.712 ;
     RECT  6.467 26.208 6.833 26.232 ;
     RECT  6.803 66.672 6.833 67.272 ;
     RECT  6.617 18.192 7.808 18.216 ;
     RECT  6.803 28.512 7.808 28.536 ;
     RECT  6.761 35.328 7.808 35.736 ;
     RECT  6.323 52.224 7.808 53.112 ;
     RECT  6.785 58.512 7.808 59.256 ;
     RECT  6.505 60.24 7.808 60.264 ;
     RECT  6.755 64.176 7.808 64.2 ;
     RECT  6.659 71.856 7.808 71.88 ;
     RECT  7.808 2.148 7.912 105.852 ;
     RECT  7.912 2.418 8.104 105.582 ;
     RECT  10.508 2.148 10.612 105.852 ;
     RECT  10.612 2.418 10.804 105.582 ;
     RECT  10.804 2.688 11.941 2.712 ;
     RECT  11.905 4.608 11.941 4.632 ;
     RECT  10.804 6.048 11.941 6.072 ;
     RECT  10.804 8.448 11.941 8.472 ;
     RECT  10.804 10.848 11.941 10.872 ;
     RECT  10.804 14.688 11.941 15.192 ;
     RECT  10.804 19.488 11.941 19.512 ;
     RECT  10.804 21.408 11.941 21.432 ;
     RECT  10.804 23.328 11.941 23.832 ;
     RECT  10.804 25.248 11.941 25.272 ;
     RECT  10.804 28.128 11.941 28.152 ;
     RECT  10.804 30.048 11.941 30.072 ;
     RECT  10.804 31.44 11.941 31.464 ;
     RECT  10.804 35.76 11.941 36.264 ;
     RECT  10.804 38.16 11.941 38.184 ;
     RECT  10.804 39.6 11.941 40.584 ;
     RECT  10.804 44.88 11.941 46.344 ;
     RECT  10.804 49.2 11.941 49.224 ;
     RECT  10.804 51.6 11.941 51.624 ;
     RECT  10.804 53.52 11.941 53.544 ;
     RECT  10.804 57.36 11.941 57.864 ;
     RECT  10.804 59.76 11.941 59.784 ;
     RECT  10.804 61.2 11.941 61.224 ;
     RECT  10.804 64.032 11.941 64.056 ;
     RECT  10.804 65.472 11.941 65.976 ;
     RECT  10.804 68.352 11.941 68.376 ;
     RECT  10.804 70.272 11.941 70.296 ;
     RECT  10.804 72.672 11.941 74.616 ;
     RECT  10.804 76.512 11.941 77.016 ;
     RECT  10.804 80.832 11.941 82.296 ;
     RECT  10.804 85.632 11.941 85.656 ;
     RECT  10.804 87.552 11.941 87.576 ;
     RECT  10.804 88.992 11.941 89.976 ;
     RECT  10.804 95.664 11.941 95.688 ;
     RECT  10.804 98.064 11.941 98.088 ;
     RECT  10.804 101.904 11.941 102.408 ;
     RECT  10.804 105.264 11.941 105.288 ;
     RECT  11.941 2.208 11.977 6.072 ;
     RECT  11.941 8.448 11.977 105.288 ;
     RECT  11.977 2.208 12.924 105.768 ;
    LAYER M5 ;
     RECT  2.4 2.137 2.52 2.151 ;
     RECT  5.1 2.137 5.22 2.151 ;
     RECT  7.8 2.137 7.92 2.151 ;
     RECT  10.5 2.137 10.62 2.151 ;
     RECT  5.1 2.151 5.412 3.397 ;
     RECT  5.1 3.397 5.544 7.381 ;
     RECT  5.1 7.381 6.312 8.579 ;
     RECT  5.1 8.579 5.544 10.213 ;
     RECT  5.1 10.213 5.592 13.043 ;
     RECT  0.192 2.965 0.216 14.053 ;
     RECT  5.1 13.043 5.544 15.349 ;
     RECT  5.1 15.349 5.976 15.829 ;
     RECT  0.192 14.053 0.312 16.019 ;
     RECT  0.192 16.019 0.216 18.133 ;
     RECT  0.192 18.133 0.312 18.275 ;
     RECT  0.192 18.275 0.216 21.013 ;
     RECT  0.192 21.013 0.312 21.155 ;
     RECT  5.1 15.829 6.648 22.981 ;
     RECT  0.192 21.155 0.216 24.277 ;
     RECT  0.192 24.277 0.312 24.563 ;
     RECT  5.1 22.981 6.744 25.045 ;
     RECT  5.1 25.045 6.792 26.243 ;
     RECT  0.192 24.563 0.216 26.629 ;
     RECT  0.192 26.629 0.312 26.819 ;
     RECT  5.1 26.243 6.456 27.733 ;
     RECT  5.1 27.733 6.792 28.547 ;
     RECT  5.1 28.547 6.648 30.709 ;
     RECT  4.992 30.709 6.648 31.571 ;
     RECT  0.192 26.819 0.216 33.157 ;
     RECT  0.192 33.157 0.312 33.589 ;
     RECT  0.192 33.589 0.408 33.923 ;
     RECT  4.992 31.571 6.552 34.931 ;
     RECT  0.192 33.923 0.216 36.373 ;
     RECT  0.192 36.373 0.312 36.515 ;
     RECT  4.992 34.931 6.216 38.725 ;
     RECT  4.992 38.725 6.648 40.259 ;
     RECT  4.992 40.259 6.216 42.709 ;
     RECT  4.992 42.709 6.792 46.499 ;
     RECT  4.992 46.499 6.216 47.221 ;
     RECT  4.608 47.221 6.216 47.845 ;
     RECT  4.608 47.845 6.744 50.677 ;
     RECT  0.192 36.515 0.216 51.733 ;
     RECT  0.192 51.733 0.312 51.923 ;
     RECT  4.608 50.677 6.792 52.309 ;
     RECT  7.8 2.151 8.112 52.309 ;
     RECT  0.192 51.923 0.216 52.835 ;
     RECT  4.608 52.309 8.112 53.123 ;
     RECT  4.608 53.123 6.312 54.755 ;
     RECT  4.608 54.755 5.784 56.675 ;
     RECT  4.8 56.675 5.784 57.541 ;
     RECT  4.8 57.541 6.504 58.501 ;
     RECT  7.8 53.123 8.112 58.501 ;
     RECT  4.8 58.501 8.112 58.547 ;
     RECT  0.144 58.117 0.168 58.645 ;
     RECT  0.144 58.645 0.216 58.787 ;
     RECT  0.192 58.787 0.216 59.267 ;
     RECT  4.8 58.547 5.784 59.795 ;
     RECT  6.816 58.547 8.112 60.275 ;
     RECT  4.992 59.795 5.784 61.525 ;
     RECT  4.992 61.525 6.456 62.581 ;
     RECT  0.144 60.613 0.168 62.771 ;
     RECT  0.144 64.789 0.168 65.027 ;
     RECT  4.992 62.581 6.744 65.171 ;
     RECT  4.992 65.171 6.456 66.133 ;
     RECT  4.992 66.133 6.792 66.707 ;
     RECT  4.992 66.707 6.744 69.731 ;
     RECT  4.992 69.731 6.648 72.707 ;
     RECT  4.992 72.707 6.552 73.957 ;
     RECT  4.368 73.957 6.552 79.621 ;
     RECT  4.32 79.621 6.552 81.829 ;
     RECT  4.32 81.829 6.648 81.875 ;
     RECT  4.32 81.875 5.592 86.483 ;
     RECT  6.624 81.875 6.648 87.299 ;
     RECT  4.56 86.483 5.592 88.309 ;
     RECT  4.56 88.309 6.312 89.939 ;
     RECT  4.56 89.939 5.592 90.659 ;
     RECT  4.56 90.659 5.544 93.445 ;
     RECT  4.56 93.445 6.36 94.307 ;
     RECT  4.992 94.307 6.36 98.339 ;
     RECT  4.992 98.339 5.544 99.541 ;
     RECT  4.992 99.541 6.504 100.981 ;
     RECT  4.368 100.981 6.504 101.507 ;
     RECT  4.368 101.507 5.64 103.763 ;
     RECT  5.1 103.763 5.64 105.683 ;
     RECT  2.4 2.151 2.712 105.849 ;
     RECT  5.1 105.683 5.412 105.849 ;
     RECT  7.8 60.275 8.112 105.849 ;
     RECT  10.5 2.151 10.812 105.849 ;
     RECT  2.4 105.849 2.52 105.863 ;
     RECT  5.1 105.849 5.22 105.863 ;
     RECT  7.8 105.849 7.92 105.863 ;
     RECT  10.5 105.849 10.62 105.863 ;
  END
END vm_cp_rwb
END LIBRARY
